VERSION 5.8 ;
BUSBITCHARS "[]" ;
DIVIDERCHAR "/" ;
UNITS
    DATABASE MICRONS 1000 ;
END UNITS

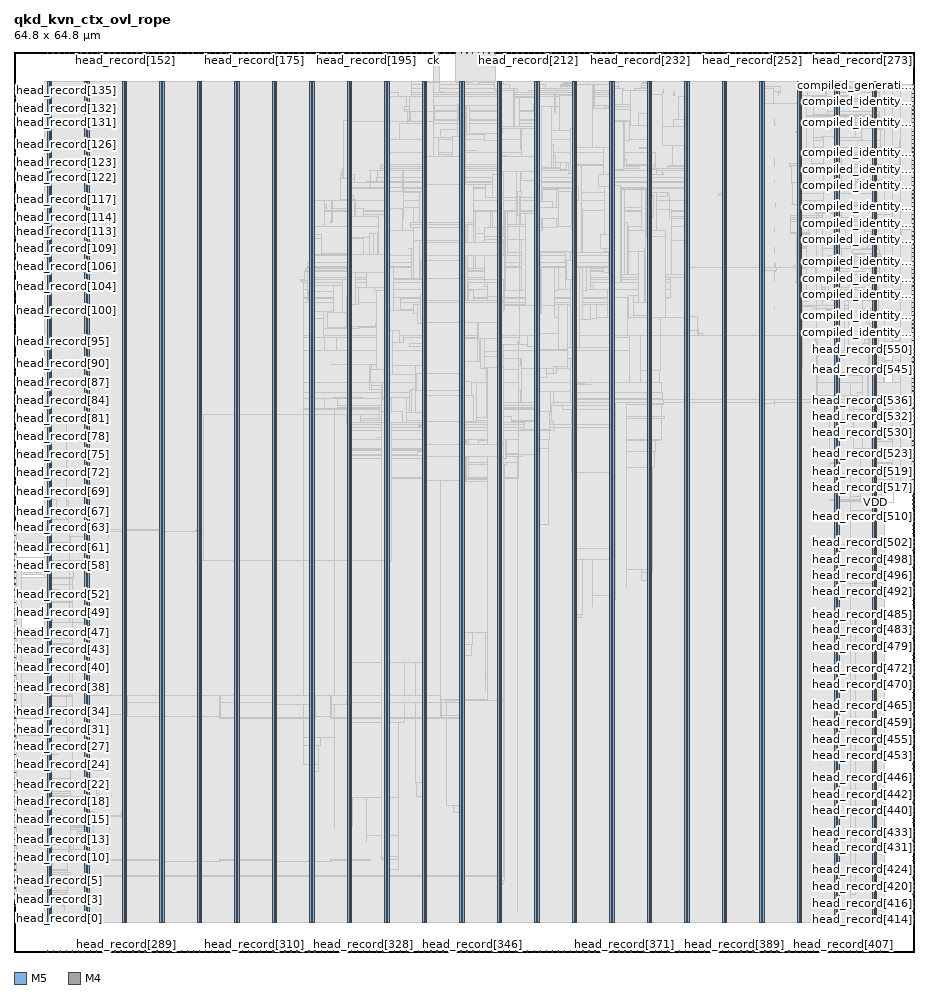
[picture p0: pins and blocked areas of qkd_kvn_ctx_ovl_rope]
MACRO qkd_kvn_ctx_ovl_rope
  FOREIGN qkd_kvn_ctx_ovl_rope 0 0 ;
  CLASS BLOCK ;
  SIZE 64.8 BY 64.8 ;
  PIN adm_done
    DIRECTION INPUT ;
    USE SIGNAL ;
    PORT
      LAYER M5 ;
        RECT  34.176 64.716 34.2 64.8 ;
    END
  END adm_done
  PIN calrx[0]
    DIRECTION INPUT ;
    USE SIGNAL ;
    PORT
      LAYER M5 ;
        RECT  32.592 64.716 32.616 64.8 ;
    END
  END calrx[0]
  PIN calrx[1]
    DIRECTION INPUT ;
    USE SIGNAL ;
    PORT
      LAYER M5 ;
        RECT  32.976 64.716 33 64.8 ;
    END
  END calrx[1]
  PIN calrx[2]
    DIRECTION INPUT ;
    USE SIGNAL ;
    PORT
      LAYER M5 ;
        RECT  33.408 64.716 33.432 64.8 ;
    END
  END calrx[2]
  PIN calrx[3]
    DIRECTION INPUT ;
    USE SIGNAL ;
    PORT
      LAYER M5 ;
        RECT  33.792 64.716 33.816 64.8 ;
    END
  END calrx[3]
  PIN ck
    DIRECTION INPUT ;
    USE SIGNAL ;
    PORT
      LAYER M5 ;
        RECT  30.192 64.716 30.216 64.8 ;
    END
  END ck
  PIN compiled_generation[0]
    DIRECTION OUTPUT ;
    USE SIGNAL ;
    PORT
      LAYER M4 ;
        RECT  64.716 61.824 64.8 61.848 ;
    END
  END compiled_generation[0]
  PIN compiled_generation[1]
    DIRECTION OUTPUT ;
    USE SIGNAL ;
    PORT
      LAYER M4 ;
        RECT  64.716 62.112 64.8 62.136 ;
    END
  END compiled_generation[1]
  PIN compiled_identity[0]
    DIRECTION OUTPUT ;
    USE SIGNAL ;
    PORT
      LAYER M4 ;
        RECT  64.716 44.016 64.8 44.04 ;
    END
  END compiled_identity[0]
  PIN compiled_identity[10]
    DIRECTION OUTPUT ;
    USE SIGNAL ;
    PORT
      LAYER M4 ;
        RECT  64.716 47.04 64.8 47.064 ;
    END
  END compiled_identity[10]
  PIN compiled_identity[11]
    DIRECTION OUTPUT ;
    USE SIGNAL ;
    PORT
      LAYER M4 ;
        RECT  64.716 47.328 64.8 47.352 ;
    END
  END compiled_identity[11]
  PIN compiled_identity[12]
    DIRECTION OUTPUT ;
    USE SIGNAL ;
    PORT
      LAYER M4 ;
        RECT  64.716 47.616 64.8 47.64 ;
    END
  END compiled_identity[12]
  PIN compiled_identity[13]
    DIRECTION OUTPUT ;
    USE SIGNAL ;
    PORT
      LAYER M4 ;
        RECT  64.716 47.952 64.8 47.976 ;
    END
  END compiled_identity[13]
  PIN compiled_identity[14]
    DIRECTION OUTPUT ;
    USE SIGNAL ;
    PORT
      LAYER M4 ;
        RECT  64.716 48.24 64.8 48.264 ;
    END
  END compiled_identity[14]
  PIN compiled_identity[15]
    DIRECTION OUTPUT ;
    USE SIGNAL ;
    PORT
      LAYER M4 ;
        RECT  64.716 48.528 64.8 48.552 ;
    END
  END compiled_identity[15]
  PIN compiled_identity[16]
    DIRECTION OUTPUT ;
    USE SIGNAL ;
    PORT
      LAYER M4 ;
        RECT  64.716 48.864 64.8 48.888 ;
    END
  END compiled_identity[16]
  PIN compiled_identity[17]
    DIRECTION OUTPUT ;
    USE SIGNAL ;
    PORT
      LAYER M4 ;
        RECT  64.716 49.152 64.8 49.176 ;
    END
  END compiled_identity[17]
  PIN compiled_identity[18]
    DIRECTION OUTPUT ;
    USE SIGNAL ;
    PORT
      LAYER M4 ;
        RECT  64.716 49.44 64.8 49.464 ;
    END
  END compiled_identity[18]
  PIN compiled_identity[19]
    DIRECTION OUTPUT ;
    USE SIGNAL ;
    PORT
      LAYER M4 ;
        RECT  64.716 49.728 64.8 49.752 ;
    END
  END compiled_identity[19]
  PIN compiled_identity[1]
    DIRECTION OUTPUT ;
    USE SIGNAL ;
    PORT
      LAYER M4 ;
        RECT  64.716 44.304 64.8 44.328 ;
    END
  END compiled_identity[1]
  PIN compiled_identity[20]
    DIRECTION OUTPUT ;
    USE SIGNAL ;
    PORT
      LAYER M4 ;
        RECT  64.716 50.064 64.8 50.088 ;
    END
  END compiled_identity[20]
  PIN compiled_identity[21]
    DIRECTION OUTPUT ;
    USE SIGNAL ;
    PORT
      LAYER M4 ;
        RECT  64.716 50.352 64.8 50.376 ;
    END
  END compiled_identity[21]
  PIN compiled_identity[22]
    DIRECTION OUTPUT ;
    USE SIGNAL ;
    PORT
      LAYER M4 ;
        RECT  64.716 50.64 64.8 50.664 ;
    END
  END compiled_identity[22]
  PIN compiled_identity[23]
    DIRECTION OUTPUT ;
    USE SIGNAL ;
    PORT
      LAYER M4 ;
        RECT  64.716 50.976 64.8 51 ;
    END
  END compiled_identity[23]
  PIN compiled_identity[24]
    DIRECTION OUTPUT ;
    USE SIGNAL ;
    PORT
      LAYER M4 ;
        RECT  64.716 51.264 64.8 51.288 ;
    END
  END compiled_identity[24]
  PIN compiled_identity[25]
    DIRECTION OUTPUT ;
    USE SIGNAL ;
    PORT
      LAYER M4 ;
        RECT  64.716 51.552 64.8 51.576 ;
    END
  END compiled_identity[25]
  PIN compiled_identity[26]
    DIRECTION OUTPUT ;
    USE SIGNAL ;
    PORT
      LAYER M4 ;
        RECT  64.716 51.84 64.8 51.864 ;
    END
  END compiled_identity[26]
  PIN compiled_identity[27]
    DIRECTION OUTPUT ;
    USE SIGNAL ;
    PORT
      LAYER M4 ;
        RECT  64.716 52.176 64.8 52.2 ;
    END
  END compiled_identity[27]
  PIN compiled_identity[28]
    DIRECTION OUTPUT ;
    USE SIGNAL ;
    PORT
      LAYER M4 ;
        RECT  64.716 52.464 64.8 52.488 ;
    END
  END compiled_identity[28]
  PIN compiled_identity[29]
    DIRECTION OUTPUT ;
    USE SIGNAL ;
    PORT
      LAYER M4 ;
        RECT  64.716 52.752 64.8 52.776 ;
    END
  END compiled_identity[29]
  PIN compiled_identity[2]
    DIRECTION OUTPUT ;
    USE SIGNAL ;
    PORT
      LAYER M4 ;
        RECT  64.716 44.592 64.8 44.616 ;
    END
  END compiled_identity[2]
  PIN compiled_identity[30]
    DIRECTION OUTPUT ;
    USE SIGNAL ;
    PORT
      LAYER M4 ;
        RECT  64.716 53.088 64.8 53.112 ;
    END
  END compiled_identity[30]
  PIN compiled_identity[31]
    DIRECTION OUTPUT ;
    USE SIGNAL ;
    PORT
      LAYER M4 ;
        RECT  64.716 53.376 64.8 53.4 ;
    END
  END compiled_identity[31]
  PIN compiled_identity[32]
    DIRECTION OUTPUT ;
    USE SIGNAL ;
    PORT
      LAYER M4 ;
        RECT  64.716 53.664 64.8 53.688 ;
    END
  END compiled_identity[32]
  PIN compiled_identity[33]
    DIRECTION OUTPUT ;
    USE SIGNAL ;
    PORT
      LAYER M4 ;
        RECT  64.716 53.952 64.8 53.976 ;
    END
  END compiled_identity[33]
  PIN compiled_identity[34]
    DIRECTION OUTPUT ;
    USE SIGNAL ;
    PORT
      LAYER M4 ;
        RECT  64.716 54.288 64.8 54.312 ;
    END
  END compiled_identity[34]
  PIN compiled_identity[35]
    DIRECTION OUTPUT ;
    USE SIGNAL ;
    PORT
      LAYER M4 ;
        RECT  64.716 54.576 64.8 54.6 ;
    END
  END compiled_identity[35]
  PIN compiled_identity[36]
    DIRECTION OUTPUT ;
    USE SIGNAL ;
    PORT
      LAYER M4 ;
        RECT  64.716 54.864 64.8 54.888 ;
    END
  END compiled_identity[36]
  PIN compiled_identity[37]
    DIRECTION OUTPUT ;
    USE SIGNAL ;
    PORT
      LAYER M4 ;
        RECT  64.716 55.2 64.8 55.224 ;
    END
  END compiled_identity[37]
  PIN compiled_identity[38]
    DIRECTION OUTPUT ;
    USE SIGNAL ;
    PORT
      LAYER M4 ;
        RECT  64.716 55.488 64.8 55.512 ;
    END
  END compiled_identity[38]
  PIN compiled_identity[39]
    DIRECTION OUTPUT ;
    USE SIGNAL ;
    PORT
      LAYER M4 ;
        RECT  64.716 55.776 64.8 55.8 ;
    END
  END compiled_identity[39]
  PIN compiled_identity[3]
    DIRECTION OUTPUT ;
    USE SIGNAL ;
    PORT
      LAYER M4 ;
        RECT  64.716 44.928 64.8 44.952 ;
    END
  END compiled_identity[3]
  PIN compiled_identity[40]
    DIRECTION OUTPUT ;
    USE SIGNAL ;
    PORT
      LAYER M4 ;
        RECT  64.716 56.112 64.8 56.136 ;
    END
  END compiled_identity[40]
  PIN compiled_identity[41]
    DIRECTION OUTPUT ;
    USE SIGNAL ;
    PORT
      LAYER M4 ;
        RECT  64.716 56.4 64.8 56.424 ;
    END
  END compiled_identity[41]
  PIN compiled_identity[42]
    DIRECTION OUTPUT ;
    USE SIGNAL ;
    PORT
      LAYER M4 ;
        RECT  64.716 56.688 64.8 56.712 ;
    END
  END compiled_identity[42]
  PIN compiled_identity[43]
    DIRECTION OUTPUT ;
    USE SIGNAL ;
    PORT
      LAYER M4 ;
        RECT  64.716 56.976 64.8 57 ;
    END
  END compiled_identity[43]
  PIN compiled_identity[44]
    DIRECTION OUTPUT ;
    USE SIGNAL ;
    PORT
      LAYER M4 ;
        RECT  64.716 57.312 64.8 57.336 ;
    END
  END compiled_identity[44]
  PIN compiled_identity[45]
    DIRECTION OUTPUT ;
    USE SIGNAL ;
    PORT
      LAYER M4 ;
        RECT  64.716 57.6 64.8 57.624 ;
    END
  END compiled_identity[45]
  PIN compiled_identity[46]
    DIRECTION OUTPUT ;
    USE SIGNAL ;
    PORT
      LAYER M4 ;
        RECT  64.716 57.888 64.8 57.912 ;
    END
  END compiled_identity[46]
  PIN compiled_identity[47]
    DIRECTION OUTPUT ;
    USE SIGNAL ;
    PORT
      LAYER M4 ;
        RECT  64.716 58.224 64.8 58.248 ;
    END
  END compiled_identity[47]
  PIN compiled_identity[48]
    DIRECTION OUTPUT ;
    USE SIGNAL ;
    PORT
      LAYER M4 ;
        RECT  64.716 58.512 64.8 58.536 ;
    END
  END compiled_identity[48]
  PIN compiled_identity[49]
    DIRECTION OUTPUT ;
    USE SIGNAL ;
    PORT
      LAYER M4 ;
        RECT  64.716 58.8 64.8 58.824 ;
    END
  END compiled_identity[49]
  PIN compiled_identity[4]
    DIRECTION OUTPUT ;
    USE SIGNAL ;
    PORT
      LAYER M4 ;
        RECT  64.716 45.216 64.8 45.24 ;
    END
  END compiled_identity[4]
  PIN compiled_identity[50]
    DIRECTION OUTPUT ;
    USE SIGNAL ;
    PORT
      LAYER M4 ;
        RECT  64.716 59.088 64.8 59.112 ;
    END
  END compiled_identity[50]
  PIN compiled_identity[51]
    DIRECTION OUTPUT ;
    USE SIGNAL ;
    PORT
      LAYER M4 ;
        RECT  64.716 59.424 64.8 59.448 ;
    END
  END compiled_identity[51]
  PIN compiled_identity[52]
    DIRECTION OUTPUT ;
    USE SIGNAL ;
    PORT
      LAYER M4 ;
        RECT  64.716 59.712 64.8 59.736 ;
    END
  END compiled_identity[52]
  PIN compiled_identity[53]
    DIRECTION OUTPUT ;
    USE SIGNAL ;
    PORT
      LAYER M4 ;
        RECT  64.716 60 64.8 60.024 ;
    END
  END compiled_identity[53]
  PIN compiled_identity[54]
    DIRECTION OUTPUT ;
    USE SIGNAL ;
    PORT
      LAYER M4 ;
        RECT  64.716 60.336 64.8 60.36 ;
    END
  END compiled_identity[54]
  PIN compiled_identity[55]
    DIRECTION OUTPUT ;
    USE SIGNAL ;
    PORT
      LAYER M4 ;
        RECT  64.716 60.624 64.8 60.648 ;
    END
  END compiled_identity[55]
  PIN compiled_identity[56]
    DIRECTION OUTPUT ;
    USE SIGNAL ;
    PORT
      LAYER M4 ;
        RECT  64.716 60.912 64.8 60.936 ;
    END
  END compiled_identity[56]
  PIN compiled_identity[57]
    DIRECTION OUTPUT ;
    USE SIGNAL ;
    PORT
      LAYER M4 ;
        RECT  64.716 61.2 64.8 61.224 ;
    END
  END compiled_identity[57]
  PIN compiled_identity[58]
    DIRECTION OUTPUT ;
    USE SIGNAL ;
    PORT
      LAYER M4 ;
        RECT  64.716 61.536 64.8 61.56 ;
    END
  END compiled_identity[58]
  PIN compiled_identity[5]
    DIRECTION OUTPUT ;
    USE SIGNAL ;
    PORT
      LAYER M4 ;
        RECT  64.716 45.504 64.8 45.528 ;
    END
  END compiled_identity[5]
  PIN compiled_identity[6]
    DIRECTION OUTPUT ;
    USE SIGNAL ;
    PORT
      LAYER M4 ;
        RECT  64.716 45.84 64.8 45.864 ;
    END
  END compiled_identity[6]
  PIN compiled_identity[7]
    DIRECTION OUTPUT ;
    USE SIGNAL ;
    PORT
      LAYER M4 ;
        RECT  64.716 46.128 64.8 46.152 ;
    END
  END compiled_identity[7]
  PIN compiled_identity[8]
    DIRECTION OUTPUT ;
    USE SIGNAL ;
    PORT
      LAYER M4 ;
        RECT  64.716 46.416 64.8 46.44 ;
    END
  END compiled_identity[8]
  PIN compiled_identity[9]
    DIRECTION OUTPUT ;
    USE SIGNAL ;
    PORT
      LAYER M4 ;
        RECT  64.716 46.752 64.8 46.776 ;
    END
  END compiled_identity[9]
  PIN fault
    DIRECTION OUTPUT ;
    USE SIGNAL ;
    PORT
      LAYER M4 ;
        RECT  64.716 62.448 64.8 62.472 ;
    END
  END fault
  PIN head_record[0]
    DIRECTION INPUT ;
    USE SIGNAL ;
    PORT
      LAYER M4 ;
        RECT  0 2.4 0.084 2.424 ;
    END
  END head_record[0]
  PIN head_record[100]
    DIRECTION INPUT ;
    USE SIGNAL ;
    PORT
      LAYER M4 ;
        RECT  0 46.176 0.084 46.2 ;
    END
  END head_record[100]
  PIN head_record[101]
    DIRECTION INPUT ;
    USE SIGNAL ;
    PORT
      LAYER M4 ;
        RECT  0 46.608 0.084 46.632 ;
    END
  END head_record[101]
  PIN head_record[102]
    DIRECTION INPUT ;
    USE SIGNAL ;
    PORT
      LAYER M4 ;
        RECT  0 47.04 0.084 47.064 ;
    END
  END head_record[102]
  PIN head_record[103]
    DIRECTION INPUT ;
    USE SIGNAL ;
    PORT
      LAYER M4 ;
        RECT  0 47.472 0.084 47.496 ;
    END
  END head_record[103]
  PIN head_record[104]
    DIRECTION INPUT ;
    USE SIGNAL ;
    PORT
      LAYER M4 ;
        RECT  0 47.904 0.084 47.928 ;
    END
  END head_record[104]
  PIN head_record[105]
    DIRECTION INPUT ;
    USE SIGNAL ;
    PORT
      LAYER M4 ;
        RECT  0 48.336 0.084 48.36 ;
    END
  END head_record[105]
  PIN head_record[106]
    DIRECTION INPUT ;
    USE SIGNAL ;
    PORT
      LAYER M4 ;
        RECT  0 48.816 0.084 48.84 ;
    END
  END head_record[106]
  PIN head_record[107]
    DIRECTION INPUT ;
    USE SIGNAL ;
    PORT
      LAYER M4 ;
        RECT  0 49.248 0.084 49.272 ;
    END
  END head_record[107]
  PIN head_record[108]
    DIRECTION INPUT ;
    USE SIGNAL ;
    PORT
      LAYER M4 ;
        RECT  0 49.68 0.084 49.704 ;
    END
  END head_record[108]
  PIN head_record[109]
    DIRECTION INPUT ;
    USE SIGNAL ;
    PORT
      LAYER M4 ;
        RECT  0 50.112 0.084 50.136 ;
    END
  END head_record[109]
  PIN head_record[10]
    DIRECTION INPUT ;
    USE SIGNAL ;
    PORT
      LAYER M4 ;
        RECT  0 6.768 0.084 6.792 ;
    END
  END head_record[10]
  PIN head_record[110]
    DIRECTION INPUT ;
    USE SIGNAL ;
    PORT
      LAYER M4 ;
        RECT  0 50.544 0.084 50.568 ;
    END
  END head_record[110]
  PIN head_record[111]
    DIRECTION INPUT ;
    USE SIGNAL ;
    PORT
      LAYER M4 ;
        RECT  0 50.976 0.084 51 ;
    END
  END head_record[111]
  PIN head_record[112]
    DIRECTION INPUT ;
    USE SIGNAL ;
    PORT
      LAYER M4 ;
        RECT  0 51.408 0.084 51.432 ;
    END
  END head_record[112]
  PIN head_record[113]
    DIRECTION INPUT ;
    USE SIGNAL ;
    PORT
      LAYER M4 ;
        RECT  0 51.84 0.084 51.864 ;
    END
  END head_record[113]
  PIN head_record[114]
    DIRECTION INPUT ;
    USE SIGNAL ;
    PORT
      LAYER M4 ;
        RECT  0 52.32 0.084 52.344 ;
    END
  END head_record[114]
  PIN head_record[115]
    DIRECTION INPUT ;
    USE SIGNAL ;
    PORT
      LAYER M4 ;
        RECT  0 52.752 0.084 52.776 ;
    END
  END head_record[115]
  PIN head_record[116]
    DIRECTION INPUT ;
    USE SIGNAL ;
    PORT
      LAYER M4 ;
        RECT  0 53.184 0.084 53.208 ;
    END
  END head_record[116]
  PIN head_record[117]
    DIRECTION INPUT ;
    USE SIGNAL ;
    PORT
      LAYER M4 ;
        RECT  0 53.616 0.084 53.64 ;
    END
  END head_record[117]
  PIN head_record[118]
    DIRECTION INPUT ;
    USE SIGNAL ;
    PORT
      LAYER M4 ;
        RECT  0 54.048 0.084 54.072 ;
    END
  END head_record[118]
  PIN head_record[119]
    DIRECTION INPUT ;
    USE SIGNAL ;
    PORT
      LAYER M4 ;
        RECT  0 54.48 0.084 54.504 ;
    END
  END head_record[119]
  PIN head_record[11]
    DIRECTION INPUT ;
    USE SIGNAL ;
    PORT
      LAYER M4 ;
        RECT  0 7.248 0.084 7.272 ;
    END
  END head_record[11]
  PIN head_record[120]
    DIRECTION INPUT ;
    USE SIGNAL ;
    PORT
      LAYER M4 ;
        RECT  0 54.912 0.084 54.936 ;
    END
  END head_record[120]
  PIN head_record[121]
    DIRECTION INPUT ;
    USE SIGNAL ;
    PORT
      LAYER M4 ;
        RECT  0 55.344 0.084 55.368 ;
    END
  END head_record[121]
  PIN head_record[122]
    DIRECTION INPUT ;
    USE SIGNAL ;
    PORT
      LAYER M4 ;
        RECT  0 55.776 0.084 55.8 ;
    END
  END head_record[122]
  PIN head_record[123]
    DIRECTION INPUT ;
    USE SIGNAL ;
    PORT
      LAYER M4 ;
        RECT  0 56.256 0.084 56.28 ;
    END
  END head_record[123]
  PIN head_record[124]
    DIRECTION INPUT ;
    USE SIGNAL ;
    PORT
      LAYER M4 ;
        RECT  0 56.688 0.084 56.712 ;
    END
  END head_record[124]
  PIN head_record[125]
    DIRECTION INPUT ;
    USE SIGNAL ;
    PORT
      LAYER M4 ;
        RECT  0 57.12 0.084 57.144 ;
    END
  END head_record[125]
  PIN head_record[126]
    DIRECTION INPUT ;
    USE SIGNAL ;
    PORT
      LAYER M4 ;
        RECT  0 57.552 0.084 57.576 ;
    END
  END head_record[126]
  PIN head_record[127]
    DIRECTION INPUT ;
    USE SIGNAL ;
    PORT
      LAYER M4 ;
        RECT  0 57.984 0.084 58.008 ;
    END
  END head_record[127]
  PIN head_record[128]
    DIRECTION INPUT ;
    USE SIGNAL ;
    PORT
      LAYER M4 ;
        RECT  0 58.416 0.084 58.44 ;
    END
  END head_record[128]
  PIN head_record[129]
    DIRECTION INPUT ;
    USE SIGNAL ;
    PORT
      LAYER M4 ;
        RECT  0 58.848 0.084 58.872 ;
    END
  END head_record[129]
  PIN head_record[12]
    DIRECTION INPUT ;
    USE SIGNAL ;
    PORT
      LAYER M4 ;
        RECT  0 7.68 0.084 7.704 ;
    END
  END head_record[12]
  PIN head_record[130]
    DIRECTION INPUT ;
    USE SIGNAL ;
    PORT
      LAYER M4 ;
        RECT  0 59.28 0.084 59.304 ;
    END
  END head_record[130]
  PIN head_record[131]
    DIRECTION INPUT ;
    USE SIGNAL ;
    PORT
      LAYER M4 ;
        RECT  0 59.712 0.084 59.736 ;
    END
  END head_record[131]
  PIN head_record[132]
    DIRECTION INPUT ;
    USE SIGNAL ;
    PORT
      LAYER M4 ;
        RECT  0 60.192 0.084 60.216 ;
    END
  END head_record[132]
  PIN head_record[133]
    DIRECTION INPUT ;
    USE SIGNAL ;
    PORT
      LAYER M4 ;
        RECT  0 60.624 0.084 60.648 ;
    END
  END head_record[133]
  PIN head_record[134]
    DIRECTION INPUT ;
    USE SIGNAL ;
    PORT
      LAYER M4 ;
        RECT  0 61.056 0.084 61.08 ;
    END
  END head_record[134]
  PIN head_record[135]
    DIRECTION INPUT ;
    USE SIGNAL ;
    PORT
      LAYER M4 ;
        RECT  0 61.488 0.084 61.512 ;
    END
  END head_record[135]
  PIN head_record[136]
    DIRECTION INPUT ;
    USE SIGNAL ;
    PORT
      LAYER M4 ;
        RECT  0 61.92 0.084 61.944 ;
    END
  END head_record[136]
  PIN head_record[137]
    DIRECTION INPUT ;
    USE SIGNAL ;
    PORT
      LAYER M4 ;
        RECT  0 62.352 0.084 62.376 ;
    END
  END head_record[137]
  PIN head_record[138]
    DIRECTION INPUT ;
    USE SIGNAL ;
    PORT
      LAYER M5 ;
        RECT  2.4 64.716 2.424 64.8 ;
    END
  END head_record[138]
  PIN head_record[139]
    DIRECTION INPUT ;
    USE SIGNAL ;
    PORT
      LAYER M5 ;
        RECT  2.784 64.716 2.808 64.8 ;
    END
  END head_record[139]
  PIN head_record[13]
    DIRECTION INPUT ;
    USE SIGNAL ;
    PORT
      LAYER M4 ;
        RECT  0 8.112 0.084 8.136 ;
    END
  END head_record[13]
  PIN head_record[140]
    DIRECTION INPUT ;
    USE SIGNAL ;
    PORT
      LAYER M5 ;
        RECT  3.216 64.716 3.24 64.8 ;
    END
  END head_record[140]
  PIN head_record[141]
    DIRECTION INPUT ;
    USE SIGNAL ;
    PORT
      LAYER M5 ;
        RECT  3.6 64.716 3.624 64.8 ;
    END
  END head_record[141]
  PIN head_record[142]
    DIRECTION INPUT ;
    USE SIGNAL ;
    PORT
      LAYER M5 ;
        RECT  3.984 64.716 4.008 64.8 ;
    END
  END head_record[142]
  PIN head_record[143]
    DIRECTION INPUT ;
    USE SIGNAL ;
    PORT
      LAYER M5 ;
        RECT  4.416 64.716 4.44 64.8 ;
    END
  END head_record[143]
  PIN head_record[144]
    DIRECTION INPUT ;
    USE SIGNAL ;
    PORT
      LAYER M5 ;
        RECT  4.8 64.716 4.824 64.8 ;
    END
  END head_record[144]
  PIN head_record[145]
    DIRECTION INPUT ;
    USE SIGNAL ;
    PORT
      LAYER M5 ;
        RECT  5.232 64.716 5.256 64.8 ;
    END
  END head_record[145]
  PIN head_record[146]
    DIRECTION INPUT ;
    USE SIGNAL ;
    PORT
      LAYER M5 ;
        RECT  5.616 64.716 5.64 64.8 ;
    END
  END head_record[146]
  PIN head_record[147]
    DIRECTION INPUT ;
    USE SIGNAL ;
    PORT
      LAYER M5 ;
        RECT  6 64.716 6.024 64.8 ;
    END
  END head_record[147]
  PIN head_record[148]
    DIRECTION INPUT ;
    USE SIGNAL ;
    PORT
      LAYER M5 ;
        RECT  6.432 64.716 6.456 64.8 ;
    END
  END head_record[148]
  PIN head_record[149]
    DIRECTION INPUT ;
    USE SIGNAL ;
    PORT
      LAYER M5 ;
        RECT  6.816 64.716 6.84 64.8 ;
    END
  END head_record[149]
  PIN head_record[14]
    DIRECTION INPUT ;
    USE SIGNAL ;
    PORT
      LAYER M4 ;
        RECT  0 8.544 0.084 8.568 ;
    END
  END head_record[14]
  PIN head_record[150]
    DIRECTION INPUT ;
    USE SIGNAL ;
    PORT
      LAYER M5 ;
        RECT  7.248 64.716 7.272 64.8 ;
    END
  END head_record[150]
  PIN head_record[151]
    DIRECTION INPUT ;
    USE SIGNAL ;
    PORT
      LAYER M5 ;
        RECT  7.632 64.716 7.656 64.8 ;
    END
  END head_record[151]
  PIN head_record[152]
    DIRECTION INPUT ;
    USE SIGNAL ;
    PORT
      LAYER M5 ;
        RECT  8.016 64.716 8.04 64.8 ;
    END
  END head_record[152]
  PIN head_record[153]
    DIRECTION INPUT ;
    USE SIGNAL ;
    PORT
      LAYER M5 ;
        RECT  8.448 64.716 8.472 64.8 ;
    END
  END head_record[153]
  PIN head_record[154]
    DIRECTION INPUT ;
    USE SIGNAL ;
    PORT
      LAYER M5 ;
        RECT  8.832 64.716 8.856 64.8 ;
    END
  END head_record[154]
  PIN head_record[155]
    DIRECTION INPUT ;
    USE SIGNAL ;
    PORT
      LAYER M5 ;
        RECT  9.264 64.716 9.288 64.8 ;
    END
  END head_record[155]
  PIN head_record[156]
    DIRECTION INPUT ;
    USE SIGNAL ;
    PORT
      LAYER M5 ;
        RECT  9.648 64.716 9.672 64.8 ;
    END
  END head_record[156]
  PIN head_record[157]
    DIRECTION INPUT ;
    USE SIGNAL ;
    PORT
      LAYER M5 ;
        RECT  10.032 64.716 10.056 64.8 ;
    END
  END head_record[157]
  PIN head_record[158]
    DIRECTION INPUT ;
    USE SIGNAL ;
    PORT
      LAYER M5 ;
        RECT  10.464 64.716 10.488 64.8 ;
    END
  END head_record[158]
  PIN head_record[159]
    DIRECTION INPUT ;
    USE SIGNAL ;
    PORT
      LAYER M5 ;
        RECT  10.848 64.716 10.872 64.8 ;
    END
  END head_record[159]
  PIN head_record[15]
    DIRECTION INPUT ;
    USE SIGNAL ;
    PORT
      LAYER M4 ;
        RECT  0 8.976 0.084 9 ;
    END
  END head_record[15]
  PIN head_record[160]
    DIRECTION INPUT ;
    USE SIGNAL ;
    PORT
      LAYER M5 ;
        RECT  11.232 64.716 11.256 64.8 ;
    END
  END head_record[160]
  PIN head_record[161]
    DIRECTION INPUT ;
    USE SIGNAL ;
    PORT
      LAYER M5 ;
        RECT  11.664 64.716 11.688 64.8 ;
    END
  END head_record[161]
  PIN head_record[162]
    DIRECTION INPUT ;
    USE SIGNAL ;
    PORT
      LAYER M5 ;
        RECT  12.048 64.716 12.072 64.8 ;
    END
  END head_record[162]
  PIN head_record[163]
    DIRECTION INPUT ;
    USE SIGNAL ;
    PORT
      LAYER M5 ;
        RECT  12.48 64.716 12.504 64.8 ;
    END
  END head_record[163]
  PIN head_record[164]
    DIRECTION INPUT ;
    USE SIGNAL ;
    PORT
      LAYER M5 ;
        RECT  12.864 64.716 12.888 64.8 ;
    END
  END head_record[164]
  PIN head_record[165]
    DIRECTION INPUT ;
    USE SIGNAL ;
    PORT
      LAYER M5 ;
        RECT  13.248 64.716 13.272 64.8 ;
    END
  END head_record[165]
  PIN head_record[166]
    DIRECTION INPUT ;
    USE SIGNAL ;
    PORT
      LAYER M5 ;
        RECT  13.68 64.716 13.704 64.8 ;
    END
  END head_record[166]
  PIN head_record[167]
    DIRECTION INPUT ;
    USE SIGNAL ;
    PORT
      LAYER M5 ;
        RECT  14.064 64.716 14.088 64.8 ;
    END
  END head_record[167]
  PIN head_record[168]
    DIRECTION INPUT ;
    USE SIGNAL ;
    PORT
      LAYER M5 ;
        RECT  14.496 64.716 14.52 64.8 ;
    END
  END head_record[168]
  PIN head_record[169]
    DIRECTION INPUT ;
    USE SIGNAL ;
    PORT
      LAYER M5 ;
        RECT  14.88 64.716 14.904 64.8 ;
    END
  END head_record[169]
  PIN head_record[16]
    DIRECTION INPUT ;
    USE SIGNAL ;
    PORT
      LAYER M4 ;
        RECT  0 9.408 0.084 9.432 ;
    END
  END head_record[16]
  PIN head_record[170]
    DIRECTION INPUT ;
    USE SIGNAL ;
    PORT
      LAYER M5 ;
        RECT  15.264 64.716 15.288 64.8 ;
    END
  END head_record[170]
  PIN head_record[171]
    DIRECTION INPUT ;
    USE SIGNAL ;
    PORT
      LAYER M5 ;
        RECT  15.696 64.716 15.72 64.8 ;
    END
  END head_record[171]
  PIN head_record[172]
    DIRECTION INPUT ;
    USE SIGNAL ;
    PORT
      LAYER M5 ;
        RECT  16.08 64.716 16.104 64.8 ;
    END
  END head_record[172]
  PIN head_record[173]
    DIRECTION INPUT ;
    USE SIGNAL ;
    PORT
      LAYER M5 ;
        RECT  16.464 64.716 16.488 64.8 ;
    END
  END head_record[173]
  PIN head_record[174]
    DIRECTION INPUT ;
    USE SIGNAL ;
    PORT
      LAYER M5 ;
        RECT  16.896 64.716 16.92 64.8 ;
    END
  END head_record[174]
  PIN head_record[175]
    DIRECTION INPUT ;
    USE SIGNAL ;
    PORT
      LAYER M5 ;
        RECT  17.28 64.716 17.304 64.8 ;
    END
  END head_record[175]
  PIN head_record[176]
    DIRECTION INPUT ;
    USE SIGNAL ;
    PORT
      LAYER M5 ;
        RECT  17.712 64.716 17.736 64.8 ;
    END
  END head_record[176]
  PIN head_record[177]
    DIRECTION INPUT ;
    USE SIGNAL ;
    PORT
      LAYER M5 ;
        RECT  18.096 64.716 18.12 64.8 ;
    END
  END head_record[177]
  PIN head_record[178]
    DIRECTION INPUT ;
    USE SIGNAL ;
    PORT
      LAYER M5 ;
        RECT  18.48 64.716 18.504 64.8 ;
    END
  END head_record[178]
  PIN head_record[179]
    DIRECTION INPUT ;
    USE SIGNAL ;
    PORT
      LAYER M5 ;
        RECT  18.912 64.716 18.936 64.8 ;
    END
  END head_record[179]
  PIN head_record[17]
    DIRECTION INPUT ;
    USE SIGNAL ;
    PORT
      LAYER M4 ;
        RECT  0 9.84 0.084 9.864 ;
    END
  END head_record[17]
  PIN head_record[180]
    DIRECTION INPUT ;
    USE SIGNAL ;
    PORT
      LAYER M5 ;
        RECT  19.296 64.716 19.32 64.8 ;
    END
  END head_record[180]
  PIN head_record[181]
    DIRECTION INPUT ;
    USE SIGNAL ;
    PORT
      LAYER M5 ;
        RECT  19.728 64.716 19.752 64.8 ;
    END
  END head_record[181]
  PIN head_record[182]
    DIRECTION INPUT ;
    USE SIGNAL ;
    PORT
      LAYER M5 ;
        RECT  20.112 64.716 20.136 64.8 ;
    END
  END head_record[182]
  PIN head_record[183]
    DIRECTION INPUT ;
    USE SIGNAL ;
    PORT
      LAYER M5 ;
        RECT  20.496 64.716 20.52 64.8 ;
    END
  END head_record[183]
  PIN head_record[184]
    DIRECTION INPUT ;
    USE SIGNAL ;
    PORT
      LAYER M5 ;
        RECT  20.928 64.716 20.952 64.8 ;
    END
  END head_record[184]
  PIN head_record[185]
    DIRECTION INPUT ;
    USE SIGNAL ;
    PORT
      LAYER M5 ;
        RECT  21.312 64.716 21.336 64.8 ;
    END
  END head_record[185]
  PIN head_record[186]
    DIRECTION INPUT ;
    USE SIGNAL ;
    PORT
      LAYER M5 ;
        RECT  21.744 64.716 21.768 64.8 ;
    END
  END head_record[186]
  PIN head_record[187]
    DIRECTION INPUT ;
    USE SIGNAL ;
    PORT
      LAYER M5 ;
        RECT  22.128 64.716 22.152 64.8 ;
    END
  END head_record[187]
  PIN head_record[188]
    DIRECTION INPUT ;
    USE SIGNAL ;
    PORT
      LAYER M5 ;
        RECT  22.512 64.716 22.536 64.8 ;
    END
  END head_record[188]
  PIN head_record[189]
    DIRECTION INPUT ;
    USE SIGNAL ;
    PORT
      LAYER M5 ;
        RECT  22.944 64.716 22.968 64.8 ;
    END
  END head_record[189]
  PIN head_record[18]
    DIRECTION INPUT ;
    USE SIGNAL ;
    PORT
      LAYER M4 ;
        RECT  0 10.272 0.084 10.296 ;
    END
  END head_record[18]
  PIN head_record[190]
    DIRECTION INPUT ;
    USE SIGNAL ;
    PORT
      LAYER M5 ;
        RECT  23.328 64.716 23.352 64.8 ;
    END
  END head_record[190]
  PIN head_record[191]
    DIRECTION INPUT ;
    USE SIGNAL ;
    PORT
      LAYER M5 ;
        RECT  23.712 64.716 23.736 64.8 ;
    END
  END head_record[191]
  PIN head_record[192]
    DIRECTION INPUT ;
    USE SIGNAL ;
    PORT
      LAYER M5 ;
        RECT  24.144 64.716 24.168 64.8 ;
    END
  END head_record[192]
  PIN head_record[193]
    DIRECTION INPUT ;
    USE SIGNAL ;
    PORT
      LAYER M5 ;
        RECT  24.528 64.716 24.552 64.8 ;
    END
  END head_record[193]
  PIN head_record[194]
    DIRECTION INPUT ;
    USE SIGNAL ;
    PORT
      LAYER M5 ;
        RECT  24.96 64.716 24.984 64.8 ;
    END
  END head_record[194]
  PIN head_record[195]
    DIRECTION INPUT ;
    USE SIGNAL ;
    PORT
      LAYER M5 ;
        RECT  25.344 64.716 25.368 64.8 ;
    END
  END head_record[195]
  PIN head_record[196]
    DIRECTION INPUT ;
    USE SIGNAL ;
    PORT
      LAYER M5 ;
        RECT  25.728 64.716 25.752 64.8 ;
    END
  END head_record[196]
  PIN head_record[197]
    DIRECTION INPUT ;
    USE SIGNAL ;
    PORT
      LAYER M5 ;
        RECT  26.16 64.716 26.184 64.8 ;
    END
  END head_record[197]
  PIN head_record[198]
    DIRECTION INPUT ;
    USE SIGNAL ;
    PORT
      LAYER M5 ;
        RECT  26.544 64.716 26.568 64.8 ;
    END
  END head_record[198]
  PIN head_record[199]
    DIRECTION INPUT ;
    USE SIGNAL ;
    PORT
      LAYER M5 ;
        RECT  26.976 64.716 27 64.8 ;
    END
  END head_record[199]
  PIN head_record[19]
    DIRECTION INPUT ;
    USE SIGNAL ;
    PORT
      LAYER M4 ;
        RECT  0 10.752 0.084 10.776 ;
    END
  END head_record[19]
  PIN head_record[1]
    DIRECTION INPUT ;
    USE SIGNAL ;
    PORT
      LAYER M4 ;
        RECT  0 2.832 0.084 2.856 ;
    END
  END head_record[1]
  PIN head_record[200]
    DIRECTION INPUT ;
    USE SIGNAL ;
    PORT
      LAYER M5 ;
        RECT  27.36 64.716 27.384 64.8 ;
    END
  END head_record[200]
  PIN head_record[201]
    DIRECTION INPUT ;
    USE SIGNAL ;
    PORT
      LAYER M5 ;
        RECT  27.744 64.716 27.768 64.8 ;
    END
  END head_record[201]
  PIN head_record[202]
    DIRECTION INPUT ;
    USE SIGNAL ;
    PORT
      LAYER M5 ;
        RECT  28.176 64.716 28.2 64.8 ;
    END
  END head_record[202]
  PIN head_record[203]
    DIRECTION INPUT ;
    USE SIGNAL ;
    PORT
      LAYER M5 ;
        RECT  28.56 64.716 28.584 64.8 ;
    END
  END head_record[203]
  PIN head_record[204]
    DIRECTION INPUT ;
    USE SIGNAL ;
    PORT
      LAYER M5 ;
        RECT  28.944 64.716 28.968 64.8 ;
    END
  END head_record[204]
  PIN head_record[205]
    DIRECTION INPUT ;
    USE SIGNAL ;
    PORT
      LAYER M5 ;
        RECT  29.376 64.716 29.4 64.8 ;
    END
  END head_record[205]
  PIN head_record[206]
    DIRECTION INPUT ;
    USE SIGNAL ;
    PORT
      LAYER M5 ;
        RECT  29.76 64.716 29.784 64.8 ;
    END
  END head_record[206]
  PIN head_record[207]
    DIRECTION INPUT ;
    USE SIGNAL ;
    PORT
      LAYER M5 ;
        RECT  34.992 64.716 35.016 64.8 ;
    END
  END head_record[207]
  PIN head_record[208]
    DIRECTION INPUT ;
    USE SIGNAL ;
    PORT
      LAYER M5 ;
        RECT  35.424 64.716 35.448 64.8 ;
    END
  END head_record[208]
  PIN head_record[209]
    DIRECTION INPUT ;
    USE SIGNAL ;
    PORT
      LAYER M5 ;
        RECT  35.808 64.716 35.832 64.8 ;
    END
  END head_record[209]
  PIN head_record[20]
    DIRECTION INPUT ;
    USE SIGNAL ;
    PORT
      LAYER M4 ;
        RECT  0 11.184 0.084 11.208 ;
    END
  END head_record[20]
  PIN head_record[210]
    DIRECTION INPUT ;
    USE SIGNAL ;
    PORT
      LAYER M5 ;
        RECT  36.192 64.716 36.216 64.8 ;
    END
  END head_record[210]
  PIN head_record[211]
    DIRECTION INPUT ;
    USE SIGNAL ;
    PORT
      LAYER M5 ;
        RECT  36.624 64.716 36.648 64.8 ;
    END
  END head_record[211]
  PIN head_record[212]
    DIRECTION INPUT ;
    USE SIGNAL ;
    PORT
      LAYER M5 ;
        RECT  37.008 64.716 37.032 64.8 ;
    END
  END head_record[212]
  PIN head_record[213]
    DIRECTION INPUT ;
    USE SIGNAL ;
    PORT
      LAYER M5 ;
        RECT  37.44 64.716 37.464 64.8 ;
    END
  END head_record[213]
  PIN head_record[214]
    DIRECTION INPUT ;
    USE SIGNAL ;
    PORT
      LAYER M5 ;
        RECT  37.824 64.716 37.848 64.8 ;
    END
  END head_record[214]
  PIN head_record[215]
    DIRECTION INPUT ;
    USE SIGNAL ;
    PORT
      LAYER M5 ;
        RECT  38.208 64.716 38.232 64.8 ;
    END
  END head_record[215]
  PIN head_record[216]
    DIRECTION INPUT ;
    USE SIGNAL ;
    PORT
      LAYER M5 ;
        RECT  38.64 64.716 38.664 64.8 ;
    END
  END head_record[216]
  PIN head_record[217]
    DIRECTION INPUT ;
    USE SIGNAL ;
    PORT
      LAYER M5 ;
        RECT  39.024 64.716 39.048 64.8 ;
    END
  END head_record[217]
  PIN head_record[218]
    DIRECTION INPUT ;
    USE SIGNAL ;
    PORT
      LAYER M5 ;
        RECT  39.456 64.716 39.48 64.8 ;
    END
  END head_record[218]
  PIN head_record[219]
    DIRECTION INPUT ;
    USE SIGNAL ;
    PORT
      LAYER M5 ;
        RECT  39.84 64.716 39.864 64.8 ;
    END
  END head_record[219]
  PIN head_record[21]
    DIRECTION INPUT ;
    USE SIGNAL ;
    PORT
      LAYER M4 ;
        RECT  0 11.616 0.084 11.64 ;
    END
  END head_record[21]
  PIN head_record[220]
    DIRECTION INPUT ;
    USE SIGNAL ;
    PORT
      LAYER M5 ;
        RECT  40.224 64.716 40.248 64.8 ;
    END
  END head_record[220]
  PIN head_record[221]
    DIRECTION INPUT ;
    USE SIGNAL ;
    PORT
      LAYER M5 ;
        RECT  40.656 64.716 40.68 64.8 ;
    END
  END head_record[221]
  PIN head_record[222]
    DIRECTION INPUT ;
    USE SIGNAL ;
    PORT
      LAYER M5 ;
        RECT  41.04 64.716 41.064 64.8 ;
    END
  END head_record[222]
  PIN head_record[223]
    DIRECTION INPUT ;
    USE SIGNAL ;
    PORT
      LAYER M5 ;
        RECT  41.424 64.716 41.448 64.8 ;
    END
  END head_record[223]
  PIN head_record[224]
    DIRECTION INPUT ;
    USE SIGNAL ;
    PORT
      LAYER M5 ;
        RECT  41.856 64.716 41.88 64.8 ;
    END
  END head_record[224]
  PIN head_record[225]
    DIRECTION INPUT ;
    USE SIGNAL ;
    PORT
      LAYER M5 ;
        RECT  42.24 64.716 42.264 64.8 ;
    END
  END head_record[225]
  PIN head_record[226]
    DIRECTION INPUT ;
    USE SIGNAL ;
    PORT
      LAYER M5 ;
        RECT  42.672 64.716 42.696 64.8 ;
    END
  END head_record[226]
  PIN head_record[227]
    DIRECTION INPUT ;
    USE SIGNAL ;
    PORT
      LAYER M5 ;
        RECT  43.056 64.716 43.08 64.8 ;
    END
  END head_record[227]
  PIN head_record[228]
    DIRECTION INPUT ;
    USE SIGNAL ;
    PORT
      LAYER M5 ;
        RECT  43.44 64.716 43.464 64.8 ;
    END
  END head_record[228]
  PIN head_record[229]
    DIRECTION INPUT ;
    USE SIGNAL ;
    PORT
      LAYER M5 ;
        RECT  43.872 64.716 43.896 64.8 ;
    END
  END head_record[229]
  PIN head_record[22]
    DIRECTION INPUT ;
    USE SIGNAL ;
    PORT
      LAYER M4 ;
        RECT  0 12.048 0.084 12.072 ;
    END
  END head_record[22]
  PIN head_record[230]
    DIRECTION INPUT ;
    USE SIGNAL ;
    PORT
      LAYER M5 ;
        RECT  44.256 64.716 44.28 64.8 ;
    END
  END head_record[230]
  PIN head_record[231]
    DIRECTION INPUT ;
    USE SIGNAL ;
    PORT
      LAYER M5 ;
        RECT  44.688 64.716 44.712 64.8 ;
    END
  END head_record[231]
  PIN head_record[232]
    DIRECTION INPUT ;
    USE SIGNAL ;
    PORT
      LAYER M5 ;
        RECT  45.072 64.716 45.096 64.8 ;
    END
  END head_record[232]
  PIN head_record[233]
    DIRECTION INPUT ;
    USE SIGNAL ;
    PORT
      LAYER M5 ;
        RECT  45.456 64.716 45.48 64.8 ;
    END
  END head_record[233]
  PIN head_record[234]
    DIRECTION INPUT ;
    USE SIGNAL ;
    PORT
      LAYER M5 ;
        RECT  45.888 64.716 45.912 64.8 ;
    END
  END head_record[234]
  PIN head_record[235]
    DIRECTION INPUT ;
    USE SIGNAL ;
    PORT
      LAYER M5 ;
        RECT  46.272 64.716 46.296 64.8 ;
    END
  END head_record[235]
  PIN head_record[236]
    DIRECTION INPUT ;
    USE SIGNAL ;
    PORT
      LAYER M5 ;
        RECT  46.656 64.716 46.68 64.8 ;
    END
  END head_record[236]
  PIN head_record[237]
    DIRECTION INPUT ;
    USE SIGNAL ;
    PORT
      LAYER M5 ;
        RECT  47.088 64.716 47.112 64.8 ;
    END
  END head_record[237]
  PIN head_record[238]
    DIRECTION INPUT ;
    USE SIGNAL ;
    PORT
      LAYER M5 ;
        RECT  47.472 64.716 47.496 64.8 ;
    END
  END head_record[238]
  PIN head_record[239]
    DIRECTION INPUT ;
    USE SIGNAL ;
    PORT
      LAYER M5 ;
        RECT  47.904 64.716 47.928 64.8 ;
    END
  END head_record[239]
  PIN head_record[23]
    DIRECTION INPUT ;
    USE SIGNAL ;
    PORT
      LAYER M4 ;
        RECT  0 12.48 0.084 12.504 ;
    END
  END head_record[23]
  PIN head_record[240]
    DIRECTION INPUT ;
    USE SIGNAL ;
    PORT
      LAYER M5 ;
        RECT  48.288 64.716 48.312 64.8 ;
    END
  END head_record[240]
  PIN head_record[241]
    DIRECTION INPUT ;
    USE SIGNAL ;
    PORT
      LAYER M5 ;
        RECT  48.672 64.716 48.696 64.8 ;
    END
  END head_record[241]
  PIN head_record[242]
    DIRECTION INPUT ;
    USE SIGNAL ;
    PORT
      LAYER M5 ;
        RECT  49.104 64.716 49.128 64.8 ;
    END
  END head_record[242]
  PIN head_record[243]
    DIRECTION INPUT ;
    USE SIGNAL ;
    PORT
      LAYER M5 ;
        RECT  49.488 64.716 49.512 64.8 ;
    END
  END head_record[243]
  PIN head_record[244]
    DIRECTION INPUT ;
    USE SIGNAL ;
    PORT
      LAYER M5 ;
        RECT  49.92 64.716 49.944 64.8 ;
    END
  END head_record[244]
  PIN head_record[245]
    DIRECTION INPUT ;
    USE SIGNAL ;
    PORT
      LAYER M5 ;
        RECT  50.304 64.716 50.328 64.8 ;
    END
  END head_record[245]
  PIN head_record[246]
    DIRECTION INPUT ;
    USE SIGNAL ;
    PORT
      LAYER M5 ;
        RECT  50.688 64.716 50.712 64.8 ;
    END
  END head_record[246]
  PIN head_record[247]
    DIRECTION INPUT ;
    USE SIGNAL ;
    PORT
      LAYER M5 ;
        RECT  51.12 64.716 51.144 64.8 ;
    END
  END head_record[247]
  PIN head_record[248]
    DIRECTION INPUT ;
    USE SIGNAL ;
    PORT
      LAYER M5 ;
        RECT  51.504 64.716 51.528 64.8 ;
    END
  END head_record[248]
  PIN head_record[249]
    DIRECTION INPUT ;
    USE SIGNAL ;
    PORT
      LAYER M5 ;
        RECT  51.936 64.716 51.96 64.8 ;
    END
  END head_record[249]
  PIN head_record[24]
    DIRECTION INPUT ;
    USE SIGNAL ;
    PORT
      LAYER M4 ;
        RECT  0 12.912 0.084 12.936 ;
    END
  END head_record[24]
  PIN head_record[250]
    DIRECTION INPUT ;
    USE SIGNAL ;
    PORT
      LAYER M5 ;
        RECT  52.32 64.716 52.344 64.8 ;
    END
  END head_record[250]
  PIN head_record[251]
    DIRECTION INPUT ;
    USE SIGNAL ;
    PORT
      LAYER M5 ;
        RECT  52.704 64.716 52.728 64.8 ;
    END
  END head_record[251]
  PIN head_record[252]
    DIRECTION INPUT ;
    USE SIGNAL ;
    PORT
      LAYER M5 ;
        RECT  53.136 64.716 53.16 64.8 ;
    END
  END head_record[252]
  PIN head_record[253]
    DIRECTION INPUT ;
    USE SIGNAL ;
    PORT
      LAYER M5 ;
        RECT  53.52 64.716 53.544 64.8 ;
    END
  END head_record[253]
  PIN head_record[254]
    DIRECTION INPUT ;
    USE SIGNAL ;
    PORT
      LAYER M5 ;
        RECT  53.904 64.716 53.928 64.8 ;
    END
  END head_record[254]
  PIN head_record[255]
    DIRECTION INPUT ;
    USE SIGNAL ;
    PORT
      LAYER M5 ;
        RECT  54.336 64.716 54.36 64.8 ;
    END
  END head_record[255]
  PIN head_record[256]
    DIRECTION INPUT ;
    USE SIGNAL ;
    PORT
      LAYER M5 ;
        RECT  54.72 64.716 54.744 64.8 ;
    END
  END head_record[256]
  PIN head_record[257]
    DIRECTION INPUT ;
    USE SIGNAL ;
    PORT
      LAYER M5 ;
        RECT  55.152 64.716 55.176 64.8 ;
    END
  END head_record[257]
  PIN head_record[258]
    DIRECTION INPUT ;
    USE SIGNAL ;
    PORT
      LAYER M5 ;
        RECT  55.536 64.716 55.56 64.8 ;
    END
  END head_record[258]
  PIN head_record[259]
    DIRECTION INPUT ;
    USE SIGNAL ;
    PORT
      LAYER M5 ;
        RECT  55.92 64.716 55.944 64.8 ;
    END
  END head_record[259]
  PIN head_record[25]
    DIRECTION INPUT ;
    USE SIGNAL ;
    PORT
      LAYER M4 ;
        RECT  0 13.344 0.084 13.368 ;
    END
  END head_record[25]
  PIN head_record[260]
    DIRECTION INPUT ;
    USE SIGNAL ;
    PORT
      LAYER M5 ;
        RECT  56.352 64.716 56.376 64.8 ;
    END
  END head_record[260]
  PIN head_record[261]
    DIRECTION INPUT ;
    USE SIGNAL ;
    PORT
      LAYER M5 ;
        RECT  56.736 64.716 56.76 64.8 ;
    END
  END head_record[261]
  PIN head_record[262]
    DIRECTION INPUT ;
    USE SIGNAL ;
    PORT
      LAYER M5 ;
        RECT  57.168 64.716 57.192 64.8 ;
    END
  END head_record[262]
  PIN head_record[263]
    DIRECTION INPUT ;
    USE SIGNAL ;
    PORT
      LAYER M5 ;
        RECT  57.552 64.716 57.576 64.8 ;
    END
  END head_record[263]
  PIN head_record[264]
    DIRECTION INPUT ;
    USE SIGNAL ;
    PORT
      LAYER M5 ;
        RECT  57.936 64.716 57.96 64.8 ;
    END
  END head_record[264]
  PIN head_record[265]
    DIRECTION INPUT ;
    USE SIGNAL ;
    PORT
      LAYER M5 ;
        RECT  58.368 64.716 58.392 64.8 ;
    END
  END head_record[265]
  PIN head_record[266]
    DIRECTION INPUT ;
    USE SIGNAL ;
    PORT
      LAYER M5 ;
        RECT  58.752 64.716 58.776 64.8 ;
    END
  END head_record[266]
  PIN head_record[267]
    DIRECTION INPUT ;
    USE SIGNAL ;
    PORT
      LAYER M5 ;
        RECT  59.136 64.716 59.16 64.8 ;
    END
  END head_record[267]
  PIN head_record[268]
    DIRECTION INPUT ;
    USE SIGNAL ;
    PORT
      LAYER M5 ;
        RECT  59.568 64.716 59.592 64.8 ;
    END
  END head_record[268]
  PIN head_record[269]
    DIRECTION INPUT ;
    USE SIGNAL ;
    PORT
      LAYER M5 ;
        RECT  59.952 64.716 59.976 64.8 ;
    END
  END head_record[269]
  PIN head_record[26]
    DIRECTION INPUT ;
    USE SIGNAL ;
    PORT
      LAYER M4 ;
        RECT  0 13.776 0.084 13.8 ;
    END
  END head_record[26]
  PIN head_record[270]
    DIRECTION INPUT ;
    USE SIGNAL ;
    PORT
      LAYER M5 ;
        RECT  60.384 64.716 60.408 64.8 ;
    END
  END head_record[270]
  PIN head_record[271]
    DIRECTION INPUT ;
    USE SIGNAL ;
    PORT
      LAYER M5 ;
        RECT  60.768 64.716 60.792 64.8 ;
    END
  END head_record[271]
  PIN head_record[272]
    DIRECTION INPUT ;
    USE SIGNAL ;
    PORT
      LAYER M5 ;
        RECT  61.152 64.716 61.176 64.8 ;
    END
  END head_record[272]
  PIN head_record[273]
    DIRECTION INPUT ;
    USE SIGNAL ;
    PORT
      LAYER M5 ;
        RECT  61.584 64.716 61.608 64.8 ;
    END
  END head_record[273]
  PIN head_record[274]
    DIRECTION INPUT ;
    USE SIGNAL ;
    PORT
      LAYER M5 ;
        RECT  61.968 64.716 61.992 64.8 ;
    END
  END head_record[274]
  PIN head_record[275]
    DIRECTION INPUT ;
    USE SIGNAL ;
    PORT
      LAYER M5 ;
        RECT  62.4 64.716 62.424 64.8 ;
    END
  END head_record[275]
  PIN head_record[276]
    DIRECTION INPUT ;
    USE SIGNAL ;
    PORT
      LAYER M5 ;
        RECT  2.4 0 2.424 0.084 ;
    END
  END head_record[276]
  PIN head_record[277]
    DIRECTION INPUT ;
    USE SIGNAL ;
    PORT
      LAYER M5 ;
        RECT  2.832 0 2.856 0.084 ;
    END
  END head_record[277]
  PIN head_record[278]
    DIRECTION INPUT ;
    USE SIGNAL ;
    PORT
      LAYER M5 ;
        RECT  3.312 0 3.336 0.084 ;
    END
  END head_record[278]
  PIN head_record[279]
    DIRECTION INPUT ;
    USE SIGNAL ;
    PORT
      LAYER M5 ;
        RECT  3.744 0 3.768 0.084 ;
    END
  END head_record[279]
  PIN head_record[27]
    DIRECTION INPUT ;
    USE SIGNAL ;
    PORT
      LAYER M4 ;
        RECT  0 14.208 0.084 14.232 ;
    END
  END head_record[27]
  PIN head_record[280]
    DIRECTION INPUT ;
    USE SIGNAL ;
    PORT
      LAYER M5 ;
        RECT  4.176 0 4.2 0.084 ;
    END
  END head_record[280]
  PIN head_record[281]
    DIRECTION INPUT ;
    USE SIGNAL ;
    PORT
      LAYER M5 ;
        RECT  4.608 0 4.632 0.084 ;
    END
  END head_record[281]
  PIN head_record[282]
    DIRECTION INPUT ;
    USE SIGNAL ;
    PORT
      LAYER M5 ;
        RECT  5.04 0 5.064 0.084 ;
    END
  END head_record[282]
  PIN head_record[283]
    DIRECTION INPUT ;
    USE SIGNAL ;
    PORT
      LAYER M5 ;
        RECT  5.472 0 5.496 0.084 ;
    END
  END head_record[283]
  PIN head_record[284]
    DIRECTION INPUT ;
    USE SIGNAL ;
    PORT
      LAYER M5 ;
        RECT  5.904 0 5.928 0.084 ;
    END
  END head_record[284]
  PIN head_record[285]
    DIRECTION INPUT ;
    USE SIGNAL ;
    PORT
      LAYER M5 ;
        RECT  6.336 0 6.36 0.084 ;
    END
  END head_record[285]
  PIN head_record[286]
    DIRECTION INPUT ;
    USE SIGNAL ;
    PORT
      LAYER M5 ;
        RECT  6.768 0 6.792 0.084 ;
    END
  END head_record[286]
  PIN head_record[287]
    DIRECTION INPUT ;
    USE SIGNAL ;
    PORT
      LAYER M5 ;
        RECT  7.248 0 7.272 0.084 ;
    END
  END head_record[287]
  PIN head_record[288]
    DIRECTION INPUT ;
    USE SIGNAL ;
    PORT
      LAYER M5 ;
        RECT  7.68 0 7.704 0.084 ;
    END
  END head_record[288]
  PIN head_record[289]
    DIRECTION INPUT ;
    USE SIGNAL ;
    PORT
      LAYER M5 ;
        RECT  8.112 0 8.136 0.084 ;
    END
  END head_record[289]
  PIN head_record[28]
    DIRECTION INPUT ;
    USE SIGNAL ;
    PORT
      LAYER M4 ;
        RECT  0 14.688 0.084 14.712 ;
    END
  END head_record[28]
  PIN head_record[290]
    DIRECTION INPUT ;
    USE SIGNAL ;
    PORT
      LAYER M5 ;
        RECT  8.544 0 8.568 0.084 ;
    END
  END head_record[290]
  PIN head_record[291]
    DIRECTION INPUT ;
    USE SIGNAL ;
    PORT
      LAYER M5 ;
        RECT  8.976 0 9 0.084 ;
    END
  END head_record[291]
  PIN head_record[292]
    DIRECTION INPUT ;
    USE SIGNAL ;
    PORT
      LAYER M5 ;
        RECT  9.408 0 9.432 0.084 ;
    END
  END head_record[292]
  PIN head_record[293]
    DIRECTION INPUT ;
    USE SIGNAL ;
    PORT
      LAYER M5 ;
        RECT  9.84 0 9.864 0.084 ;
    END
  END head_record[293]
  PIN head_record[294]
    DIRECTION INPUT ;
    USE SIGNAL ;
    PORT
      LAYER M5 ;
        RECT  10.272 0 10.296 0.084 ;
    END
  END head_record[294]
  PIN head_record[295]
    DIRECTION INPUT ;
    USE SIGNAL ;
    PORT
      LAYER M5 ;
        RECT  10.752 0 10.776 0.084 ;
    END
  END head_record[295]
  PIN head_record[296]
    DIRECTION INPUT ;
    USE SIGNAL ;
    PORT
      LAYER M5 ;
        RECT  11.184 0 11.208 0.084 ;
    END
  END head_record[296]
  PIN head_record[297]
    DIRECTION INPUT ;
    USE SIGNAL ;
    PORT
      LAYER M5 ;
        RECT  11.616 0 11.64 0.084 ;
    END
  END head_record[297]
  PIN head_record[298]
    DIRECTION INPUT ;
    USE SIGNAL ;
    PORT
      LAYER M5 ;
        RECT  12.048 0 12.072 0.084 ;
    END
  END head_record[298]
  PIN head_record[299]
    DIRECTION INPUT ;
    USE SIGNAL ;
    PORT
      LAYER M5 ;
        RECT  12.48 0 12.504 0.084 ;
    END
  END head_record[299]
  PIN head_record[29]
    DIRECTION INPUT ;
    USE SIGNAL ;
    PORT
      LAYER M4 ;
        RECT  0 15.12 0.084 15.144 ;
    END
  END head_record[29]
  PIN head_record[2]
    DIRECTION INPUT ;
    USE SIGNAL ;
    PORT
      LAYER M4 ;
        RECT  0 3.312 0.084 3.336 ;
    END
  END head_record[2]
  PIN head_record[300]
    DIRECTION INPUT ;
    USE SIGNAL ;
    PORT
      LAYER M5 ;
        RECT  12.912 0 12.936 0.084 ;
    END
  END head_record[300]
  PIN head_record[301]
    DIRECTION INPUT ;
    USE SIGNAL ;
    PORT
      LAYER M5 ;
        RECT  13.344 0 13.368 0.084 ;
    END
  END head_record[301]
  PIN head_record[302]
    DIRECTION INPUT ;
    USE SIGNAL ;
    PORT
      LAYER M5 ;
        RECT  13.776 0 13.8 0.084 ;
    END
  END head_record[302]
  PIN head_record[303]
    DIRECTION INPUT ;
    USE SIGNAL ;
    PORT
      LAYER M5 ;
        RECT  14.208 0 14.232 0.084 ;
    END
  END head_record[303]
  PIN head_record[304]
    DIRECTION INPUT ;
    USE SIGNAL ;
    PORT
      LAYER M5 ;
        RECT  14.688 0 14.712 0.084 ;
    END
  END head_record[304]
  PIN head_record[305]
    DIRECTION INPUT ;
    USE SIGNAL ;
    PORT
      LAYER M5 ;
        RECT  15.12 0 15.144 0.084 ;
    END
  END head_record[305]
  PIN head_record[306]
    DIRECTION INPUT ;
    USE SIGNAL ;
    PORT
      LAYER M5 ;
        RECT  15.552 0 15.576 0.084 ;
    END
  END head_record[306]
  PIN head_record[307]
    DIRECTION INPUT ;
    USE SIGNAL ;
    PORT
      LAYER M5 ;
        RECT  15.984 0 16.008 0.084 ;
    END
  END head_record[307]
  PIN head_record[308]
    DIRECTION INPUT ;
    USE SIGNAL ;
    PORT
      LAYER M5 ;
        RECT  16.416 0 16.44 0.084 ;
    END
  END head_record[308]
  PIN head_record[309]
    DIRECTION INPUT ;
    USE SIGNAL ;
    PORT
      LAYER M5 ;
        RECT  16.848 0 16.872 0.084 ;
    END
  END head_record[309]
  PIN head_record[30]
    DIRECTION INPUT ;
    USE SIGNAL ;
    PORT
      LAYER M4 ;
        RECT  0 15.552 0.084 15.576 ;
    END
  END head_record[30]
  PIN head_record[310]
    DIRECTION INPUT ;
    USE SIGNAL ;
    PORT
      LAYER M5 ;
        RECT  17.28 0 17.304 0.084 ;
    END
  END head_record[310]
  PIN head_record[311]
    DIRECTION INPUT ;
    USE SIGNAL ;
    PORT
      LAYER M5 ;
        RECT  17.712 0 17.736 0.084 ;
    END
  END head_record[311]
  PIN head_record[312]
    DIRECTION INPUT ;
    USE SIGNAL ;
    PORT
      LAYER M5 ;
        RECT  18.144 0 18.168 0.084 ;
    END
  END head_record[312]
  PIN head_record[313]
    DIRECTION INPUT ;
    USE SIGNAL ;
    PORT
      LAYER M5 ;
        RECT  18.624 0 18.648 0.084 ;
    END
  END head_record[313]
  PIN head_record[314]
    DIRECTION INPUT ;
    USE SIGNAL ;
    PORT
      LAYER M5 ;
        RECT  19.056 0 19.08 0.084 ;
    END
  END head_record[314]
  PIN head_record[315]
    DIRECTION INPUT ;
    USE SIGNAL ;
    PORT
      LAYER M5 ;
        RECT  19.488 0 19.512 0.084 ;
    END
  END head_record[315]
  PIN head_record[316]
    DIRECTION INPUT ;
    USE SIGNAL ;
    PORT
      LAYER M5 ;
        RECT  19.92 0 19.944 0.084 ;
    END
  END head_record[316]
  PIN head_record[317]
    DIRECTION INPUT ;
    USE SIGNAL ;
    PORT
      LAYER M5 ;
        RECT  20.352 0 20.376 0.084 ;
    END
  END head_record[317]
  PIN head_record[318]
    DIRECTION INPUT ;
    USE SIGNAL ;
    PORT
      LAYER M5 ;
        RECT  20.784 0 20.808 0.084 ;
    END
  END head_record[318]
  PIN head_record[319]
    DIRECTION INPUT ;
    USE SIGNAL ;
    PORT
      LAYER M5 ;
        RECT  21.216 0 21.24 0.084 ;
    END
  END head_record[319]
  PIN head_record[31]
    DIRECTION INPUT ;
    USE SIGNAL ;
    PORT
      LAYER M4 ;
        RECT  0 15.984 0.084 16.008 ;
    END
  END head_record[31]
  PIN head_record[320]
    DIRECTION INPUT ;
    USE SIGNAL ;
    PORT
      LAYER M5 ;
        RECT  21.648 0 21.672 0.084 ;
    END
  END head_record[320]
  PIN head_record[321]
    DIRECTION INPUT ;
    USE SIGNAL ;
    PORT
      LAYER M5 ;
        RECT  22.128 0 22.152 0.084 ;
    END
  END head_record[321]
  PIN head_record[322]
    DIRECTION INPUT ;
    USE SIGNAL ;
    PORT
      LAYER M5 ;
        RECT  22.56 0 22.584 0.084 ;
    END
  END head_record[322]
  PIN head_record[323]
    DIRECTION INPUT ;
    USE SIGNAL ;
    PORT
      LAYER M5 ;
        RECT  22.992 0 23.016 0.084 ;
    END
  END head_record[323]
  PIN head_record[324]
    DIRECTION INPUT ;
    USE SIGNAL ;
    PORT
      LAYER M5 ;
        RECT  23.424 0 23.448 0.084 ;
    END
  END head_record[324]
  PIN head_record[325]
    DIRECTION INPUT ;
    USE SIGNAL ;
    PORT
      LAYER M5 ;
        RECT  23.856 0 23.88 0.084 ;
    END
  END head_record[325]
  PIN head_record[326]
    DIRECTION INPUT ;
    USE SIGNAL ;
    PORT
      LAYER M5 ;
        RECT  24.288 0 24.312 0.084 ;
    END
  END head_record[326]
  PIN head_record[327]
    DIRECTION INPUT ;
    USE SIGNAL ;
    PORT
      LAYER M5 ;
        RECT  24.72 0 24.744 0.084 ;
    END
  END head_record[327]
  PIN head_record[328]
    DIRECTION INPUT ;
    USE SIGNAL ;
    PORT
      LAYER M5 ;
        RECT  25.152 0 25.176 0.084 ;
    END
  END head_record[328]
  PIN head_record[329]
    DIRECTION INPUT ;
    USE SIGNAL ;
    PORT
      LAYER M5 ;
        RECT  25.584 0 25.608 0.084 ;
    END
  END head_record[329]
  PIN head_record[32]
    DIRECTION INPUT ;
    USE SIGNAL ;
    PORT
      LAYER M4 ;
        RECT  0 16.416 0.084 16.44 ;
    END
  END head_record[32]
  PIN head_record[330]
    DIRECTION INPUT ;
    USE SIGNAL ;
    PORT
      LAYER M5 ;
        RECT  26.064 0 26.088 0.084 ;
    END
  END head_record[330]
  PIN head_record[331]
    DIRECTION INPUT ;
    USE SIGNAL ;
    PORT
      LAYER M5 ;
        RECT  26.496 0 26.52 0.084 ;
    END
  END head_record[331]
  PIN head_record[332]
    DIRECTION INPUT ;
    USE SIGNAL ;
    PORT
      LAYER M5 ;
        RECT  26.928 0 26.952 0.084 ;
    END
  END head_record[332]
  PIN head_record[333]
    DIRECTION INPUT ;
    USE SIGNAL ;
    PORT
      LAYER M5 ;
        RECT  27.36 0 27.384 0.084 ;
    END
  END head_record[333]
  PIN head_record[334]
    DIRECTION INPUT ;
    USE SIGNAL ;
    PORT
      LAYER M5 ;
        RECT  27.792 0 27.816 0.084 ;
    END
  END head_record[334]
  PIN head_record[335]
    DIRECTION INPUT ;
    USE SIGNAL ;
    PORT
      LAYER M5 ;
        RECT  28.224 0 28.248 0.084 ;
    END
  END head_record[335]
  PIN head_record[336]
    DIRECTION INPUT ;
    USE SIGNAL ;
    PORT
      LAYER M5 ;
        RECT  28.656 0 28.68 0.084 ;
    END
  END head_record[336]
  PIN head_record[337]
    DIRECTION INPUT ;
    USE SIGNAL ;
    PORT
      LAYER M5 ;
        RECT  29.088 0 29.112 0.084 ;
    END
  END head_record[337]
  PIN head_record[338]
    DIRECTION INPUT ;
    USE SIGNAL ;
    PORT
      LAYER M5 ;
        RECT  29.52 0 29.544 0.084 ;
    END
  END head_record[338]
  PIN head_record[339]
    DIRECTION INPUT ;
    USE SIGNAL ;
    PORT
      LAYER M5 ;
        RECT  30 0 30.024 0.084 ;
    END
  END head_record[339]
  PIN head_record[33]
    DIRECTION INPUT ;
    USE SIGNAL ;
    PORT
      LAYER M4 ;
        RECT  0 16.848 0.084 16.872 ;
    END
  END head_record[33]
  PIN head_record[340]
    DIRECTION INPUT ;
    USE SIGNAL ;
    PORT
      LAYER M5 ;
        RECT  30.432 0 30.456 0.084 ;
    END
  END head_record[340]
  PIN head_record[341]
    DIRECTION INPUT ;
    USE SIGNAL ;
    PORT
      LAYER M5 ;
        RECT  30.864 0 30.888 0.084 ;
    END
  END head_record[341]
  PIN head_record[342]
    DIRECTION INPUT ;
    USE SIGNAL ;
    PORT
      LAYER M5 ;
        RECT  31.296 0 31.32 0.084 ;
    END
  END head_record[342]
  PIN head_record[343]
    DIRECTION INPUT ;
    USE SIGNAL ;
    PORT
      LAYER M5 ;
        RECT  31.728 0 31.752 0.084 ;
    END
  END head_record[343]
  PIN head_record[344]
    DIRECTION INPUT ;
    USE SIGNAL ;
    PORT
      LAYER M5 ;
        RECT  32.16 0 32.184 0.084 ;
    END
  END head_record[344]
  PIN head_record[345]
    DIRECTION INPUT ;
    USE SIGNAL ;
    PORT
      LAYER M5 ;
        RECT  32.592 0 32.616 0.084 ;
    END
  END head_record[345]
  PIN head_record[346]
    DIRECTION INPUT ;
    USE SIGNAL ;
    PORT
      LAYER M5 ;
        RECT  33.024 0 33.048 0.084 ;
    END
  END head_record[346]
  PIN head_record[347]
    DIRECTION INPUT ;
    USE SIGNAL ;
    PORT
      LAYER M5 ;
        RECT  33.504 0 33.528 0.084 ;
    END
  END head_record[347]
  PIN head_record[348]
    DIRECTION INPUT ;
    USE SIGNAL ;
    PORT
      LAYER M5 ;
        RECT  33.936 0 33.96 0.084 ;
    END
  END head_record[348]
  PIN head_record[349]
    DIRECTION INPUT ;
    USE SIGNAL ;
    PORT
      LAYER M5 ;
        RECT  34.368 0 34.392 0.084 ;
    END
  END head_record[349]
  PIN head_record[34]
    DIRECTION INPUT ;
    USE SIGNAL ;
    PORT
      LAYER M4 ;
        RECT  0 17.28 0.084 17.304 ;
    END
  END head_record[34]
  PIN head_record[350]
    DIRECTION INPUT ;
    USE SIGNAL ;
    PORT
      LAYER M5 ;
        RECT  34.8 0 34.824 0.084 ;
    END
  END head_record[350]
  PIN head_record[351]
    DIRECTION INPUT ;
    USE SIGNAL ;
    PORT
      LAYER M5 ;
        RECT  35.232 0 35.256 0.084 ;
    END
  END head_record[351]
  PIN head_record[352]
    DIRECTION INPUT ;
    USE SIGNAL ;
    PORT
      LAYER M5 ;
        RECT  35.664 0 35.688 0.084 ;
    END
  END head_record[352]
  PIN head_record[353]
    DIRECTION INPUT ;
    USE SIGNAL ;
    PORT
      LAYER M5 ;
        RECT  36.096 0 36.12 0.084 ;
    END
  END head_record[353]
  PIN head_record[354]
    DIRECTION INPUT ;
    USE SIGNAL ;
    PORT
      LAYER M5 ;
        RECT  36.528 0 36.552 0.084 ;
    END
  END head_record[354]
  PIN head_record[355]
    DIRECTION INPUT ;
    USE SIGNAL ;
    PORT
      LAYER M5 ;
        RECT  36.96 0 36.984 0.084 ;
    END
  END head_record[355]
  PIN head_record[356]
    DIRECTION INPUT ;
    USE SIGNAL ;
    PORT
      LAYER M5 ;
        RECT  37.44 0 37.464 0.084 ;
    END
  END head_record[356]
  PIN head_record[357]
    DIRECTION INPUT ;
    USE SIGNAL ;
    PORT
      LAYER M5 ;
        RECT  37.872 0 37.896 0.084 ;
    END
  END head_record[357]
  PIN head_record[358]
    DIRECTION INPUT ;
    USE SIGNAL ;
    PORT
      LAYER M5 ;
        RECT  38.304 0 38.328 0.084 ;
    END
  END head_record[358]
  PIN head_record[359]
    DIRECTION INPUT ;
    USE SIGNAL ;
    PORT
      LAYER M5 ;
        RECT  38.736 0 38.76 0.084 ;
    END
  END head_record[359]
  PIN head_record[35]
    DIRECTION INPUT ;
    USE SIGNAL ;
    PORT
      LAYER M4 ;
        RECT  0 17.712 0.084 17.736 ;
    END
  END head_record[35]
  PIN head_record[360]
    DIRECTION INPUT ;
    USE SIGNAL ;
    PORT
      LAYER M5 ;
        RECT  39.168 0 39.192 0.084 ;
    END
  END head_record[360]
  PIN head_record[361]
    DIRECTION INPUT ;
    USE SIGNAL ;
    PORT
      LAYER M5 ;
        RECT  39.6 0 39.624 0.084 ;
    END
  END head_record[361]
  PIN head_record[362]
    DIRECTION INPUT ;
    USE SIGNAL ;
    PORT
      LAYER M5 ;
        RECT  40.032 0 40.056 0.084 ;
    END
  END head_record[362]
  PIN head_record[363]
    DIRECTION INPUT ;
    USE SIGNAL ;
    PORT
      LAYER M5 ;
        RECT  40.464 0 40.488 0.084 ;
    END
  END head_record[363]
  PIN head_record[364]
    DIRECTION INPUT ;
    USE SIGNAL ;
    PORT
      LAYER M5 ;
        RECT  40.944 0 40.968 0.084 ;
    END
  END head_record[364]
  PIN head_record[365]
    DIRECTION INPUT ;
    USE SIGNAL ;
    PORT
      LAYER M5 ;
        RECT  41.376 0 41.4 0.084 ;
    END
  END head_record[365]
  PIN head_record[366]
    DIRECTION INPUT ;
    USE SIGNAL ;
    PORT
      LAYER M5 ;
        RECT  41.808 0 41.832 0.084 ;
    END
  END head_record[366]
  PIN head_record[367]
    DIRECTION INPUT ;
    USE SIGNAL ;
    PORT
      LAYER M5 ;
        RECT  42.24 0 42.264 0.084 ;
    END
  END head_record[367]
  PIN head_record[368]
    DIRECTION INPUT ;
    USE SIGNAL ;
    PORT
      LAYER M5 ;
        RECT  42.672 0 42.696 0.084 ;
    END
  END head_record[368]
  PIN head_record[369]
    DIRECTION INPUT ;
    USE SIGNAL ;
    PORT
      LAYER M5 ;
        RECT  43.104 0 43.128 0.084 ;
    END
  END head_record[369]
  PIN head_record[36]
    DIRECTION INPUT ;
    USE SIGNAL ;
    PORT
      LAYER M4 ;
        RECT  0 18.144 0.084 18.168 ;
    END
  END head_record[36]
  PIN head_record[370]
    DIRECTION INPUT ;
    USE SIGNAL ;
    PORT
      LAYER M5 ;
        RECT  43.536 0 43.56 0.084 ;
    END
  END head_record[370]
  PIN head_record[371]
    DIRECTION INPUT ;
    USE SIGNAL ;
    PORT
      LAYER M5 ;
        RECT  43.968 0 43.992 0.084 ;
    END
  END head_record[371]
  PIN head_record[372]
    DIRECTION INPUT ;
    USE SIGNAL ;
    PORT
      LAYER M5 ;
        RECT  44.4 0 44.424 0.084 ;
    END
  END head_record[372]
  PIN head_record[373]
    DIRECTION INPUT ;
    USE SIGNAL ;
    PORT
      LAYER M5 ;
        RECT  44.88 0 44.904 0.084 ;
    END
  END head_record[373]
  PIN head_record[374]
    DIRECTION INPUT ;
    USE SIGNAL ;
    PORT
      LAYER M5 ;
        RECT  45.312 0 45.336 0.084 ;
    END
  END head_record[374]
  PIN head_record[375]
    DIRECTION INPUT ;
    USE SIGNAL ;
    PORT
      LAYER M5 ;
        RECT  45.744 0 45.768 0.084 ;
    END
  END head_record[375]
  PIN head_record[376]
    DIRECTION INPUT ;
    USE SIGNAL ;
    PORT
      LAYER M5 ;
        RECT  46.176 0 46.2 0.084 ;
    END
  END head_record[376]
  PIN head_record[377]
    DIRECTION INPUT ;
    USE SIGNAL ;
    PORT
      LAYER M5 ;
        RECT  46.608 0 46.632 0.084 ;
    END
  END head_record[377]
  PIN head_record[378]
    DIRECTION INPUT ;
    USE SIGNAL ;
    PORT
      LAYER M5 ;
        RECT  47.04 0 47.064 0.084 ;
    END
  END head_record[378]
  PIN head_record[379]
    DIRECTION INPUT ;
    USE SIGNAL ;
    PORT
      LAYER M5 ;
        RECT  47.472 0 47.496 0.084 ;
    END
  END head_record[379]
  PIN head_record[37]
    DIRECTION INPUT ;
    USE SIGNAL ;
    PORT
      LAYER M4 ;
        RECT  0 18.624 0.084 18.648 ;
    END
  END head_record[37]
  PIN head_record[380]
    DIRECTION INPUT ;
    USE SIGNAL ;
    PORT
      LAYER M5 ;
        RECT  47.904 0 47.928 0.084 ;
    END
  END head_record[380]
  PIN head_record[381]
    DIRECTION INPUT ;
    USE SIGNAL ;
    PORT
      LAYER M5 ;
        RECT  48.336 0 48.36 0.084 ;
    END
  END head_record[381]
  PIN head_record[382]
    DIRECTION INPUT ;
    USE SIGNAL ;
    PORT
      LAYER M5 ;
        RECT  48.816 0 48.84 0.084 ;
    END
  END head_record[382]
  PIN head_record[383]
    DIRECTION INPUT ;
    USE SIGNAL ;
    PORT
      LAYER M5 ;
        RECT  49.248 0 49.272 0.084 ;
    END
  END head_record[383]
  PIN head_record[384]
    DIRECTION INPUT ;
    USE SIGNAL ;
    PORT
      LAYER M5 ;
        RECT  49.68 0 49.704 0.084 ;
    END
  END head_record[384]
  PIN head_record[385]
    DIRECTION INPUT ;
    USE SIGNAL ;
    PORT
      LAYER M5 ;
        RECT  50.112 0 50.136 0.084 ;
    END
  END head_record[385]
  PIN head_record[386]
    DIRECTION INPUT ;
    USE SIGNAL ;
    PORT
      LAYER M5 ;
        RECT  50.544 0 50.568 0.084 ;
    END
  END head_record[386]
  PIN head_record[387]
    DIRECTION INPUT ;
    USE SIGNAL ;
    PORT
      LAYER M5 ;
        RECT  50.976 0 51 0.084 ;
    END
  END head_record[387]
  PIN head_record[388]
    DIRECTION INPUT ;
    USE SIGNAL ;
    PORT
      LAYER M5 ;
        RECT  51.408 0 51.432 0.084 ;
    END
  END head_record[388]
  PIN head_record[389]
    DIRECTION INPUT ;
    USE SIGNAL ;
    PORT
      LAYER M5 ;
        RECT  51.84 0 51.864 0.084 ;
    END
  END head_record[389]
  PIN head_record[38]
    DIRECTION INPUT ;
    USE SIGNAL ;
    PORT
      LAYER M4 ;
        RECT  0 19.056 0.084 19.08 ;
    END
  END head_record[38]
  PIN head_record[390]
    DIRECTION INPUT ;
    USE SIGNAL ;
    PORT
      LAYER M5 ;
        RECT  52.32 0 52.344 0.084 ;
    END
  END head_record[390]
  PIN head_record[391]
    DIRECTION INPUT ;
    USE SIGNAL ;
    PORT
      LAYER M5 ;
        RECT  52.752 0 52.776 0.084 ;
    END
  END head_record[391]
  PIN head_record[392]
    DIRECTION INPUT ;
    USE SIGNAL ;
    PORT
      LAYER M5 ;
        RECT  53.184 0 53.208 0.084 ;
    END
  END head_record[392]
  PIN head_record[393]
    DIRECTION INPUT ;
    USE SIGNAL ;
    PORT
      LAYER M5 ;
        RECT  53.616 0 53.64 0.084 ;
    END
  END head_record[393]
  PIN head_record[394]
    DIRECTION INPUT ;
    USE SIGNAL ;
    PORT
      LAYER M5 ;
        RECT  54.048 0 54.072 0.084 ;
    END
  END head_record[394]
  PIN head_record[395]
    DIRECTION INPUT ;
    USE SIGNAL ;
    PORT
      LAYER M5 ;
        RECT  54.48 0 54.504 0.084 ;
    END
  END head_record[395]
  PIN head_record[396]
    DIRECTION INPUT ;
    USE SIGNAL ;
    PORT
      LAYER M5 ;
        RECT  54.912 0 54.936 0.084 ;
    END
  END head_record[396]
  PIN head_record[397]
    DIRECTION INPUT ;
    USE SIGNAL ;
    PORT
      LAYER M5 ;
        RECT  55.344 0 55.368 0.084 ;
    END
  END head_record[397]
  PIN head_record[398]
    DIRECTION INPUT ;
    USE SIGNAL ;
    PORT
      LAYER M5 ;
        RECT  55.776 0 55.8 0.084 ;
    END
  END head_record[398]
  PIN head_record[399]
    DIRECTION INPUT ;
    USE SIGNAL ;
    PORT
      LAYER M5 ;
        RECT  56.256 0 56.28 0.084 ;
    END
  END head_record[399]
  PIN head_record[39]
    DIRECTION INPUT ;
    USE SIGNAL ;
    PORT
      LAYER M4 ;
        RECT  0 19.488 0.084 19.512 ;
    END
  END head_record[39]
  PIN head_record[3]
    DIRECTION INPUT ;
    USE SIGNAL ;
    PORT
      LAYER M4 ;
        RECT  0 3.744 0.084 3.768 ;
    END
  END head_record[3]
  PIN head_record[400]
    DIRECTION INPUT ;
    USE SIGNAL ;
    PORT
      LAYER M5 ;
        RECT  56.688 0 56.712 0.084 ;
    END
  END head_record[400]
  PIN head_record[401]
    DIRECTION INPUT ;
    USE SIGNAL ;
    PORT
      LAYER M5 ;
        RECT  57.12 0 57.144 0.084 ;
    END
  END head_record[401]
  PIN head_record[402]
    DIRECTION INPUT ;
    USE SIGNAL ;
    PORT
      LAYER M5 ;
        RECT  57.552 0 57.576 0.084 ;
    END
  END head_record[402]
  PIN head_record[403]
    DIRECTION INPUT ;
    USE SIGNAL ;
    PORT
      LAYER M5 ;
        RECT  57.984 0 58.008 0.084 ;
    END
  END head_record[403]
  PIN head_record[404]
    DIRECTION INPUT ;
    USE SIGNAL ;
    PORT
      LAYER M5 ;
        RECT  58.416 0 58.44 0.084 ;
    END
  END head_record[404]
  PIN head_record[405]
    DIRECTION INPUT ;
    USE SIGNAL ;
    PORT
      LAYER M5 ;
        RECT  58.848 0 58.872 0.084 ;
    END
  END head_record[405]
  PIN head_record[406]
    DIRECTION INPUT ;
    USE SIGNAL ;
    PORT
      LAYER M5 ;
        RECT  59.28 0 59.304 0.084 ;
    END
  END head_record[406]
  PIN head_record[407]
    DIRECTION INPUT ;
    USE SIGNAL ;
    PORT
      LAYER M5 ;
        RECT  59.712 0 59.736 0.084 ;
    END
  END head_record[407]
  PIN head_record[408]
    DIRECTION INPUT ;
    USE SIGNAL ;
    PORT
      LAYER M5 ;
        RECT  60.192 0 60.216 0.084 ;
    END
  END head_record[408]
  PIN head_record[409]
    DIRECTION INPUT ;
    USE SIGNAL ;
    PORT
      LAYER M5 ;
        RECT  60.624 0 60.648 0.084 ;
    END
  END head_record[409]
  PIN head_record[40]
    DIRECTION INPUT ;
    USE SIGNAL ;
    PORT
      LAYER M4 ;
        RECT  0 19.92 0.084 19.944 ;
    END
  END head_record[40]
  PIN head_record[410]
    DIRECTION INPUT ;
    USE SIGNAL ;
    PORT
      LAYER M5 ;
        RECT  61.056 0 61.08 0.084 ;
    END
  END head_record[410]
  PIN head_record[411]
    DIRECTION INPUT ;
    USE SIGNAL ;
    PORT
      LAYER M5 ;
        RECT  61.488 0 61.512 0.084 ;
    END
  END head_record[411]
  PIN head_record[412]
    DIRECTION INPUT ;
    USE SIGNAL ;
    PORT
      LAYER M5 ;
        RECT  61.92 0 61.944 0.084 ;
    END
  END head_record[412]
  PIN head_record[413]
    DIRECTION INPUT ;
    USE SIGNAL ;
    PORT
      LAYER M5 ;
        RECT  62.352 0 62.376 0.084 ;
    END
  END head_record[413]
  PIN head_record[414]
    DIRECTION INPUT ;
    USE SIGNAL ;
    PORT
      LAYER M4 ;
        RECT  64.716 2.352 64.8 2.376 ;
    END
  END head_record[414]
  PIN head_record[415]
    DIRECTION INPUT ;
    USE SIGNAL ;
    PORT
      LAYER M4 ;
        RECT  64.716 2.64 64.8 2.664 ;
    END
  END head_record[415]
  PIN head_record[416]
    DIRECTION INPUT ;
    USE SIGNAL ;
    PORT
      LAYER M4 ;
        RECT  64.716 2.928 64.8 2.952 ;
    END
  END head_record[416]
  PIN head_record[417]
    DIRECTION INPUT ;
    USE SIGNAL ;
    PORT
      LAYER M4 ;
        RECT  64.716 3.264 64.8 3.288 ;
    END
  END head_record[417]
  PIN head_record[418]
    DIRECTION INPUT ;
    USE SIGNAL ;
    PORT
      LAYER M4 ;
        RECT  64.716 3.552 64.8 3.576 ;
    END
  END head_record[418]
  PIN head_record[419]
    DIRECTION INPUT ;
    USE SIGNAL ;
    PORT
      LAYER M4 ;
        RECT  64.716 3.84 64.8 3.864 ;
    END
  END head_record[419]
  PIN head_record[41]
    DIRECTION INPUT ;
    USE SIGNAL ;
    PORT
      LAYER M4 ;
        RECT  0 20.352 0.084 20.376 ;
    END
  END head_record[41]
  PIN head_record[420]
    DIRECTION INPUT ;
    USE SIGNAL ;
    PORT
      LAYER M4 ;
        RECT  64.716 4.176 64.8 4.2 ;
    END
  END head_record[420]
  PIN head_record[421]
    DIRECTION INPUT ;
    USE SIGNAL ;
    PORT
      LAYER M4 ;
        RECT  64.716 4.464 64.8 4.488 ;
    END
  END head_record[421]
  PIN head_record[422]
    DIRECTION INPUT ;
    USE SIGNAL ;
    PORT
      LAYER M4 ;
        RECT  64.716 4.752 64.8 4.776 ;
    END
  END head_record[422]
  PIN head_record[423]
    DIRECTION INPUT ;
    USE SIGNAL ;
    PORT
      LAYER M4 ;
        RECT  64.716 5.088 64.8 5.112 ;
    END
  END head_record[423]
  PIN head_record[424]
    DIRECTION INPUT ;
    USE SIGNAL ;
    PORT
      LAYER M4 ;
        RECT  64.716 5.376 64.8 5.4 ;
    END
  END head_record[424]
  PIN head_record[425]
    DIRECTION INPUT ;
    USE SIGNAL ;
    PORT
      LAYER M4 ;
        RECT  64.716 5.664 64.8 5.688 ;
    END
  END head_record[425]
  PIN head_record[426]
    DIRECTION INPUT ;
    USE SIGNAL ;
    PORT
      LAYER M4 ;
        RECT  64.716 5.952 64.8 5.976 ;
    END
  END head_record[426]
  PIN head_record[427]
    DIRECTION INPUT ;
    USE SIGNAL ;
    PORT
      LAYER M4 ;
        RECT  64.716 6.288 64.8 6.312 ;
    END
  END head_record[427]
  PIN head_record[428]
    DIRECTION INPUT ;
    USE SIGNAL ;
    PORT
      LAYER M4 ;
        RECT  64.716 6.576 64.8 6.6 ;
    END
  END head_record[428]
  PIN head_record[429]
    DIRECTION INPUT ;
    USE SIGNAL ;
    PORT
      LAYER M4 ;
        RECT  64.716 6.864 64.8 6.888 ;
    END
  END head_record[429]
  PIN head_record[42]
    DIRECTION INPUT ;
    USE SIGNAL ;
    PORT
      LAYER M4 ;
        RECT  0 20.784 0.084 20.808 ;
    END
  END head_record[42]
  PIN head_record[430]
    DIRECTION INPUT ;
    USE SIGNAL ;
    PORT
      LAYER M4 ;
        RECT  64.716 7.2 64.8 7.224 ;
    END
  END head_record[430]
  PIN head_record[431]
    DIRECTION INPUT ;
    USE SIGNAL ;
    PORT
      LAYER M4 ;
        RECT  64.716 7.488 64.8 7.512 ;
    END
  END head_record[431]
  PIN head_record[432]
    DIRECTION INPUT ;
    USE SIGNAL ;
    PORT
      LAYER M4 ;
        RECT  64.716 7.776 64.8 7.8 ;
    END
  END head_record[432]
  PIN head_record[433]
    DIRECTION INPUT ;
    USE SIGNAL ;
    PORT
      LAYER M4 ;
        RECT  64.716 8.064 64.8 8.088 ;
    END
  END head_record[433]
  PIN head_record[434]
    DIRECTION INPUT ;
    USE SIGNAL ;
    PORT
      LAYER M4 ;
        RECT  64.716 8.4 64.8 8.424 ;
    END
  END head_record[434]
  PIN head_record[435]
    DIRECTION INPUT ;
    USE SIGNAL ;
    PORT
      LAYER M4 ;
        RECT  64.716 8.688 64.8 8.712 ;
    END
  END head_record[435]
  PIN head_record[436]
    DIRECTION INPUT ;
    USE SIGNAL ;
    PORT
      LAYER M4 ;
        RECT  64.716 8.976 64.8 9 ;
    END
  END head_record[436]
  PIN head_record[437]
    DIRECTION INPUT ;
    USE SIGNAL ;
    PORT
      LAYER M4 ;
        RECT  64.716 9.312 64.8 9.336 ;
    END
  END head_record[437]
  PIN head_record[438]
    DIRECTION INPUT ;
    USE SIGNAL ;
    PORT
      LAYER M4 ;
        RECT  64.716 9.6 64.8 9.624 ;
    END
  END head_record[438]
  PIN head_record[439]
    DIRECTION INPUT ;
    USE SIGNAL ;
    PORT
      LAYER M4 ;
        RECT  64.716 9.888 64.8 9.912 ;
    END
  END head_record[439]
  PIN head_record[43]
    DIRECTION INPUT ;
    USE SIGNAL ;
    PORT
      LAYER M4 ;
        RECT  0 21.216 0.084 21.24 ;
    END
  END head_record[43]
  PIN head_record[440]
    DIRECTION INPUT ;
    USE SIGNAL ;
    PORT
      LAYER M4 ;
        RECT  64.716 10.176 64.8 10.2 ;
    END
  END head_record[440]
  PIN head_record[441]
    DIRECTION INPUT ;
    USE SIGNAL ;
    PORT
      LAYER M4 ;
        RECT  64.716 10.512 64.8 10.536 ;
    END
  END head_record[441]
  PIN head_record[442]
    DIRECTION INPUT ;
    USE SIGNAL ;
    PORT
      LAYER M4 ;
        RECT  64.716 10.8 64.8 10.824 ;
    END
  END head_record[442]
  PIN head_record[443]
    DIRECTION INPUT ;
    USE SIGNAL ;
    PORT
      LAYER M4 ;
        RECT  64.716 11.088 64.8 11.112 ;
    END
  END head_record[443]
  PIN head_record[444]
    DIRECTION INPUT ;
    USE SIGNAL ;
    PORT
      LAYER M4 ;
        RECT  64.716 11.424 64.8 11.448 ;
    END
  END head_record[444]
  PIN head_record[445]
    DIRECTION INPUT ;
    USE SIGNAL ;
    PORT
      LAYER M4 ;
        RECT  64.716 11.712 64.8 11.736 ;
    END
  END head_record[445]
  PIN head_record[446]
    DIRECTION INPUT ;
    USE SIGNAL ;
    PORT
      LAYER M4 ;
        RECT  64.716 12 64.8 12.024 ;
    END
  END head_record[446]
  PIN head_record[447]
    DIRECTION INPUT ;
    USE SIGNAL ;
    PORT
      LAYER M4 ;
        RECT  64.716 12.288 64.8 12.312 ;
    END
  END head_record[447]
  PIN head_record[448]
    DIRECTION INPUT ;
    USE SIGNAL ;
    PORT
      LAYER M4 ;
        RECT  64.716 12.624 64.8 12.648 ;
    END
  END head_record[448]
  PIN head_record[449]
    DIRECTION INPUT ;
    USE SIGNAL ;
    PORT
      LAYER M4 ;
        RECT  64.716 12.912 64.8 12.936 ;
    END
  END head_record[449]
  PIN head_record[44]
    DIRECTION INPUT ;
    USE SIGNAL ;
    PORT
      LAYER M4 ;
        RECT  0 21.648 0.084 21.672 ;
    END
  END head_record[44]
  PIN head_record[450]
    DIRECTION INPUT ;
    USE SIGNAL ;
    PORT
      LAYER M4 ;
        RECT  64.716 13.2 64.8 13.224 ;
    END
  END head_record[450]
  PIN head_record[451]
    DIRECTION INPUT ;
    USE SIGNAL ;
    PORT
      LAYER M4 ;
        RECT  64.716 13.536 64.8 13.56 ;
    END
  END head_record[451]
  PIN head_record[452]
    DIRECTION INPUT ;
    USE SIGNAL ;
    PORT
      LAYER M4 ;
        RECT  64.716 13.824 64.8 13.848 ;
    END
  END head_record[452]
  PIN head_record[453]
    DIRECTION INPUT ;
    USE SIGNAL ;
    PORT
      LAYER M4 ;
        RECT  64.716 14.112 64.8 14.136 ;
    END
  END head_record[453]
  PIN head_record[454]
    DIRECTION INPUT ;
    USE SIGNAL ;
    PORT
      LAYER M4 ;
        RECT  64.716 14.4 64.8 14.424 ;
    END
  END head_record[454]
  PIN head_record[455]
    DIRECTION INPUT ;
    USE SIGNAL ;
    PORT
      LAYER M4 ;
        RECT  64.716 14.736 64.8 14.76 ;
    END
  END head_record[455]
  PIN head_record[456]
    DIRECTION INPUT ;
    USE SIGNAL ;
    PORT
      LAYER M4 ;
        RECT  64.716 15.024 64.8 15.048 ;
    END
  END head_record[456]
  PIN head_record[457]
    DIRECTION INPUT ;
    USE SIGNAL ;
    PORT
      LAYER M4 ;
        RECT  64.716 15.312 64.8 15.336 ;
    END
  END head_record[457]
  PIN head_record[458]
    DIRECTION INPUT ;
    USE SIGNAL ;
    PORT
      LAYER M4 ;
        RECT  64.716 15.648 64.8 15.672 ;
    END
  END head_record[458]
  PIN head_record[459]
    DIRECTION INPUT ;
    USE SIGNAL ;
    PORT
      LAYER M4 ;
        RECT  64.716 15.936 64.8 15.96 ;
    END
  END head_record[459]
  PIN head_record[45]
    DIRECTION INPUT ;
    USE SIGNAL ;
    PORT
      LAYER M4 ;
        RECT  0 22.128 0.084 22.152 ;
    END
  END head_record[45]
  PIN head_record[460]
    DIRECTION INPUT ;
    USE SIGNAL ;
    PORT
      LAYER M4 ;
        RECT  64.716 16.224 64.8 16.248 ;
    END
  END head_record[460]
  PIN head_record[461]
    DIRECTION INPUT ;
    USE SIGNAL ;
    PORT
      LAYER M4 ;
        RECT  64.716 16.56 64.8 16.584 ;
    END
  END head_record[461]
  PIN head_record[462]
    DIRECTION INPUT ;
    USE SIGNAL ;
    PORT
      LAYER M4 ;
        RECT  64.716 16.848 64.8 16.872 ;
    END
  END head_record[462]
  PIN head_record[463]
    DIRECTION INPUT ;
    USE SIGNAL ;
    PORT
      LAYER M4 ;
        RECT  64.716 17.136 64.8 17.16 ;
    END
  END head_record[463]
  PIN head_record[464]
    DIRECTION INPUT ;
    USE SIGNAL ;
    PORT
      LAYER M4 ;
        RECT  64.716 17.424 64.8 17.448 ;
    END
  END head_record[464]
  PIN head_record[465]
    DIRECTION INPUT ;
    USE SIGNAL ;
    PORT
      LAYER M4 ;
        RECT  64.716 17.76 64.8 17.784 ;
    END
  END head_record[465]
  PIN head_record[466]
    DIRECTION INPUT ;
    USE SIGNAL ;
    PORT
      LAYER M4 ;
        RECT  64.716 18.048 64.8 18.072 ;
    END
  END head_record[466]
  PIN head_record[467]
    DIRECTION INPUT ;
    USE SIGNAL ;
    PORT
      LAYER M4 ;
        RECT  64.716 18.336 64.8 18.36 ;
    END
  END head_record[467]
  PIN head_record[468]
    DIRECTION INPUT ;
    USE SIGNAL ;
    PORT
      LAYER M4 ;
        RECT  64.716 18.672 64.8 18.696 ;
    END
  END head_record[468]
  PIN head_record[469]
    DIRECTION INPUT ;
    USE SIGNAL ;
    PORT
      LAYER M4 ;
        RECT  64.716 18.96 64.8 18.984 ;
    END
  END head_record[469]
  PIN head_record[46]
    DIRECTION INPUT ;
    USE SIGNAL ;
    PORT
      LAYER M4 ;
        RECT  0 22.56 0.084 22.584 ;
    END
  END head_record[46]
  PIN head_record[470]
    DIRECTION INPUT ;
    USE SIGNAL ;
    PORT
      LAYER M4 ;
        RECT  64.716 19.248 64.8 19.272 ;
    END
  END head_record[470]
  PIN head_record[471]
    DIRECTION INPUT ;
    USE SIGNAL ;
    PORT
      LAYER M4 ;
        RECT  64.716 19.536 64.8 19.56 ;
    END
  END head_record[471]
  PIN head_record[472]
    DIRECTION INPUT ;
    USE SIGNAL ;
    PORT
      LAYER M4 ;
        RECT  64.716 19.872 64.8 19.896 ;
    END
  END head_record[472]
  PIN head_record[473]
    DIRECTION INPUT ;
    USE SIGNAL ;
    PORT
      LAYER M4 ;
        RECT  64.716 20.16 64.8 20.184 ;
    END
  END head_record[473]
  PIN head_record[474]
    DIRECTION INPUT ;
    USE SIGNAL ;
    PORT
      LAYER M4 ;
        RECT  64.716 20.448 64.8 20.472 ;
    END
  END head_record[474]
  PIN head_record[475]
    DIRECTION INPUT ;
    USE SIGNAL ;
    PORT
      LAYER M4 ;
        RECT  64.716 20.784 64.8 20.808 ;
    END
  END head_record[475]
  PIN head_record[476]
    DIRECTION INPUT ;
    USE SIGNAL ;
    PORT
      LAYER M4 ;
        RECT  64.716 21.072 64.8 21.096 ;
    END
  END head_record[476]
  PIN head_record[477]
    DIRECTION INPUT ;
    USE SIGNAL ;
    PORT
      LAYER M4 ;
        RECT  64.716 21.36 64.8 21.384 ;
    END
  END head_record[477]
  PIN head_record[478]
    DIRECTION INPUT ;
    USE SIGNAL ;
    PORT
      LAYER M4 ;
        RECT  64.716 21.648 64.8 21.672 ;
    END
  END head_record[478]
  PIN head_record[479]
    DIRECTION INPUT ;
    USE SIGNAL ;
    PORT
      LAYER M4 ;
        RECT  64.716 21.984 64.8 22.008 ;
    END
  END head_record[479]
  PIN head_record[47]
    DIRECTION INPUT ;
    USE SIGNAL ;
    PORT
      LAYER M4 ;
        RECT  0 22.992 0.084 23.016 ;
    END
  END head_record[47]
  PIN head_record[480]
    DIRECTION INPUT ;
    USE SIGNAL ;
    PORT
      LAYER M4 ;
        RECT  64.716 22.272 64.8 22.296 ;
    END
  END head_record[480]
  PIN head_record[481]
    DIRECTION INPUT ;
    USE SIGNAL ;
    PORT
      LAYER M4 ;
        RECT  64.716 22.56 64.8 22.584 ;
    END
  END head_record[481]
  PIN head_record[482]
    DIRECTION INPUT ;
    USE SIGNAL ;
    PORT
      LAYER M4 ;
        RECT  64.716 22.896 64.8 22.92 ;
    END
  END head_record[482]
  PIN head_record[483]
    DIRECTION INPUT ;
    USE SIGNAL ;
    PORT
      LAYER M4 ;
        RECT  64.716 23.184 64.8 23.208 ;
    END
  END head_record[483]
  PIN head_record[484]
    DIRECTION INPUT ;
    USE SIGNAL ;
    PORT
      LAYER M4 ;
        RECT  64.716 23.472 64.8 23.496 ;
    END
  END head_record[484]
  PIN head_record[485]
    DIRECTION INPUT ;
    USE SIGNAL ;
    PORT
      LAYER M4 ;
        RECT  64.716 23.76 64.8 23.784 ;
    END
  END head_record[485]
  PIN head_record[486]
    DIRECTION INPUT ;
    USE SIGNAL ;
    PORT
      LAYER M4 ;
        RECT  64.716 24.096 64.8 24.12 ;
    END
  END head_record[486]
  PIN head_record[487]
    DIRECTION INPUT ;
    USE SIGNAL ;
    PORT
      LAYER M4 ;
        RECT  64.716 24.384 64.8 24.408 ;
    END
  END head_record[487]
  PIN head_record[488]
    DIRECTION INPUT ;
    USE SIGNAL ;
    PORT
      LAYER M4 ;
        RECT  64.716 24.672 64.8 24.696 ;
    END
  END head_record[488]
  PIN head_record[489]
    DIRECTION INPUT ;
    USE SIGNAL ;
    PORT
      LAYER M4 ;
        RECT  64.716 25.008 64.8 25.032 ;
    END
  END head_record[489]
  PIN head_record[48]
    DIRECTION INPUT ;
    USE SIGNAL ;
    PORT
      LAYER M4 ;
        RECT  0 23.424 0.084 23.448 ;
    END
  END head_record[48]
  PIN head_record[490]
    DIRECTION INPUT ;
    USE SIGNAL ;
    PORT
      LAYER M4 ;
        RECT  64.716 25.296 64.8 25.32 ;
    END
  END head_record[490]
  PIN head_record[491]
    DIRECTION INPUT ;
    USE SIGNAL ;
    PORT
      LAYER M4 ;
        RECT  64.716 25.584 64.8 25.608 ;
    END
  END head_record[491]
  PIN head_record[492]
    DIRECTION INPUT ;
    USE SIGNAL ;
    PORT
      LAYER M4 ;
        RECT  64.716 25.92 64.8 25.944 ;
    END
  END head_record[492]
  PIN head_record[493]
    DIRECTION INPUT ;
    USE SIGNAL ;
    PORT
      LAYER M4 ;
        RECT  64.716 26.208 64.8 26.232 ;
    END
  END head_record[493]
  PIN head_record[494]
    DIRECTION INPUT ;
    USE SIGNAL ;
    PORT
      LAYER M4 ;
        RECT  64.716 26.496 64.8 26.52 ;
    END
  END head_record[494]
  PIN head_record[495]
    DIRECTION INPUT ;
    USE SIGNAL ;
    PORT
      LAYER M4 ;
        RECT  64.716 26.784 64.8 26.808 ;
    END
  END head_record[495]
  PIN head_record[496]
    DIRECTION INPUT ;
    USE SIGNAL ;
    PORT
      LAYER M4 ;
        RECT  64.716 27.12 64.8 27.144 ;
    END
  END head_record[496]
  PIN head_record[497]
    DIRECTION INPUT ;
    USE SIGNAL ;
    PORT
      LAYER M4 ;
        RECT  64.716 27.408 64.8 27.432 ;
    END
  END head_record[497]
  PIN head_record[498]
    DIRECTION INPUT ;
    USE SIGNAL ;
    PORT
      LAYER M4 ;
        RECT  64.716 27.696 64.8 27.72 ;
    END
  END head_record[498]
  PIN head_record[499]
    DIRECTION INPUT ;
    USE SIGNAL ;
    PORT
      LAYER M4 ;
        RECT  64.716 28.032 64.8 28.056 ;
    END
  END head_record[499]
  PIN head_record[49]
    DIRECTION INPUT ;
    USE SIGNAL ;
    PORT
      LAYER M4 ;
        RECT  0 23.856 0.084 23.88 ;
    END
  END head_record[49]
  PIN head_record[4]
    DIRECTION INPUT ;
    USE SIGNAL ;
    PORT
      LAYER M4 ;
        RECT  0 4.176 0.084 4.2 ;
    END
  END head_record[4]
  PIN head_record[500]
    DIRECTION INPUT ;
    USE SIGNAL ;
    PORT
      LAYER M4 ;
        RECT  64.716 28.32 64.8 28.344 ;
    END
  END head_record[500]
  PIN head_record[501]
    DIRECTION INPUT ;
    USE SIGNAL ;
    PORT
      LAYER M4 ;
        RECT  64.716 28.608 64.8 28.632 ;
    END
  END head_record[501]
  PIN head_record[502]
    DIRECTION INPUT ;
    USE SIGNAL ;
    PORT
      LAYER M4 ;
        RECT  64.716 28.896 64.8 28.92 ;
    END
  END head_record[502]
  PIN head_record[503]
    DIRECTION INPUT ;
    USE SIGNAL ;
    PORT
      LAYER M4 ;
        RECT  64.716 29.232 64.8 29.256 ;
    END
  END head_record[503]
  PIN head_record[504]
    DIRECTION INPUT ;
    USE SIGNAL ;
    PORT
      LAYER M4 ;
        RECT  64.716 29.52 64.8 29.544 ;
    END
  END head_record[504]
  PIN head_record[505]
    DIRECTION INPUT ;
    USE SIGNAL ;
    PORT
      LAYER M4 ;
        RECT  64.716 29.808 64.8 29.832 ;
    END
  END head_record[505]
  PIN head_record[506]
    DIRECTION INPUT ;
    USE SIGNAL ;
    PORT
      LAYER M4 ;
        RECT  64.716 30.144 64.8 30.168 ;
    END
  END head_record[506]
  PIN head_record[507]
    DIRECTION INPUT ;
    USE SIGNAL ;
    PORT
      LAYER M4 ;
        RECT  64.716 30.432 64.8 30.456 ;
    END
  END head_record[507]
  PIN head_record[508]
    DIRECTION INPUT ;
    USE SIGNAL ;
    PORT
      LAYER M4 ;
        RECT  64.716 30.72 64.8 30.744 ;
    END
  END head_record[508]
  PIN head_record[509]
    DIRECTION INPUT ;
    USE SIGNAL ;
    PORT
      LAYER M4 ;
        RECT  64.716 31.008 64.8 31.032 ;
    END
  END head_record[509]
  PIN head_record[50]
    DIRECTION INPUT ;
    USE SIGNAL ;
    PORT
      LAYER M4 ;
        RECT  0 24.288 0.084 24.312 ;
    END
  END head_record[50]
  PIN head_record[510]
    DIRECTION INPUT ;
    USE SIGNAL ;
    PORT
      LAYER M4 ;
        RECT  64.716 31.344 64.8 31.368 ;
    END
  END head_record[510]
  PIN head_record[511]
    DIRECTION INPUT ;
    USE SIGNAL ;
    PORT
      LAYER M4 ;
        RECT  64.716 31.632 64.8 31.656 ;
    END
  END head_record[511]
  PIN head_record[512]
    DIRECTION INPUT ;
    USE SIGNAL ;
    PORT
      LAYER M4 ;
        RECT  64.716 31.92 64.8 31.944 ;
    END
  END head_record[512]
  PIN head_record[513]
    DIRECTION INPUT ;
    USE SIGNAL ;
    PORT
      LAYER M4 ;
        RECT  64.716 32.256 64.8 32.28 ;
    END
  END head_record[513]
  PIN head_record[514]
    DIRECTION INPUT ;
    USE SIGNAL ;
    PORT
      LAYER M4 ;
        RECT  64.716 32.544 64.8 32.568 ;
    END
  END head_record[514]
  PIN head_record[515]
    DIRECTION INPUT ;
    USE SIGNAL ;
    PORT
      LAYER M4 ;
        RECT  64.716 32.832 64.8 32.856 ;
    END
  END head_record[515]
  PIN head_record[516]
    DIRECTION INPUT ;
    USE SIGNAL ;
    PORT
      LAYER M4 ;
        RECT  64.716 33.12 64.8 33.144 ;
    END
  END head_record[516]
  PIN head_record[517]
    DIRECTION INPUT ;
    USE SIGNAL ;
    PORT
      LAYER M4 ;
        RECT  64.716 33.456 64.8 33.48 ;
    END
  END head_record[517]
  PIN head_record[518]
    DIRECTION INPUT ;
    USE SIGNAL ;
    PORT
      LAYER M4 ;
        RECT  64.716 33.744 64.8 33.768 ;
    END
  END head_record[518]
  PIN head_record[519]
    DIRECTION INPUT ;
    USE SIGNAL ;
    PORT
      LAYER M4 ;
        RECT  64.716 34.032 64.8 34.056 ;
    END
  END head_record[519]
  PIN head_record[51]
    DIRECTION INPUT ;
    USE SIGNAL ;
    PORT
      LAYER M4 ;
        RECT  0 24.72 0.084 24.744 ;
    END
  END head_record[51]
  PIN head_record[520]
    DIRECTION INPUT ;
    USE SIGNAL ;
    PORT
      LAYER M4 ;
        RECT  64.716 34.368 64.8 34.392 ;
    END
  END head_record[520]
  PIN head_record[521]
    DIRECTION INPUT ;
    USE SIGNAL ;
    PORT
      LAYER M4 ;
        RECT  64.716 34.656 64.8 34.68 ;
    END
  END head_record[521]
  PIN head_record[522]
    DIRECTION INPUT ;
    USE SIGNAL ;
    PORT
      LAYER M4 ;
        RECT  64.716 34.944 64.8 34.968 ;
    END
  END head_record[522]
  PIN head_record[523]
    DIRECTION INPUT ;
    USE SIGNAL ;
    PORT
      LAYER M4 ;
        RECT  64.716 35.28 64.8 35.304 ;
    END
  END head_record[523]
  PIN head_record[524]
    DIRECTION INPUT ;
    USE SIGNAL ;
    PORT
      LAYER M4 ;
        RECT  64.716 35.568 64.8 35.592 ;
    END
  END head_record[524]
  PIN head_record[525]
    DIRECTION INPUT ;
    USE SIGNAL ;
    PORT
      LAYER M4 ;
        RECT  64.716 35.856 64.8 35.88 ;
    END
  END head_record[525]
  PIN head_record[526]
    DIRECTION INPUT ;
    USE SIGNAL ;
    PORT
      LAYER M4 ;
        RECT  64.716 36.144 64.8 36.168 ;
    END
  END head_record[526]
  PIN head_record[527]
    DIRECTION INPUT ;
    USE SIGNAL ;
    PORT
      LAYER M4 ;
        RECT  64.716 36.48 64.8 36.504 ;
    END
  END head_record[527]
  PIN head_record[528]
    DIRECTION INPUT ;
    USE SIGNAL ;
    PORT
      LAYER M4 ;
        RECT  64.716 36.768 64.8 36.792 ;
    END
  END head_record[528]
  PIN head_record[529]
    DIRECTION INPUT ;
    USE SIGNAL ;
    PORT
      LAYER M4 ;
        RECT  64.716 37.056 64.8 37.08 ;
    END
  END head_record[529]
  PIN head_record[52]
    DIRECTION INPUT ;
    USE SIGNAL ;
    PORT
      LAYER M4 ;
        RECT  0 25.152 0.084 25.176 ;
    END
  END head_record[52]
  PIN head_record[530]
    DIRECTION INPUT ;
    USE SIGNAL ;
    PORT
      LAYER M4 ;
        RECT  64.716 37.392 64.8 37.416 ;
    END
  END head_record[530]
  PIN head_record[531]
    DIRECTION INPUT ;
    USE SIGNAL ;
    PORT
      LAYER M4 ;
        RECT  64.716 37.68 64.8 37.704 ;
    END
  END head_record[531]
  PIN head_record[532]
    DIRECTION INPUT ;
    USE SIGNAL ;
    PORT
      LAYER M4 ;
        RECT  64.716 37.968 64.8 37.992 ;
    END
  END head_record[532]
  PIN head_record[533]
    DIRECTION INPUT ;
    USE SIGNAL ;
    PORT
      LAYER M4 ;
        RECT  64.716 38.256 64.8 38.28 ;
    END
  END head_record[533]
  PIN head_record[534]
    DIRECTION INPUT ;
    USE SIGNAL ;
    PORT
      LAYER M4 ;
        RECT  64.716 38.592 64.8 38.616 ;
    END
  END head_record[534]
  PIN head_record[535]
    DIRECTION INPUT ;
    USE SIGNAL ;
    PORT
      LAYER M4 ;
        RECT  64.716 38.88 64.8 38.904 ;
    END
  END head_record[535]
  PIN head_record[536]
    DIRECTION INPUT ;
    USE SIGNAL ;
    PORT
      LAYER M4 ;
        RECT  64.716 39.168 64.8 39.192 ;
    END
  END head_record[536]
  PIN head_record[537]
    DIRECTION INPUT ;
    USE SIGNAL ;
    PORT
      LAYER M4 ;
        RECT  64.716 39.504 64.8 39.528 ;
    END
  END head_record[537]
  PIN head_record[538]
    DIRECTION INPUT ;
    USE SIGNAL ;
    PORT
      LAYER M4 ;
        RECT  64.716 39.792 64.8 39.816 ;
    END
  END head_record[538]
  PIN head_record[539]
    DIRECTION INPUT ;
    USE SIGNAL ;
    PORT
      LAYER M4 ;
        RECT  64.716 40.08 64.8 40.104 ;
    END
  END head_record[539]
  PIN head_record[53]
    DIRECTION INPUT ;
    USE SIGNAL ;
    PORT
      LAYER M4 ;
        RECT  0 25.584 0.084 25.608 ;
    END
  END head_record[53]
  PIN head_record[540]
    DIRECTION INPUT ;
    USE SIGNAL ;
    PORT
      LAYER M4 ;
        RECT  64.716 40.368 64.8 40.392 ;
    END
  END head_record[540]
  PIN head_record[541]
    DIRECTION INPUT ;
    USE SIGNAL ;
    PORT
      LAYER M4 ;
        RECT  64.716 40.704 64.8 40.728 ;
    END
  END head_record[541]
  PIN head_record[542]
    DIRECTION INPUT ;
    USE SIGNAL ;
    PORT
      LAYER M4 ;
        RECT  64.716 40.992 64.8 41.016 ;
    END
  END head_record[542]
  PIN head_record[543]
    DIRECTION INPUT ;
    USE SIGNAL ;
    PORT
      LAYER M4 ;
        RECT  64.716 41.28 64.8 41.304 ;
    END
  END head_record[543]
  PIN head_record[544]
    DIRECTION INPUT ;
    USE SIGNAL ;
    PORT
      LAYER M4 ;
        RECT  64.716 41.616 64.8 41.64 ;
    END
  END head_record[544]
  PIN head_record[545]
    DIRECTION INPUT ;
    USE SIGNAL ;
    PORT
      LAYER M4 ;
        RECT  64.716 41.904 64.8 41.928 ;
    END
  END head_record[545]
  PIN head_record[546]
    DIRECTION INPUT ;
    USE SIGNAL ;
    PORT
      LAYER M4 ;
        RECT  64.716 42.192 64.8 42.216 ;
    END
  END head_record[546]
  PIN head_record[547]
    DIRECTION INPUT ;
    USE SIGNAL ;
    PORT
      LAYER M4 ;
        RECT  64.716 42.48 64.8 42.504 ;
    END
  END head_record[547]
  PIN head_record[548]
    DIRECTION INPUT ;
    USE SIGNAL ;
    PORT
      LAYER M4 ;
        RECT  64.716 42.816 64.8 42.84 ;
    END
  END head_record[548]
  PIN head_record[549]
    DIRECTION INPUT ;
    USE SIGNAL ;
    PORT
      LAYER M4 ;
        RECT  64.716 43.104 64.8 43.128 ;
    END
  END head_record[549]
  PIN head_record[54]
    DIRECTION INPUT ;
    USE SIGNAL ;
    PORT
      LAYER M4 ;
        RECT  0 26.064 0.084 26.088 ;
    END
  END head_record[54]
  PIN head_record[550]
    DIRECTION INPUT ;
    USE SIGNAL ;
    PORT
      LAYER M4 ;
        RECT  64.716 43.392 64.8 43.416 ;
    END
  END head_record[550]
  PIN head_record[551]
    DIRECTION INPUT ;
    USE SIGNAL ;
    PORT
      LAYER M4 ;
        RECT  64.716 43.728 64.8 43.752 ;
    END
  END head_record[551]
  PIN head_record[55]
    DIRECTION INPUT ;
    USE SIGNAL ;
    PORT
      LAYER M4 ;
        RECT  0 26.496 0.084 26.52 ;
    END
  END head_record[55]
  PIN head_record[56]
    DIRECTION INPUT ;
    USE SIGNAL ;
    PORT
      LAYER M4 ;
        RECT  0 26.928 0.084 26.952 ;
    END
  END head_record[56]
  PIN head_record[57]
    DIRECTION INPUT ;
    USE SIGNAL ;
    PORT
      LAYER M4 ;
        RECT  0 27.36 0.084 27.384 ;
    END
  END head_record[57]
  PIN head_record[58]
    DIRECTION INPUT ;
    USE SIGNAL ;
    PORT
      LAYER M4 ;
        RECT  0 27.792 0.084 27.816 ;
    END
  END head_record[58]
  PIN head_record[59]
    DIRECTION INPUT ;
    USE SIGNAL ;
    PORT
      LAYER M4 ;
        RECT  0 28.224 0.084 28.248 ;
    END
  END head_record[59]
  PIN head_record[5]
    DIRECTION INPUT ;
    USE SIGNAL ;
    PORT
      LAYER M4 ;
        RECT  0 4.608 0.084 4.632 ;
    END
  END head_record[5]
  PIN head_record[60]
    DIRECTION INPUT ;
    USE SIGNAL ;
    PORT
      LAYER M4 ;
        RECT  0 28.656 0.084 28.68 ;
    END
  END head_record[60]
  PIN head_record[61]
    DIRECTION INPUT ;
    USE SIGNAL ;
    PORT
      LAYER M4 ;
        RECT  0 29.088 0.084 29.112 ;
    END
  END head_record[61]
  PIN head_record[62]
    DIRECTION INPUT ;
    USE SIGNAL ;
    PORT
      LAYER M4 ;
        RECT  0 29.52 0.084 29.544 ;
    END
  END head_record[62]
  PIN head_record[63]
    DIRECTION INPUT ;
    USE SIGNAL ;
    PORT
      LAYER M4 ;
        RECT  0 30 0.084 30.024 ;
    END
  END head_record[63]
  PIN head_record[64]
    DIRECTION INPUT ;
    USE SIGNAL ;
    PORT
      LAYER M4 ;
        RECT  0 30.432 0.084 30.456 ;
    END
  END head_record[64]
  PIN head_record[65]
    DIRECTION INPUT ;
    USE SIGNAL ;
    PORT
      LAYER M4 ;
        RECT  0 30.864 0.084 30.888 ;
    END
  END head_record[65]
  PIN head_record[66]
    DIRECTION INPUT ;
    USE SIGNAL ;
    PORT
      LAYER M4 ;
        RECT  0 31.296 0.084 31.32 ;
    END
  END head_record[66]
  PIN head_record[67]
    DIRECTION INPUT ;
    USE SIGNAL ;
    PORT
      LAYER M4 ;
        RECT  0 31.728 0.084 31.752 ;
    END
  END head_record[67]
  PIN head_record[68]
    DIRECTION INPUT ;
    USE SIGNAL ;
    PORT
      LAYER M4 ;
        RECT  0 32.16 0.084 32.184 ;
    END
  END head_record[68]
  PIN head_record[69]
    DIRECTION INPUT ;
    USE SIGNAL ;
    PORT
      LAYER M4 ;
        RECT  0 32.592 0.084 32.616 ;
    END
  END head_record[69]
  PIN head_record[6]
    DIRECTION INPUT ;
    USE SIGNAL ;
    PORT
      LAYER M4 ;
        RECT  0 5.04 0.084 5.064 ;
    END
  END head_record[6]
  PIN head_record[70]
    DIRECTION INPUT ;
    USE SIGNAL ;
    PORT
      LAYER M4 ;
        RECT  0 33.024 0.084 33.048 ;
    END
  END head_record[70]
  PIN head_record[71]
    DIRECTION INPUT ;
    USE SIGNAL ;
    PORT
      LAYER M4 ;
        RECT  0 33.504 0.084 33.528 ;
    END
  END head_record[71]
  PIN head_record[72]
    DIRECTION INPUT ;
    USE SIGNAL ;
    PORT
      LAYER M4 ;
        RECT  0 33.936 0.084 33.96 ;
    END
  END head_record[72]
  PIN head_record[73]
    DIRECTION INPUT ;
    USE SIGNAL ;
    PORT
      LAYER M4 ;
        RECT  0 34.368 0.084 34.392 ;
    END
  END head_record[73]
  PIN head_record[74]
    DIRECTION INPUT ;
    USE SIGNAL ;
    PORT
      LAYER M4 ;
        RECT  0 34.8 0.084 34.824 ;
    END
  END head_record[74]
  PIN head_record[75]
    DIRECTION INPUT ;
    USE SIGNAL ;
    PORT
      LAYER M4 ;
        RECT  0 35.232 0.084 35.256 ;
    END
  END head_record[75]
  PIN head_record[76]
    DIRECTION INPUT ;
    USE SIGNAL ;
    PORT
      LAYER M4 ;
        RECT  0 35.664 0.084 35.688 ;
    END
  END head_record[76]
  PIN head_record[77]
    DIRECTION INPUT ;
    USE SIGNAL ;
    PORT
      LAYER M4 ;
        RECT  0 36.096 0.084 36.12 ;
    END
  END head_record[77]
  PIN head_record[78]
    DIRECTION INPUT ;
    USE SIGNAL ;
    PORT
      LAYER M4 ;
        RECT  0 36.528 0.084 36.552 ;
    END
  END head_record[78]
  PIN head_record[79]
    DIRECTION INPUT ;
    USE SIGNAL ;
    PORT
      LAYER M4 ;
        RECT  0 36.96 0.084 36.984 ;
    END
  END head_record[79]
  PIN head_record[7]
    DIRECTION INPUT ;
    USE SIGNAL ;
    PORT
      LAYER M4 ;
        RECT  0 5.472 0.084 5.496 ;
    END
  END head_record[7]
  PIN head_record[80]
    DIRECTION INPUT ;
    USE SIGNAL ;
    PORT
      LAYER M4 ;
        RECT  0 37.44 0.084 37.464 ;
    END
  END head_record[80]
  PIN head_record[81]
    DIRECTION INPUT ;
    USE SIGNAL ;
    PORT
      LAYER M4 ;
        RECT  0 37.872 0.084 37.896 ;
    END
  END head_record[81]
  PIN head_record[82]
    DIRECTION INPUT ;
    USE SIGNAL ;
    PORT
      LAYER M4 ;
        RECT  0 38.304 0.084 38.328 ;
    END
  END head_record[82]
  PIN head_record[83]
    DIRECTION INPUT ;
    USE SIGNAL ;
    PORT
      LAYER M4 ;
        RECT  0 38.736 0.084 38.76 ;
    END
  END head_record[83]
  PIN head_record[84]
    DIRECTION INPUT ;
    USE SIGNAL ;
    PORT
      LAYER M4 ;
        RECT  0 39.168 0.084 39.192 ;
    END
  END head_record[84]
  PIN head_record[85]
    DIRECTION INPUT ;
    USE SIGNAL ;
    PORT
      LAYER M4 ;
        RECT  0 39.6 0.084 39.624 ;
    END
  END head_record[85]
  PIN head_record[86]
    DIRECTION INPUT ;
    USE SIGNAL ;
    PORT
      LAYER M4 ;
        RECT  0 40.032 0.084 40.056 ;
    END
  END head_record[86]
  PIN head_record[87]
    DIRECTION INPUT ;
    USE SIGNAL ;
    PORT
      LAYER M4 ;
        RECT  0 40.464 0.084 40.488 ;
    END
  END head_record[87]
  PIN head_record[88]
    DIRECTION INPUT ;
    USE SIGNAL ;
    PORT
      LAYER M4 ;
        RECT  0 40.944 0.084 40.968 ;
    END
  END head_record[88]
  PIN head_record[89]
    DIRECTION INPUT ;
    USE SIGNAL ;
    PORT
      LAYER M4 ;
        RECT  0 41.376 0.084 41.4 ;
    END
  END head_record[89]
  PIN head_record[8]
    DIRECTION INPUT ;
    USE SIGNAL ;
    PORT
      LAYER M4 ;
        RECT  0 5.904 0.084 5.928 ;
    END
  END head_record[8]
  PIN head_record[90]
    DIRECTION INPUT ;
    USE SIGNAL ;
    PORT
      LAYER M4 ;
        RECT  0 41.808 0.084 41.832 ;
    END
  END head_record[90]
  PIN head_record[91]
    DIRECTION INPUT ;
    USE SIGNAL ;
    PORT
      LAYER M4 ;
        RECT  0 42.24 0.084 42.264 ;
    END
  END head_record[91]
  PIN head_record[92]
    DIRECTION INPUT ;
    USE SIGNAL ;
    PORT
      LAYER M4 ;
        RECT  0 42.672 0.084 42.696 ;
    END
  END head_record[92]
  PIN head_record[93]
    DIRECTION INPUT ;
    USE SIGNAL ;
    PORT
      LAYER M4 ;
        RECT  0 43.104 0.084 43.128 ;
    END
  END head_record[93]
  PIN head_record[94]
    DIRECTION INPUT ;
    USE SIGNAL ;
    PORT
      LAYER M4 ;
        RECT  0 43.536 0.084 43.56 ;
    END
  END head_record[94]
  PIN head_record[95]
    DIRECTION INPUT ;
    USE SIGNAL ;
    PORT
      LAYER M4 ;
        RECT  0 43.968 0.084 43.992 ;
    END
  END head_record[95]
  PIN head_record[96]
    DIRECTION INPUT ;
    USE SIGNAL ;
    PORT
      LAYER M4 ;
        RECT  0 44.4 0.084 44.424 ;
    END
  END head_record[96]
  PIN head_record[97]
    DIRECTION INPUT ;
    USE SIGNAL ;
    PORT
      LAYER M4 ;
        RECT  0 44.88 0.084 44.904 ;
    END
  END head_record[97]
  PIN head_record[98]
    DIRECTION INPUT ;
    USE SIGNAL ;
    PORT
      LAYER M4 ;
        RECT  0 45.312 0.084 45.336 ;
    END
  END head_record[98]
  PIN head_record[99]
    DIRECTION INPUT ;
    USE SIGNAL ;
    PORT
      LAYER M4 ;
        RECT  0 45.744 0.084 45.768 ;
    END
  END head_record[99]
  PIN head_record[9]
    DIRECTION INPUT ;
    USE SIGNAL ;
    PORT
      LAYER M4 ;
        RECT  0 6.336 0.084 6.36 ;
    END
  END head_record[9]
  PIN ovl_users[0]
    DIRECTION INPUT ;
    USE SIGNAL ;
    PORT
      LAYER M5 ;
        RECT  30.96 64.716 30.984 64.8 ;
    END
  END ovl_users[0]
  PIN ovl_users[1]
    DIRECTION INPUT ;
    USE SIGNAL ;
    PORT
      LAYER M5 ;
        RECT  31.392 64.716 31.416 64.8 ;
    END
  END ovl_users[1]
  PIN ovl_users[2]
    DIRECTION INPUT ;
    USE SIGNAL ;
    PORT
      LAYER M5 ;
        RECT  31.776 64.716 31.8 64.8 ;
    END
  END ovl_users[2]
  PIN ovl_users[3]
    DIRECTION INPUT ;
    USE SIGNAL ;
    PORT
      LAYER M5 ;
        RECT  32.208 64.716 32.232 64.8 ;
    END
  END ovl_users[3]
  PIN reseed
    DIRECTION INPUT ;
    USE SIGNAL ;
    PORT
      LAYER M5 ;
        RECT  34.608 64.716 34.632 64.8 ;
    END
  END reseed
  PIN rst_n
    DIRECTION INPUT ;
    USE SIGNAL ;
    PORT
      LAYER M5 ;
        RECT  30.576 64.716 30.6 64.8 ;
    END
  END rst_n
  PIN VDD
    DIRECTION INOUT ;
    USE POWER ;
    PORT
      LAYER M5 ;
        RECT  61.992 2.151 62.112 62.649 ;
        RECT  59.292 2.151 59.412 62.649 ;
        RECT  56.592 2.151 56.712 62.649 ;
        RECT  53.892 2.151 54.012 62.649 ;
        RECT  51.192 2.151 51.312 62.649 ;
        RECT  48.492 2.151 48.612 62.649 ;
        RECT  45.792 2.151 45.912 62.649 ;
        RECT  43.092 2.151 43.212 62.649 ;
        RECT  40.392 2.151 40.512 62.649 ;
        RECT  37.692 2.151 37.812 62.649 ;
        RECT  34.992 2.151 35.112 62.649 ;
        RECT  32.292 2.151 32.412 62.649 ;
        RECT  29.592 2.151 29.712 62.649 ;
        RECT  26.892 2.151 27.012 62.649 ;
        RECT  24.192 2.151 24.312 62.649 ;
        RECT  21.492 2.151 21.612 62.649 ;
        RECT  18.792 2.151 18.912 62.649 ;
        RECT  16.092 2.151 16.212 62.649 ;
        RECT  13.392 2.151 13.512 62.649 ;
        RECT  10.692 2.151 10.812 62.649 ;
        RECT  7.992 2.151 8.112 62.649 ;
        RECT  5.292 2.151 5.412 62.649 ;
        RECT  2.592 2.151 2.712 62.649 ;
    END
  END VDD
  PIN VSS
    DIRECTION INOUT ;
    USE GROUND ;
    PORT
      LAYER M5 ;
        RECT  61.8 2.137 61.92 62.663 ;
        RECT  59.1 2.137 59.22 62.663 ;
        RECT  56.4 2.137 56.52 62.663 ;
        RECT  53.7 2.137 53.82 62.663 ;
        RECT  51 2.137 51.12 62.663 ;
        RECT  48.3 2.137 48.42 62.663 ;
        RECT  45.6 2.137 45.72 62.663 ;
        RECT  42.9 2.137 43.02 62.663 ;
        RECT  40.2 2.137 40.32 62.663 ;
        RECT  37.5 2.137 37.62 62.663 ;
        RECT  34.8 2.137 34.92 62.663 ;
        RECT  32.1 2.137 32.22 62.663 ;
        RECT  29.4 2.137 29.52 62.663 ;
        RECT  26.7 2.137 26.82 62.663 ;
        RECT  24 2.137 24.12 62.663 ;
        RECT  21.3 2.137 21.42 62.663 ;
        RECT  18.6 2.137 18.72 62.663 ;
        RECT  15.9 2.137 16.02 62.663 ;
        RECT  13.2 2.137 13.32 62.663 ;
        RECT  10.5 2.137 10.62 62.663 ;
        RECT  7.8 2.137 7.92 62.663 ;
        RECT  5.1 2.137 5.22 62.663 ;
        RECT  2.4 2.137 2.52 62.663 ;
    END
  END VSS
  OBS
    LAYER RVTN ;
     RECT  2.16 2.16 62.64 2.295 ;
     RECT  2.16 2.565 62.64 2.835 ;
     RECT  2.16 3.105 62.64 3.375 ;
     RECT  2.16 3.645 62.64 3.915 ;
     RECT  2.16 4.185 62.64 4.455 ;
     RECT  2.16 4.725 62.64 4.995 ;
     RECT  2.16 5.265 62.64 5.535 ;
     RECT  2.16 5.805 62.64 6.075 ;
     RECT  2.16 6.345 62.64 6.615 ;
     RECT  2.16 6.885 62.64 7.155 ;
     RECT  2.16 7.425 62.64 7.695 ;
     RECT  2.16 7.965 62.64 8.235 ;
     RECT  2.16 8.505 62.64 8.775 ;
     RECT  2.16 9.045 62.64 9.315 ;
     RECT  2.16 9.585 62.64 9.855 ;
     RECT  2.16 10.125 62.64 10.395 ;
     RECT  2.16 10.665 62.64 10.935 ;
     RECT  2.16 11.205 62.64 11.475 ;
     RECT  2.16 11.745 62.64 12.015 ;
     RECT  2.16 12.285 62.64 12.555 ;
     RECT  2.16 12.825 62.64 13.095 ;
     RECT  2.16 13.365 62.64 13.635 ;
     RECT  2.16 13.905 62.64 14.175 ;
     RECT  2.16 14.445 62.64 14.715 ;
     RECT  2.16 14.985 62.64 15.255 ;
     RECT  2.16 15.525 62.64 15.795 ;
     RECT  2.16 16.065 62.64 16.335 ;
     RECT  2.16 16.605 62.64 16.875 ;
     RECT  2.16 17.145 62.64 17.415 ;
     RECT  2.16 17.685 62.64 17.955 ;
     RECT  2.16 18.225 62.64 18.495 ;
     RECT  2.16 18.765 62.64 19.035 ;
     RECT  2.16 19.305 62.64 19.575 ;
     RECT  2.16 19.845 62.64 20.115 ;
     RECT  2.16 20.385 62.64 20.655 ;
     RECT  2.16 20.925 62.64 21.195 ;
     RECT  2.16 21.465 62.64 21.735 ;
     RECT  2.16 22.005 62.64 22.275 ;
     RECT  2.16 22.545 62.64 22.815 ;
     RECT  2.16 23.085 62.64 23.355 ;
     RECT  2.16 23.625 62.64 23.895 ;
     RECT  2.16 24.165 62.64 24.435 ;
     RECT  2.16 24.705 62.64 24.975 ;
     RECT  2.16 25.245 62.64 25.515 ;
     RECT  2.16 25.785 62.64 26.055 ;
     RECT  2.16 26.325 62.64 26.595 ;
     RECT  2.16 26.865 62.64 27.135 ;
     RECT  2.16 27.405 62.64 27.675 ;
     RECT  2.16 27.945 62.64 28.215 ;
     RECT  2.16 28.485 62.64 28.755 ;
     RECT  2.16 29.025 62.64 29.295 ;
     RECT  2.16 29.565 62.64 29.835 ;
     RECT  2.16 30.105 62.64 30.375 ;
     RECT  2.16 30.645 62.64 30.915 ;
     RECT  2.16 31.185 62.64 31.455 ;
     RECT  2.16 31.725 62.64 31.995 ;
     RECT  2.16 32.265 62.64 32.535 ;
     RECT  2.16 32.805 62.64 33.075 ;
     RECT  2.16 33.345 62.64 33.615 ;
     RECT  2.16 33.885 62.64 34.155 ;
     RECT  2.16 34.425 62.64 34.695 ;
     RECT  2.16 34.965 62.64 35.235 ;
     RECT  2.16 35.505 62.64 35.775 ;
     RECT  2.16 36.045 62.64 36.315 ;
     RECT  2.16 36.585 62.64 36.855 ;
     RECT  2.16 37.125 62.64 37.395 ;
     RECT  2.16 37.665 62.64 37.935 ;
     RECT  2.16 38.205 62.64 38.475 ;
     RECT  2.16 38.745 62.64 39.015 ;
     RECT  2.16 39.285 62.64 39.555 ;
     RECT  2.16 39.825 62.64 40.095 ;
     RECT  2.16 40.365 62.64 40.635 ;
     RECT  2.16 40.905 62.64 41.175 ;
     RECT  2.16 41.445 62.64 41.715 ;
     RECT  2.16 41.985 62.64 42.255 ;
     RECT  2.16 42.525 62.64 42.795 ;
     RECT  2.16 43.065 62.64 43.335 ;
     RECT  2.16 43.605 62.64 43.875 ;
     RECT  2.16 44.145 62.64 44.415 ;
     RECT  2.16 44.685 62.64 44.955 ;
     RECT  2.16 45.225 62.64 45.495 ;
     RECT  2.16 45.765 62.64 46.035 ;
     RECT  2.16 46.305 62.64 46.575 ;
     RECT  2.16 46.845 62.64 47.115 ;
     RECT  2.16 47.385 62.64 47.655 ;
     RECT  2.16 47.925 62.64 48.195 ;
     RECT  2.16 48.465 62.64 48.735 ;
     RECT  2.16 49.005 62.64 49.275 ;
     RECT  2.16 49.545 62.64 49.815 ;
     RECT  2.16 50.085 62.64 50.355 ;
     RECT  2.16 50.625 62.64 50.895 ;
     RECT  2.16 51.165 62.64 51.435 ;
     RECT  2.16 51.705 62.64 51.975 ;
     RECT  2.16 52.245 62.64 52.515 ;
     RECT  2.16 52.785 62.64 53.055 ;
     RECT  2.16 53.325 62.64 53.595 ;
     RECT  2.16 53.865 62.64 54.135 ;
     RECT  2.16 54.405 62.64 54.675 ;
     RECT  2.16 54.945 62.64 55.215 ;
     RECT  2.16 55.485 62.64 55.755 ;
     RECT  2.16 56.025 62.64 56.295 ;
     RECT  2.16 56.565 62.64 56.835 ;
     RECT  2.16 57.105 62.64 57.375 ;
     RECT  2.16 57.645 62.64 57.915 ;
     RECT  2.16 58.185 62.64 58.455 ;
     RECT  2.16 58.725 62.64 58.995 ;
     RECT  2.16 59.265 62.64 59.535 ;
     RECT  2.16 59.805 62.64 60.075 ;
     RECT  2.16 60.345 62.64 60.615 ;
     RECT  2.16 60.885 62.64 61.155 ;
     RECT  2.16 61.425 62.64 61.695 ;
     RECT  2.16 61.965 62.64 62.235 ;
     RECT  2.16 62.505 62.64 62.64 ;
    LAYER RVTP ;
     RECT  2.16 2.295 62.64 2.565 ;
     RECT  2.16 2.835 62.64 3.105 ;
     RECT  2.16 3.375 62.64 3.645 ;
     RECT  2.16 3.915 62.64 4.185 ;
     RECT  2.16 4.455 62.64 4.725 ;
     RECT  2.16 4.995 62.64 5.265 ;
     RECT  2.16 5.535 62.64 5.805 ;
     RECT  2.16 6.075 62.64 6.345 ;
     RECT  2.16 6.615 62.64 6.885 ;
     RECT  2.16 7.155 62.64 7.425 ;
     RECT  2.16 7.695 62.64 7.965 ;
     RECT  2.16 8.235 62.64 8.505 ;
     RECT  2.16 8.775 62.64 9.045 ;
     RECT  2.16 9.315 62.64 9.585 ;
     RECT  2.16 9.855 62.64 10.125 ;
     RECT  2.16 10.395 62.64 10.665 ;
     RECT  2.16 10.935 62.64 11.205 ;
     RECT  2.16 11.475 62.64 11.745 ;
     RECT  2.16 12.015 62.64 12.285 ;
     RECT  2.16 12.555 62.64 12.825 ;
     RECT  2.16 13.095 62.64 13.365 ;
     RECT  2.16 13.635 62.64 13.905 ;
     RECT  2.16 14.175 62.64 14.445 ;
     RECT  2.16 14.715 62.64 14.985 ;
     RECT  2.16 15.255 62.64 15.525 ;
     RECT  2.16 15.795 62.64 16.065 ;
     RECT  2.16 16.335 62.64 16.605 ;
     RECT  2.16 16.875 62.64 17.145 ;
     RECT  2.16 17.415 62.64 17.685 ;
     RECT  2.16 17.955 62.64 18.225 ;
     RECT  2.16 18.495 62.64 18.765 ;
     RECT  2.16 19.035 62.64 19.305 ;
     RECT  2.16 19.575 62.64 19.845 ;
     RECT  2.16 20.115 62.64 20.385 ;
     RECT  2.16 20.655 62.64 20.925 ;
     RECT  2.16 21.195 62.64 21.465 ;
     RECT  2.16 21.735 62.64 22.005 ;
     RECT  2.16 22.275 62.64 22.545 ;
     RECT  2.16 22.815 62.64 23.085 ;
     RECT  2.16 23.355 62.64 23.625 ;
     RECT  2.16 23.895 62.64 24.165 ;
     RECT  2.16 24.435 62.64 24.705 ;
     RECT  2.16 24.975 62.64 25.245 ;
     RECT  2.16 25.515 62.64 25.785 ;
     RECT  2.16 26.055 62.64 26.325 ;
     RECT  2.16 26.595 62.64 26.865 ;
     RECT  2.16 27.135 62.64 27.405 ;
     RECT  2.16 27.675 62.64 27.945 ;
     RECT  2.16 28.215 62.64 28.485 ;
     RECT  2.16 28.755 62.64 29.025 ;
     RECT  2.16 29.295 62.64 29.565 ;
     RECT  2.16 29.835 62.64 30.105 ;
     RECT  2.16 30.375 62.64 30.645 ;
     RECT  2.16 30.915 62.64 31.185 ;
     RECT  2.16 31.455 62.64 31.725 ;
     RECT  2.16 31.995 62.64 32.265 ;
     RECT  2.16 32.535 62.64 32.805 ;
     RECT  2.16 33.075 62.64 33.345 ;
     RECT  2.16 33.615 62.64 33.885 ;
     RECT  2.16 34.155 62.64 34.425 ;
     RECT  2.16 34.695 62.64 34.965 ;
     RECT  2.16 35.235 62.64 35.505 ;
     RECT  2.16 35.775 62.64 36.045 ;
     RECT  2.16 36.315 62.64 36.585 ;
     RECT  2.16 36.855 62.64 37.125 ;
     RECT  2.16 37.395 62.64 37.665 ;
     RECT  2.16 37.935 62.64 38.205 ;
     RECT  2.16 38.475 62.64 38.745 ;
     RECT  2.16 39.015 62.64 39.285 ;
     RECT  2.16 39.555 62.64 39.825 ;
     RECT  2.16 40.095 62.64 40.365 ;
     RECT  2.16 40.635 62.64 40.905 ;
     RECT  2.16 41.175 62.64 41.445 ;
     RECT  2.16 41.715 62.64 41.985 ;
     RECT  2.16 42.255 62.64 42.525 ;
     RECT  2.16 42.795 62.64 43.065 ;
     RECT  2.16 43.335 62.64 43.605 ;
     RECT  2.16 43.875 62.64 44.145 ;
     RECT  2.16 44.415 62.64 44.685 ;
     RECT  2.16 44.955 62.64 45.225 ;
     RECT  2.16 45.495 62.64 45.765 ;
     RECT  2.16 46.035 62.64 46.305 ;
     RECT  2.16 46.575 62.64 46.845 ;
     RECT  2.16 47.115 62.64 47.385 ;
     RECT  2.16 47.655 62.64 47.925 ;
     RECT  2.16 48.195 62.64 48.465 ;
     RECT  2.16 48.735 62.64 49.005 ;
     RECT  2.16 49.275 62.64 49.545 ;
     RECT  2.16 49.815 62.64 50.085 ;
     RECT  2.16 50.355 62.64 50.625 ;
     RECT  2.16 50.895 62.64 51.165 ;
     RECT  2.16 51.435 62.64 51.705 ;
     RECT  2.16 51.975 62.64 52.245 ;
     RECT  2.16 52.515 62.64 52.785 ;
     RECT  2.16 53.055 62.64 53.325 ;
     RECT  2.16 53.595 62.64 53.865 ;
     RECT  2.16 54.135 62.64 54.405 ;
     RECT  2.16 54.675 62.64 54.945 ;
     RECT  2.16 55.215 62.64 55.485 ;
     RECT  2.16 55.755 62.64 56.025 ;
     RECT  2.16 56.295 62.64 56.565 ;
     RECT  2.16 56.835 62.64 57.105 ;
     RECT  2.16 57.375 62.64 57.645 ;
     RECT  2.16 57.915 62.64 58.185 ;
     RECT  2.16 58.455 62.64 58.725 ;
     RECT  2.16 58.995 62.64 59.265 ;
     RECT  2.16 59.535 62.64 59.805 ;
     RECT  2.16 60.075 62.64 60.345 ;
     RECT  2.16 60.615 62.64 60.885 ;
     RECT  2.16 61.155 62.64 61.425 ;
     RECT  2.16 61.695 62.64 61.965 ;
     RECT  2.16 62.235 62.64 62.505 ;
    LAYER M1 ;
     RECT  2.16 2.151 62.64 62.649 ;
    LAYER M2 ;
     RECT  0.103 15.84 0.139 15.858 ;
     RECT  0.103 27.342 0.139 27.36 ;
     RECT  0.103 22.716 0.535 23.148 ;
     RECT  0.139 27.306 0.535 27.36 ;
     RECT  0.103 3.726 2.16 3.744 ;
     RECT  0.139 15.498 2.16 15.858 ;
     RECT  0.103 17.082 2.16 17.1 ;
     RECT  0.535 19.62 2.16 19.638 ;
     RECT  0.535 22.716 2.16 23.31 ;
     RECT  0.535 27.216 2.16 27.36 ;
     RECT  0.103 28.422 2.16 28.44 ;
     RECT  2.16 2.151 62.64 62.649 ;
     RECT  62.64 41.76 62.699 43.092 ;
     RECT  62.64 43.956 62.699 62.334 ;
     RECT  62.64 34.74 63.203 40.392 ;
     RECT  63.203 34.74 63.275 34.992 ;
     RECT  63.203 35.784 63.275 40.392 ;
     RECT  62.699 47.7 63.275 62.334 ;
     RECT  62.64 32.346 63.311 32.364 ;
     RECT  62.64 33.318 63.311 33.408 ;
     RECT  63.275 34.74 63.311 34.758 ;
     RECT  63.275 37.602 63.311 40.392 ;
     RECT  63.275 60.696 63.311 62.334 ;
     RECT  63.311 33.318 63.347 33.336 ;
     RECT  62.699 41.76 63.815 42.624 ;
     RECT  63.311 40.14 63.851 40.392 ;
     RECT  63.815 41.76 63.851 42.588 ;
     RECT  62.699 43.956 63.851 46.674 ;
     RECT  63.275 47.7 63.851 49.464 ;
     RECT  63.275 50.256 63.851 59.904 ;
     RECT  63.311 61.866 63.851 62.334 ;
     RECT  63.275 35.784 63.887 35.802 ;
     RECT  63.275 36.792 63.887 36.81 ;
     RECT  63.311 38.718 63.887 38.736 ;
     RECT  63.851 45.306 63.887 45.954 ;
     RECT  63.851 47.7 63.887 48.222 ;
     RECT  63.851 50.364 63.887 54.504 ;
     RECT  63.851 55.764 63.887 55.782 ;
     RECT  63.851 56.574 63.887 57.744 ;
     RECT  63.851 59.004 63.887 59.904 ;
     RECT  63.311 60.696 63.887 60.714 ;
     RECT  63.851 61.938 63.887 62.334 ;
     RECT  63.887 45.396 63.923 45.954 ;
     RECT  63.887 50.364 64.679 52.038 ;
     RECT  63.851 42.57 64.715 42.588 ;
     RECT  63.851 43.956 64.715 43.974 ;
     RECT  63.887 48.204 64.715 48.222 ;
     RECT  64.679 50.364 64.715 51.804 ;
     RECT  63.887 53.874 64.715 53.892 ;
     RECT  63.887 56.574 64.715 57.204 ;
     RECT  63.887 59.886 64.715 59.904 ;
     RECT  63.887 61.938 64.715 61.956 ;
    LAYER M3 ;
     RECT  2.415 2.143 2.505 2.413 ;
     RECT  5.115 2.143 5.205 2.413 ;
     RECT  7.815 2.143 7.905 2.413 ;
     RECT  10.515 2.143 10.605 2.413 ;
     RECT  13.215 2.143 13.305 2.413 ;
     RECT  15.915 2.143 16.005 2.413 ;
     RECT  18.615 2.143 18.705 2.413 ;
     RECT  21.315 2.143 21.405 2.413 ;
     RECT  24.015 2.143 24.105 2.413 ;
     RECT  26.715 2.143 26.805 2.413 ;
     RECT  29.415 2.143 29.505 2.413 ;
     RECT  32.115 2.143 32.205 2.413 ;
     RECT  34.815 2.143 34.905 2.413 ;
     RECT  37.515 2.143 37.605 2.413 ;
     RECT  40.215 2.143 40.305 2.413 ;
     RECT  42.915 2.143 43.005 2.413 ;
     RECT  45.615 2.143 45.705 2.413 ;
     RECT  48.315 2.143 48.405 2.413 ;
     RECT  51.015 2.143 51.105 2.413 ;
     RECT  53.715 2.143 53.805 2.413 ;
     RECT  56.415 2.143 56.505 2.413 ;
     RECT  59.115 2.143 59.205 2.413 ;
     RECT  61.815 2.143 61.905 2.413 ;
     RECT  3.6 3.001 3.618 3.181 ;
     RECT  3.6 3.181 3.654 3.307 ;
     RECT  3.564 3.307 3.654 3.379 ;
     RECT  3.492 3.379 3.654 3.721 ;
     RECT  2.415 2.413 2.697 3.739 ;
     RECT  2.304 3.739 2.697 3.811 ;
     RECT  3.456 3.721 3.654 3.811 ;
     RECT  2.304 3.811 3.654 3.991 ;
     RECT  2.304 3.991 3.762 4.153 ;
     RECT  60.228 3.811 60.246 4.153 ;
     RECT  2.304 4.153 3.798 4.261 ;
     RECT  2.304 4.261 3.87 4.415 ;
     RECT  0.108 3.721 0.126 4.637 ;
     RECT  34.815 2.413 35.097 4.891 ;
     RECT  34.815 4.891 35.226 5.161 ;
     RECT  5.115 2.413 5.397 5.467 ;
     RECT  4.824 5.467 5.397 5.504 ;
     RECT  2.415 4.415 3.87 5.611 ;
     RECT  2.415 5.611 4.05 5.729 ;
     RECT  2.415 5.729 3.87 5.845 ;
     RECT  2.304 5.845 3.87 5.933 ;
     RECT  26.715 2.413 26.997 5.971 ;
     RECT  13.215 2.413 13.497 6.511 ;
     RECT  21.315 2.413 21.597 6.511 ;
     RECT  13.104 6.511 13.497 6.557 ;
     RECT  21.204 6.511 21.597 6.557 ;
     RECT  2.415 5.933 3.87 6.583 ;
     RECT  2.415 6.583 3.978 6.619 ;
     RECT  5.115 5.504 5.397 6.619 ;
     RECT  14.832 6.523 14.85 6.653 ;
     RECT  22.824 6.523 22.842 6.653 ;
     RECT  25.668 6.619 25.686 6.656 ;
     RECT  26.715 5.971 27.702 6.691 ;
     RECT  2.415 6.619 5.397 6.763 ;
     RECT  2.304 6.763 5.397 6.845 ;
     RECT  26.424 6.691 27.702 6.845 ;
     RECT  2.34 6.845 5.397 7.349 ;
     RECT  2.34 7.349 4.302 7.385 ;
     RECT  29.415 2.413 29.697 7.591 ;
     RECT  2.415 7.385 4.302 7.925 ;
     RECT  2.415 7.925 3.798 8.107 ;
     RECT  2.304 8.107 3.798 8.195 ;
     RECT  25.344 7.861 25.362 8.401 ;
     RECT  26.715 6.845 27.702 8.401 ;
     RECT  5.115 7.349 5.397 8.437 ;
     RECT  5.115 8.437 5.778 8.477 ;
     RECT  5.115 8.477 5.706 8.509 ;
     RECT  4.536 8.509 5.706 8.699 ;
     RECT  2.415 8.195 3.798 8.851 ;
     RECT  4.536 8.699 5.397 8.851 ;
     RECT  2.415 8.851 5.397 8.968 ;
     RECT  2.412 8.968 5.397 9.005 ;
     RECT  24.015 2.413 24.297 9.049 ;
     RECT  6.84 8.851 6.858 9.077 ;
     RECT  32.115 2.413 32.397 9.481 ;
     RECT  2.415 9.005 5.397 9.779 ;
     RECT  7.815 2.413 8.097 9.787 ;
     RECT  2.415 9.779 4.374 9.815 ;
     RECT  5.115 9.779 5.397 9.931 ;
     RECT  32.115 9.481 32.454 10.021 ;
     RECT  5.115 9.931 5.778 10.085 ;
     RECT  7.74 9.787 8.097 10.085 ;
     RECT  2.415 9.815 3.798 10.267 ;
     RECT  31.644 10.021 32.454 10.561 ;
     RECT  5.115 10.085 5.397 11.128 ;
     RECT  2.304 10.267 3.798 11.131 ;
     RECT  5.115 11.128 6.03 11.131 ;
     RECT  24.015 9.049 24.354 11.137 ;
     RECT  25.344 8.401 27.702 11.137 ;
     RECT  29.376 7.591 29.697 11.209 ;
     RECT  2.304 11.131 6.03 11.245 ;
     RECT  7.02 11.209 7.038 11.309 ;
     RECT  2.304 11.245 6.174 11.399 ;
     RECT  2.304 11.399 4.338 11.543 ;
     RECT  5.115 11.399 5.922 11.975 ;
     RECT  28.98 11.209 29.697 12.181 ;
     RECT  5.115 11.975 5.706 12.479 ;
     RECT  2.304 11.543 4.266 12.515 ;
     RECT  21.315 6.557 21.597 12.991 ;
     RECT  5.115 12.479 5.49 13.289 ;
     RECT  21.315 12.991 21.942 13.531 ;
     RECT  2.304 12.515 4.23 13.595 ;
     RECT  6.732 13.051 6.75 13.595 ;
     RECT  2.415 13.595 4.23 13.771 ;
     RECT  5.115 13.289 5.397 13.771 ;
     RECT  2.415 13.771 5.397 14.647 ;
     RECT  2.304 14.647 5.397 14.819 ;
     RECT  20.808 13.531 21.942 14.881 ;
     RECT  2.304 14.819 4.194 14.909 ;
     RECT  2.304 14.909 3.978 14.945 ;
     RECT  6.264 14.791 6.282 15.025 ;
     RECT  6.264 15.025 6.606 15.053 ;
     RECT  6.588 15.053 6.606 15.061 ;
     RECT  6.588 15.061 6.786 15.179 ;
     RECT  20.808 14.881 22.05 15.421 ;
     RECT  23.076 8.977 23.094 15.421 ;
     RECT  6.588 15.179 6.606 15.449 ;
     RECT  2.304 14.945 3.87 15.593 ;
     RECT  2.376 15.593 3.87 15.719 ;
     RECT  0.144 15.493 0.162 15.835 ;
     RECT  0.108 15.835 0.162 16.013 ;
     RECT  2.415 15.719 3.87 16.259 ;
     RECT  0.144 16.013 0.162 16.445 ;
     RECT  24.015 11.137 27.702 16.501 ;
     RECT  31.104 10.561 32.454 16.843 ;
     RECT  30.528 16.843 32.454 16.88 ;
     RECT  7.815 10.085 8.097 16.939 ;
     RECT  14.832 16.843 14.85 16.973 ;
     RECT  30.744 16.88 32.454 17.021 ;
     RECT  5.115 14.819 5.397 17.077 ;
     RECT  4.536 17.077 5.397 17.117 ;
     RECT  7.815 16.939 8.19 17.117 ;
     RECT  0.108 17.077 0.126 17.309 ;
     RECT  2.415 16.259 3.798 17.455 ;
     RECT  2.412 17.455 3.798 17.707 ;
     RECT  13.215 6.557 13.497 17.851 ;
     RECT  13.104 17.851 13.497 17.888 ;
     RECT  31.104 17.021 32.454 17.947 ;
     RECT  6.84 17.851 6.858 17.981 ;
     RECT  14.832 17.851 14.85 17.981 ;
     RECT  34.815 5.161 35.334 18.121 ;
     RECT  5.115 17.117 5.397 18.139 ;
     RECT  34.2 18.121 35.334 18.139 ;
     RECT  31.068 17.947 32.454 18.149 ;
     RECT  33.624 18.139 35.334 18.173 ;
     RECT  33.624 18.173 33.642 18.185 ;
     RECT  2.304 17.707 3.798 18.427 ;
     RECT  4.536 18.139 5.397 18.427 ;
     RECT  2.304 18.427 5.397 18.464 ;
     RECT  33.948 18.931 33.966 20.011 ;
     RECT  34.815 18.173 35.334 20.011 ;
     RECT  0.54 19.615 0.558 20.381 ;
     RECT  2.304 18.464 4.014 20.615 ;
     RECT  2.34 20.615 4.014 20.695 ;
     RECT  5.115 18.464 5.397 20.731 ;
     RECT  24.015 16.501 28.098 20.821 ;
     RECT  28.908 12.181 29.697 20.821 ;
     RECT  5.076 20.731 5.397 21.119 ;
     RECT  31.104 18.149 32.454 21.361 ;
     RECT  2.34 20.695 4.194 21.643 ;
     RECT  2.304 21.643 4.194 22.081 ;
     RECT  2.268 22.081 4.194 22.157 ;
     RECT  31.104 21.361 32.922 22.171 ;
     RECT  2.304 22.157 4.194 22.235 ;
     RECT  2.34 22.235 4.194 22.589 ;
     RECT  31.104 22.171 33.03 22.981 ;
     RECT  33.948 20.011 35.334 22.981 ;
     RECT  0.108 22.711 0.126 23.287 ;
     RECT  0.108 23.287 0.558 23.453 ;
     RECT  0.108 23.453 0.126 23.885 ;
     RECT  40.215 2.413 40.497 24.061 ;
     RECT  2.415 22.589 4.194 24.205 ;
     RECT  60.228 4.153 60.606 24.205 ;
     RECT  61.815 2.413 62.097 24.205 ;
     RECT  2.304 24.205 4.194 24.317 ;
     RECT  40.215 24.061 40.878 24.331 ;
     RECT  2.415 24.317 4.194 25.147 ;
     RECT  2.304 25.147 4.194 25.205 ;
     RECT  42.915 2.413 43.197 25.411 ;
     RECT  41.652 24.871 41.67 25.681 ;
     RECT  42.915 25.411 43.29 25.681 ;
     RECT  2.415 25.205 4.194 26.491 ;
     RECT  59.115 2.413 59.397 26.527 ;
     RECT  60.228 24.205 62.097 26.527 ;
     RECT  45.615 2.413 45.897 26.761 ;
     RECT  2.304 26.491 4.194 26.905 ;
     RECT  2.304 26.905 4.266 26.957 ;
     RECT  0.54 27.211 0.558 27.301 ;
     RECT  45.18 26.761 45.897 27.301 ;
     RECT  0.144 27.301 0.558 27.337 ;
     RECT  0.108 27.337 0.558 27.389 ;
     RECT  44.1 26.221 44.118 27.571 ;
     RECT  45.18 27.301 45.99 27.571 ;
     RECT  0.144 27.389 0.558 27.821 ;
     RECT  2.412 26.957 4.266 27.913 ;
     RECT  2.34 27.913 4.266 28.021 ;
     RECT  2.34 28.021 4.338 28.171 ;
     RECT  5.115 21.119 5.397 28.171 ;
     RECT  13.215 17.888 13.497 28.171 ;
     RECT  13.14 28.171 13.497 28.211 ;
     RECT  0.144 27.821 0.162 28.253 ;
     RECT  40.215 24.331 40.914 28.255 ;
     RECT  41.652 25.681 43.29 28.255 ;
     RECT  0.108 28.417 0.126 28.685 ;
     RECT  6.912 28.651 6.93 28.823 ;
     RECT  2.34 28.171 5.397 28.949 ;
     RECT  40.215 28.255 43.29 29.029 ;
     RECT  2.34 28.949 4.374 29.057 ;
     RECT  2.34 29.057 4.266 29.083 ;
     RECT  59.115 26.527 62.097 29.101 ;
     RECT  2.304 29.083 4.266 29.129 ;
     RECT  58.788 29.101 62.097 29.363 ;
     RECT  60.12 29.363 62.097 29.399 ;
     RECT  2.304 29.129 4.05 29.497 ;
     RECT  58.788 29.363 59.397 29.533 ;
     RECT  2.268 29.497 4.05 29.549 ;
     RECT  58.716 29.533 59.397 29.633 ;
     RECT  2.304 29.549 4.05 29.911 ;
     RECT  5.115 28.949 5.397 29.911 ;
     RECT  6.768 29.803 6.786 30.283 ;
     RECT  6.732 30.283 6.858 30.413 ;
     RECT  2.304 29.911 5.397 30.605 ;
     RECT  2.415 30.605 5.397 30.713 ;
     RECT  37.515 2.413 37.797 30.811 ;
     RECT  2.415 30.713 3.942 31.145 ;
     RECT  60.228 29.399 62.097 31.801 ;
     RECT  59.115 29.633 59.397 32.467 ;
     RECT  60.228 31.801 62.442 32.467 ;
     RECT  3.78 31.145 3.942 32.495 ;
     RECT  59.115 32.467 62.442 32.503 ;
     RECT  2.415 31.145 3.042 32.603 ;
     RECT  58.716 32.503 62.442 32.603 ;
     RECT  60.228 32.603 62.442 32.809 ;
     RECT  63.288 32.341 63.306 33.313 ;
     RECT  63.288 33.313 63.342 33.485 ;
     RECT  60.228 32.809 62.478 33.511 ;
     RECT  63.324 33.485 63.342 33.773 ;
     RECT  31.104 22.981 35.334 33.883 ;
     RECT  30.78 33.883 35.334 34.013 ;
     RECT  59.115 32.603 59.397 34.231 ;
     RECT  64.692 34.219 64.71 34.397 ;
     RECT  60.228 33.511 62.586 34.442 ;
     RECT  40.176 29.029 43.29 34.501 ;
     RECT  60.192 34.442 62.586 34.651 ;
     RECT  60.192 34.651 63.198 34.735 ;
     RECT  58.716 34.231 59.397 34.771 ;
     RECT  60.192 34.735 63.306 34.771 ;
     RECT  44.1 27.571 45.99 34.861 ;
     RECT  31.104 34.013 35.334 35.131 ;
     RECT  58.716 34.771 63.306 35.159 ;
     RECT  58.824 35.159 63.306 35.231 ;
     RECT  31.104 35.131 35.478 35.275 ;
     RECT  36.216 3.001 36.234 35.275 ;
     RECT  24.015 20.821 29.697 35.545 ;
     RECT  59.115 35.231 63.306 35.609 ;
     RECT  31.104 35.275 36.234 35.671 ;
     RECT  24.015 35.545 29.826 35.779 ;
     RECT  60.156 35.609 63.306 35.779 ;
     RECT  24.015 35.779 30.006 35.845 ;
     RECT  31.104 35.671 36.63 35.851 ;
     RECT  60.156 35.779 63.882 35.885 ;
     RECT  44.1 34.861 46.134 36.049 ;
     RECT  59.115 35.609 59.397 36.049 ;
     RECT  24.015 35.845 30.366 36.085 ;
     RECT  31.104 35.851 36.666 36.085 ;
     RECT  58.788 36.049 59.397 36.085 ;
     RECT  60.156 35.885 63.27 36.113 ;
     RECT  24.015 36.085 36.666 36.211 ;
     RECT  24.015 36.211 36.774 36.283 ;
     RECT  37.515 30.811 38.502 36.283 ;
     RECT  60.192 36.113 63.27 36.787 ;
     RECT  44.1 36.049 46.17 36.823 ;
     RECT  24.015 36.283 38.502 36.931 ;
     RECT  44.1 36.823 46.494 36.931 ;
     RECT  60.192 36.787 63.882 36.931 ;
     RECT  58.716 36.085 59.397 37.003 ;
     RECT  60.156 36.931 63.882 37.003 ;
     RECT  58.716 37.003 63.882 37.085 ;
     RECT  24.015 36.931 38.574 37.561 ;
     RECT  24.015 37.561 38.898 37.741 ;
     RECT  40.14 34.501 43.29 37.741 ;
     RECT  24.015 37.741 43.29 38.003 ;
     RECT  24.015 38.003 38.862 38.155 ;
     RECT  23.976 38.155 38.862 38.237 ;
     RECT  23.976 38.237 38.754 38.273 ;
     RECT  58.716 37.085 63.306 38.285 ;
     RECT  58.716 38.285 62.73 38.309 ;
     RECT  44.1 36.931 46.602 38.443 ;
     RECT  44.1 38.443 46.818 38.543 ;
     RECT  3.78 32.495 3.798 38.579 ;
     RECT  58.716 38.309 59.397 38.741 ;
     RECT  63.864 38.713 63.882 38.909 ;
     RECT  60.156 38.309 62.73 39.055 ;
     RECT  20.808 15.421 23.094 39.091 ;
     RECT  23.976 38.273 38.682 39.091 ;
     RECT  40.14 38.003 43.29 39.091 ;
     RECT  20.808 39.091 38.682 39.119 ;
     RECT  23.256 39.119 38.682 39.181 ;
     RECT  23.256 39.181 38.718 39.361 ;
     RECT  39.456 39.091 43.29 39.361 ;
     RECT  44.1 38.543 46.602 39.451 ;
     RECT  44.1 39.451 46.782 39.581 ;
     RECT  54.72 39.451 54.738 39.581 ;
     RECT  59.115 38.741 59.397 39.631 ;
     RECT  60.156 39.055 63.306 39.631 ;
     RECT  57.744 39.547 57.762 39.787 ;
     RECT  58.572 39.631 63.306 39.787 ;
     RECT  23.256 39.361 43.29 39.865 ;
     RECT  44.1 39.581 46.71 39.865 ;
     RECT  20.808 39.119 22.374 39.883 ;
     RECT  23.256 39.865 46.71 39.883 ;
     RECT  57.744 39.787 63.306 40.055 ;
     RECT  60.228 40.055 63.306 40.075 ;
     RECT  20.808 39.883 46.71 40.289 ;
     RECT  20.808 40.289 46.638 40.973 ;
     RECT  57.744 40.055 59.397 40.981 ;
     RECT  60.228 40.075 63.846 40.981 ;
     RECT  45.108 40.973 46.638 41.009 ;
     RECT  57.744 40.981 63.846 41.021 ;
     RECT  57.744 41.021 62.586 41.711 ;
     RECT  45.108 41.009 46.494 41.881 ;
     RECT  56.415 2.413 56.697 42.025 ;
     RECT  63.828 41.021 63.846 42.187 ;
     RECT  63.252 42.187 63.846 42.521 ;
     RECT  63.252 42.521 63.81 42.557 ;
     RECT  64.692 41.275 64.71 42.593 ;
     RECT  63.792 42.557 63.81 42.845 ;
     RECT  57.744 41.711 62.514 43.069 ;
     RECT  57.744 43.069 62.694 43.133 ;
     RECT  20.808 40.973 44.334 43.295 ;
     RECT  57.744 43.133 62.442 43.331 ;
     RECT  57.744 43.331 62.37 43.601 ;
     RECT  61.056 43.601 62.37 43.799 ;
     RECT  61.2 43.799 62.262 43.835 ;
     RECT  64.692 43.723 64.71 43.979 ;
     RECT  63.252 43.387 63.27 44.011 ;
     RECT  61.2 43.835 62.226 44.105 ;
     RECT  63.252 44.011 63.846 44.177 ;
     RECT  20.808 43.295 22.374 44.221 ;
     RECT  23.184 43.295 44.334 44.221 ;
     RECT  61.38 44.105 62.226 44.339 ;
     RECT  61.38 44.339 62.19 44.375 ;
     RECT  48.315 2.413 48.597 44.383 ;
     RECT  48.315 44.383 49.23 44.395 ;
     RECT  20.808 44.221 44.334 44.419 ;
     RECT  45.108 41.881 46.53 44.419 ;
     RECT  48.315 44.395 49.554 44.519 ;
     RECT  61.56 44.375 62.19 44.609 ;
     RECT  48.315 44.519 49.23 44.813 ;
     RECT  61.56 44.609 62.154 45.023 ;
     RECT  61.56 45.023 62.097 45.265 ;
     RECT  63.828 44.177 63.846 45.301 ;
     RECT  63.828 45.301 63.882 45.391 ;
     RECT  61.38 45.265 62.097 45.571 ;
     RECT  61.02 45.571 62.097 45.689 ;
     RECT  63.828 45.391 63.918 45.725 ;
     RECT  61.092 45.689 62.097 45.805 ;
     RECT  61.092 45.805 62.154 45.841 ;
     RECT  61.092 45.841 62.19 46.201 ;
     RECT  61.092 46.201 62.298 46.301 ;
     RECT  57.744 43.601 60.102 46.345 ;
     RECT  54.72 46.273 54.738 46.373 ;
     RECT  63.864 45.725 63.918 46.445 ;
     RECT  57.6 46.345 60.102 46.541 ;
     RECT  63.864 46.445 63.882 46.651 ;
     RECT  20.808 44.419 46.53 46.741 ;
     RECT  63.828 46.651 63.882 46.781 ;
     RECT  56.415 42.025 56.754 46.849 ;
     RECT  58.212 46.541 60.102 46.921 ;
     RECT  61.092 46.301 62.097 46.921 ;
     RECT  58.212 46.921 62.097 47.035 ;
     RECT  20.808 46.741 46.782 47.047 ;
     RECT  20.808 47.047 47.034 47.131 ;
     RECT  58.212 47.035 62.694 47.147 ;
     RECT  63.864 46.781 63.882 47.611 ;
     RECT  20.808 47.131 47.25 47.731 ;
     RECT  58.212 47.147 62.262 47.731 ;
     RECT  58.104 47.731 62.262 47.849 ;
     RECT  64.692 47.947 64.71 48.227 ;
     RECT  20.808 47.731 47.286 48.235 ;
     RECT  56.415 46.849 57.078 48.235 ;
     RECT  58.104 47.849 59.397 48.235 ;
     RECT  20.664 48.235 47.286 48.413 ;
     RECT  20.952 48.413 47.286 48.541 ;
     RECT  48.315 44.813 48.597 48.541 ;
     RECT  63.828 47.611 63.882 48.557 ;
     RECT  56.415 48.235 59.397 48.659 ;
     RECT  60.156 47.849 62.097 48.775 ;
     RECT  56.415 48.659 57.078 48.811 ;
     RECT  20.952 48.541 48.597 48.965 ;
     RECT  57.888 48.659 59.397 49.003 ;
     RECT  60.156 48.775 62.298 49.003 ;
     RECT  54.72 48.271 54.738 49.009 ;
     RECT  20.952 48.965 47.574 49.037 ;
     RECT  54.72 49.009 54.81 49.051 ;
     RECT  54.72 49.051 54.882 49.109 ;
     RECT  56.304 48.811 57.078 49.207 ;
     RECT  20.988 49.037 47.574 49.235 ;
     RECT  57.888 49.003 62.298 49.235 ;
     RECT  21.096 49.235 47.574 49.307 ;
     RECT  56.232 49.207 57.078 49.351 ;
     RECT  21.132 49.307 47.574 49.379 ;
     RECT  56.16 49.351 57.078 49.421 ;
     RECT  63.828 48.557 63.846 49.435 ;
     RECT  56.415 49.421 57.078 49.477 ;
     RECT  57.888 49.235 59.598 49.477 ;
     RECT  56.415 49.477 59.598 49.517 ;
     RECT  63.252 49.435 63.846 49.541 ;
     RECT  57.924 49.517 59.598 49.565 ;
     RECT  54.72 49.109 54.81 49.577 ;
     RECT  21.132 49.379 47.502 49.649 ;
     RECT  60.516 49.235 62.298 49.819 ;
     RECT  58.14 49.565 59.598 49.883 ;
     RECT  60.516 49.819 62.694 50.093 ;
     RECT  21.315 49.649 47.502 50.161 ;
     RECT  48.315 48.965 48.597 50.161 ;
     RECT  60.516 50.093 62.37 50.251 ;
     RECT  60.372 50.251 62.37 50.279 ;
     RECT  63.828 49.541 63.846 50.279 ;
     RECT  60.372 50.279 62.298 50.549 ;
     RECT  60.984 50.549 62.226 50.621 ;
     RECT  56.415 49.517 57.078 50.665 ;
     RECT  58.212 49.883 59.598 50.665 ;
     RECT  54.72 50.359 54.738 50.693 ;
     RECT  56.304 50.665 57.078 50.717 ;
     RECT  56.415 50.717 57.078 50.791 ;
     RECT  63.288 50.593 63.306 51.005 ;
     RECT  61.452 50.621 62.226 51.089 ;
     RECT  61.452 51.089 62.19 51.161 ;
     RECT  56.415 50.791 57.15 51.205 ;
     RECT  58.212 50.665 60.246 51.359 ;
     RECT  56.415 51.205 57.222 51.637 ;
     RECT  61.452 51.161 62.097 51.673 ;
     RECT  56.415 51.637 57.294 51.739 ;
     RECT  61.38 51.673 62.097 51.745 ;
     RECT  55.908 51.739 57.294 51.773 ;
     RECT  64.692 50.347 64.71 51.809 ;
     RECT  61.2 51.745 62.097 51.907 ;
     RECT  64.656 51.835 64.674 52.043 ;
     RECT  54.72 51.871 54.738 52.079 ;
     RECT  21.315 50.161 48.597 52.205 ;
     RECT  63.828 52.171 63.846 52.249 ;
     RECT  58.212 51.359 59.886 52.321 ;
     RECT  61.2 51.907 62.262 52.321 ;
     RECT  63.288 52.249 63.846 52.493 ;
     RECT  55.908 51.773 57.222 52.591 ;
     RECT  58.212 52.321 62.262 52.591 ;
     RECT  63.828 52.493 63.846 52.591 ;
     RECT  55.908 52.591 62.262 52.709 ;
     RECT  55.908 52.709 62.154 52.889 ;
     RECT  63.828 52.591 63.882 52.979 ;
     RECT  55.908 52.889 59.598 53.015 ;
     RECT  22.356 52.205 48.597 53.293 ;
     RECT  22.32 53.293 48.597 53.357 ;
     RECT  22.32 53.357 22.518 53.591 ;
     RECT  60.444 52.889 62.154 53.671 ;
     RECT  63.864 52.979 63.882 53.693 ;
     RECT  56.415 53.015 59.598 53.761 ;
     RECT  60.444 53.671 62.334 53.761 ;
     RECT  22.356 53.591 22.518 53.789 ;
     RECT  56.415 53.761 62.334 53.833 ;
     RECT  54.792 53.671 54.81 53.897 ;
     RECT  64.692 53.371 64.71 53.897 ;
     RECT  56.415 53.833 62.73 53.981 ;
     RECT  22.356 53.789 22.374 54.125 ;
     RECT  23.364 53.357 48.597 54.131 ;
     RECT  51.015 2.413 51.297 54.481 ;
     RECT  63.828 54.283 63.846 54.481 ;
     RECT  50.688 54.481 51.297 54.599 ;
     RECT  56.415 53.981 62.154 54.599 ;
     RECT  63.828 54.481 63.882 54.605 ;
     RECT  56.415 54.599 62.097 54.635 ;
     RECT  56.415 54.635 59.814 54.869 ;
     RECT  23.796 54.131 48.597 54.949 ;
     RECT  23.724 54.949 48.597 55.021 ;
     RECT  63.828 54.605 63.846 55.247 ;
     RECT  56.415 54.869 59.598 55.339 ;
     RECT  60.552 54.635 62.097 55.381 ;
     RECT  23.616 55.021 48.597 55.409 ;
     RECT  55.98 55.339 59.598 55.469 ;
     RECT  25.344 55.409 48.597 55.481 ;
     RECT  60.552 55.381 62.154 55.483 ;
     RECT  25.344 55.481 25.362 55.517 ;
     RECT  54.72 55.381 54.738 55.553 ;
     RECT  60.552 55.483 62.694 55.589 ;
     RECT  23.616 55.409 24.498 55.675 ;
     RECT  26.1 55.481 48.597 55.787 ;
     RECT  63.864 55.759 63.882 55.805 ;
     RECT  23.508 55.675 24.498 55.949 ;
     RECT  23.508 55.949 24.297 56.093 ;
     RECT  56.415 55.469 59.598 56.101 ;
     RECT  60.552 55.589 62.097 56.101 ;
     RECT  63.828 56.107 63.846 56.219 ;
     RECT  26.136 55.787 48.597 56.285 ;
     RECT  26.388 56.285 48.597 56.399 ;
     RECT  23.688 56.093 24.297 56.429 ;
     RECT  56.415 56.101 62.097 56.489 ;
     RECT  47.052 56.399 48.597 56.525 ;
     RECT  26.388 56.399 46.206 56.561 ;
     RECT  56.415 56.489 59.598 56.587 ;
     RECT  47.124 56.525 48.597 56.633 ;
     RECT  26.388 56.561 46.17 56.669 ;
     RECT  60.444 56.489 62.097 56.669 ;
     RECT  61.776 56.669 62.097 56.683 ;
     RECT  55.836 56.587 59.598 56.759 ;
     RECT  54.72 56.533 54.738 57.209 ;
     RECT  64.692 56.395 64.71 57.209 ;
     RECT  60.444 56.669 60.894 57.271 ;
     RECT  61.776 56.683 62.154 57.271 ;
     RECT  61.776 57.271 62.73 57.341 ;
     RECT  56.415 56.759 59.598 57.379 ;
     RECT  60.372 57.271 60.894 57.379 ;
     RECT  56.415 57.379 60.894 57.451 ;
     RECT  61.776 57.341 62.694 57.451 ;
     RECT  26.715 56.669 46.17 57.569 ;
     RECT  56.415 57.451 62.694 57.569 ;
     RECT  57.528 57.569 62.694 57.947 ;
     RECT  47.412 56.633 48.597 58.081 ;
     RECT  63.864 57.379 63.882 58.219 ;
     RECT  57.528 57.947 62.37 58.451 ;
     RECT  26.715 57.569 45.897 58.487 ;
     RECT  63.828 58.219 63.882 58.507 ;
     RECT  57.528 58.451 61.002 58.649 ;
     RECT  63.792 58.507 63.882 58.649 ;
     RECT  56.415 57.569 56.754 59.029 ;
     RECT  56.304 59.029 56.754 59.069 ;
     RECT  61.815 58.451 62.37 59.233 ;
     RECT  60.552 58.649 61.002 59.305 ;
     RECT  61.815 59.233 62.514 59.305 ;
     RECT  63.864 58.649 63.882 59.419 ;
     RECT  46.692 58.081 48.597 59.459 ;
     RECT  63.828 59.419 63.882 59.459 ;
     RECT  57.528 58.649 59.397 59.467 ;
     RECT  60.552 59.305 62.514 59.503 ;
     RECT  54.792 59.503 54.81 59.603 ;
     RECT  27.756 58.487 45.897 59.639 ;
     RECT  60.552 59.503 62.694 59.729 ;
     RECT  28.332 59.639 45.897 59.837 ;
     RECT  56.415 59.069 56.754 59.845 ;
     RECT  57.528 59.467 59.778 59.845 ;
     RECT  46.692 59.459 46.71 59.881 ;
     RECT  28.332 59.837 42.066 59.909 ;
     RECT  47.448 59.459 48.597 59.909 ;
     RECT  64.692 59.707 64.71 59.909 ;
     RECT  46.656 59.881 46.71 59.999 ;
     RECT  54.72 59.611 54.738 59.999 ;
     RECT  60.552 59.729 62.514 60.029 ;
     RECT  56.415 59.845 59.778 60.151 ;
     RECT  60.552 60.029 62.334 60.151 ;
     RECT  56.415 60.151 62.334 60.221 ;
     RECT  57.528 60.221 62.334 60.269 ;
     RECT  63.864 59.459 63.882 60.331 ;
     RECT  63.252 60.331 63.882 60.413 ;
     RECT  28.332 59.909 41.958 60.511 ;
     RECT  58.572 60.269 62.334 60.539 ;
     RECT  28.116 60.511 41.958 60.691 ;
     RECT  42.804 59.837 45.897 60.691 ;
     RECT  28.116 60.691 45.897 60.845 ;
     RECT  63.864 60.413 63.882 60.941 ;
     RECT  57.528 60.269 57.546 61.079 ;
     RECT  56.415 60.221 56.754 61.087 ;
     RECT  56.304 61.087 57.402 61.133 ;
     RECT  63.288 61.189 63.306 61.229 ;
     RECT  58.572 60.539 62.097 61.231 ;
     RECT  58.32 61.231 62.097 61.349 ;
     RECT  56.415 61.133 57.258 61.421 ;
     RECT  58.68 61.349 62.097 61.465 ;
     RECT  26.715 58.487 26.997 61.579 ;
     RECT  26.715 61.579 27.45 61.591 ;
     RECT  28.26 60.845 45.897 61.591 ;
     RECT  26.715 61.591 45.897 61.619 ;
     RECT  47.808 59.909 48.597 61.619 ;
     RECT  28.62 61.619 45.897 61.723 ;
     RECT  46.692 59.999 46.71 61.723 ;
     RECT  28.62 61.723 46.71 61.763 ;
     RECT  26.715 61.619 27.702 61.889 ;
     RECT  28.62 61.763 45.897 61.889 ;
     RECT  47.484 61.699 47.574 61.889 ;
     RECT  58.68 61.465 62.334 61.889 ;
     RECT  46.692 61.763 46.71 61.897 ;
     RECT  55.008 61.699 55.026 61.897 ;
     RECT  47.556 61.889 47.574 61.925 ;
     RECT  53.715 2.413 53.997 61.933 ;
     RECT  55.008 61.897 55.206 61.933 ;
     RECT  46.692 61.897 46.746 61.961 ;
     RECT  64.692 61.531 64.71 61.961 ;
     RECT  63.828 61.819 63.846 61.969 ;
     RECT  37.008 61.889 45.897 61.997 ;
     RECT  61.236 61.889 62.334 61.997 ;
     RECT  37.116 61.997 45.897 62.033 ;
     RECT  46.728 61.961 46.746 62.069 ;
     RECT  63.288 61.969 63.846 62.141 ;
     RECT  58.68 61.889 60.354 62.155 ;
     RECT  28.62 61.889 36.234 62.159 ;
     RECT  37.515 62.033 43.902 62.159 ;
     RECT  61.416 61.997 62.334 62.159 ;
     RECT  39.348 62.159 43.758 62.189 ;
     RECT  28.62 62.159 36.054 62.195 ;
     RECT  44.676 62.033 45.897 62.195 ;
     RECT  58.5 62.155 60.354 62.195 ;
     RECT  45.072 62.195 45.897 62.231 ;
     RECT  58.716 62.195 60.354 62.231 ;
     RECT  61.416 62.159 62.154 62.231 ;
     RECT  53.715 61.933 55.206 62.303 ;
     RECT  58.716 62.231 60.246 62.303 ;
     RECT  56.415 61.421 57.15 62.311 ;
     RECT  39.348 62.189 43.542 62.339 ;
     RECT  2.415 32.603 2.697 62.387 ;
     RECT  5.115 30.713 5.397 62.387 ;
     RECT  7.815 17.117 8.097 62.387 ;
     RECT  10.515 2.413 10.797 62.387 ;
     RECT  13.215 28.211 13.497 62.387 ;
     RECT  15.915 2.413 16.197 62.387 ;
     RECT  18.615 2.413 18.897 62.387 ;
     RECT  21.315 52.205 21.597 62.387 ;
     RECT  24.015 56.429 24.297 62.387 ;
     RECT  26.715 61.889 26.997 62.387 ;
     RECT  39.348 62.339 42.174 62.387 ;
     RECT  45.144 62.231 45.897 62.387 ;
     RECT  48.315 61.619 48.597 62.387 ;
     RECT  51.015 54.599 51.297 62.387 ;
     RECT  53.715 62.303 53.997 62.387 ;
     RECT  56.415 62.311 57.366 62.387 ;
     RECT  28.62 62.195 35.658 62.429 ;
     RECT  37.515 62.159 38.25 62.429 ;
     RECT  39.348 62.387 40.374 62.429 ;
     RECT  41.148 62.387 42.174 62.429 ;
     RECT  57.348 62.387 57.366 62.429 ;
     RECT  58.716 62.303 59.706 62.429 ;
     RECT  61.815 62.231 62.154 62.429 ;
     RECT  37.515 62.429 38.106 62.465 ;
     RECT  39.492 62.429 40.374 62.477 ;
     RECT  41.328 62.429 42.03 62.477 ;
     RECT  63.864 62.311 63.882 62.477 ;
     RECT  41.328 62.477 41.346 62.501 ;
     RECT  45.144 62.387 45.705 62.501 ;
     RECT  58.716 62.429 59.634 62.501 ;
     RECT  39.492 62.477 40.305 62.537 ;
     RECT  28.62 62.429 28.638 62.573 ;
     RECT  33.444 62.429 35.262 62.573 ;
     RECT  39.564 62.537 40.305 62.573 ;
     RECT  42.915 62.339 43.542 62.573 ;
     RECT  45.252 62.501 45.705 62.573 ;
     RECT  33.444 62.573 34.905 62.609 ;
     RECT  45.504 62.573 45.705 62.609 ;
     RECT  59.115 62.501 59.634 62.609 ;
     RECT  30.42 62.429 30.438 62.621 ;
     RECT  31.824 62.429 32.706 62.621 ;
     RECT  2.415 62.387 2.505 62.657 ;
     RECT  5.115 62.387 5.205 62.657 ;
     RECT  7.815 62.387 7.905 62.657 ;
     RECT  10.515 62.387 10.605 62.657 ;
     RECT  13.215 62.387 13.305 62.657 ;
     RECT  15.915 62.387 16.005 62.657 ;
     RECT  18.615 62.387 18.705 62.657 ;
     RECT  21.315 62.387 21.405 62.657 ;
     RECT  24.015 62.387 24.105 62.657 ;
     RECT  26.715 62.387 26.805 62.657 ;
     RECT  29.415 62.429 29.505 62.657 ;
     RECT  34.815 62.609 34.905 62.657 ;
     RECT  37.515 62.465 37.605 62.657 ;
     RECT  40.215 62.573 40.305 62.657 ;
     RECT  42.915 62.573 43.005 62.657 ;
     RECT  45.615 62.609 45.705 62.657 ;
     RECT  48.315 62.387 48.405 62.657 ;
     RECT  51.015 62.387 51.105 62.657 ;
     RECT  53.715 62.387 53.805 62.657 ;
     RECT  56.415 62.387 56.505 62.657 ;
     RECT  59.115 62.609 59.205 62.657 ;
     RECT  61.815 62.429 61.905 62.657 ;
     RECT  31.824 62.621 32.418 62.717 ;
     RECT  33.444 62.609 33.966 62.717 ;
     RECT  31.968 62.717 32.418 62.813 ;
     RECT  32.4 62.813 32.418 64.397 ;
    LAYER M4 ;
     RECT  0.06 3.744 0.173 30.456 ;
     RECT  0.173 16.848 0.569 27.816 ;
     RECT  0.173 3.744 2.408 15.576 ;
     RECT  0.569 16.848 2.408 22.584 ;
     RECT  0.569 24.288 2.408 26.952 ;
     RECT  0.173 29.088 2.408 30.456 ;
     RECT  2.408 2.148 2.512 62.652 ;
     RECT  2.512 2.418 2.704 62.382 ;
     RECT  2.704 5.04 2.765 5.064 ;
     RECT  2.704 23.712 2.765 24.744 ;
     RECT  2.704 6.336 2.801 6.36 ;
     RECT  2.704 7.776 2.801 12.072 ;
     RECT  2.801 9.072 2.837 11.16 ;
     RECT  2.704 14.208 3.197 14.232 ;
     RECT  2.704 26.064 3.305 26.088 ;
     RECT  2.704 29.52 3.491 30.792 ;
     RECT  3.491 29.52 3.521 30.552 ;
     RECT  2.837 10.752 3.593 11.16 ;
     RECT  2.801 7.776 3.949 7.8 ;
     RECT  3.697 15.696 3.973 15.72 ;
     RECT  3.949 6.816 3.989 7.8 ;
     RECT  2.765 23.712 3.989 24.216 ;
     RECT  3.973 14.784 4.019 15.72 ;
     RECT  3.521 30.384 4.019 30.552 ;
     RECT  4.019 14.784 4.061 14.808 ;
     RECT  3.989 6.816 4.105 7.416 ;
     RECT  4.021 13.68 4.213 13.704 ;
     RECT  4.105 6.816 4.525 6.84 ;
     RECT  4.381 18.432 4.525 18.456 ;
     RECT  2.837 9.072 4.949 9.096 ;
     RECT  4.949 9.072 4.981 9.672 ;
     RECT  3.593 11.136 4.981 11.16 ;
     RECT  4.021 12.528 4.981 12.552 ;
     RECT  4.813 5.472 5.108 5.496 ;
     RECT  4.525 6.624 5.108 6.84 ;
     RECT  4.981 9.072 5.108 9.816 ;
     RECT  4.981 11.136 5.108 12.552 ;
     RECT  4.213 13.68 5.108 14.136 ;
     RECT  4.525 17.088 5.108 17.112 ;
     RECT  4.525 18.144 5.108 18.456 ;
     RECT  3.989 23.712 5.108 23.736 ;
     RECT  3.877 28.176 5.108 28.2 ;
     RECT  4.019 30.384 5.108 30.456 ;
     RECT  5.108 2.148 5.212 62.652 ;
     RECT  5.212 2.418 5.404 62.382 ;
     RECT  5.404 8.448 5.789 8.472 ;
     RECT  5.404 11.136 5.933 11.784 ;
     RECT  5.933 11.136 6.041 11.16 ;
     RECT  5.404 30.384 6.721 30.408 ;
     RECT  5.404 13.056 6.761 13.08 ;
     RECT  5.404 5.472 7.808 5.496 ;
     RECT  5.404 6.624 7.808 6.648 ;
     RECT  5.404 9.792 7.808 9.816 ;
     RECT  5.404 17.088 7.808 18.456 ;
     RECT  6.721 30.288 7.808 30.408 ;
     RECT  7.808 2.148 7.912 62.652 ;
     RECT  7.912 2.418 8.104 62.382 ;
     RECT  8.104 16.944 8.201 18.456 ;
     RECT  8.104 5.472 10.508 5.496 ;
     RECT  8.104 6.624 10.508 6.648 ;
     RECT  8.201 16.944 10.508 16.968 ;
     RECT  8.201 17.952 10.508 18.456 ;
     RECT  8.104 30.384 10.508 30.408 ;
     RECT  10.508 2.148 10.612 62.652 ;
     RECT  10.612 2.418 10.804 62.382 ;
     RECT  10.804 30.288 13.093 30.312 ;
     RECT  10.804 5.472 13.208 5.496 ;
     RECT  10.804 6.528 13.208 6.552 ;
     RECT  10.804 16.944 13.208 18.456 ;
     RECT  13.129 28.176 13.208 28.2 ;
     RECT  13.093 30.288 13.208 30.408 ;
     RECT  13.208 2.148 13.312 62.652 ;
     RECT  13.312 2.418 13.504 62.382 ;
     RECT  13.504 28.176 13.619 28.296 ;
     RECT  13.504 30.384 13.619 30.408 ;
     RECT  13.504 6.528 14.821 6.552 ;
     RECT  13.504 16.944 14.821 18.456 ;
     RECT  14.821 6.528 14.861 6.648 ;
     RECT  14.821 16.848 14.861 18.456 ;
     RECT  13.504 5.472 15.908 5.496 ;
     RECT  14.861 6.624 15.908 6.648 ;
     RECT  14.861 16.848 15.908 16.872 ;
     RECT  14.861 17.952 15.908 18.456 ;
     RECT  13.619 28.176 15.908 28.2 ;
     RECT  13.504 38.688 15.908 38.712 ;
     RECT  15.908 2.148 16.012 62.652 ;
     RECT  16.012 2.418 16.204 62.382 ;
     RECT  16.204 5.472 18.608 5.496 ;
     RECT  16.204 6.624 18.608 6.648 ;
     RECT  16.204 16.848 18.608 16.872 ;
     RECT  16.204 17.952 18.608 18.456 ;
     RECT  16.204 28.176 18.608 28.2 ;
     RECT  16.204 38.688 18.608 38.712 ;
     RECT  18.608 2.148 18.712 62.652 ;
     RECT  18.712 2.418 18.904 62.382 ;
     RECT  20.653 48.384 20.941 48.408 ;
     RECT  21.116 46.944 21.157 46.968 ;
     RECT  20.941 48.384 21.157 49.032 ;
     RECT  18.904 5.472 21.308 5.496 ;
     RECT  18.904 6.528 21.308 6.552 ;
     RECT  18.904 16.848 21.308 16.872 ;
     RECT  18.904 17.856 21.308 18.456 ;
     RECT  18.904 28.176 21.308 28.2 ;
     RECT  18.904 38.688 21.308 38.712 ;
     RECT  21.301 45.696 21.308 45.72 ;
     RECT  21.157 46.944 21.308 49.032 ;
     RECT  21.308 2.148 21.412 62.652 ;
     RECT  21.412 2.418 21.604 62.382 ;
     RECT  21.604 47.568 21.665 49.032 ;
     RECT  21.604 16.848 21.701 18.456 ;
     RECT  21.604 50.256 22.115 51.672 ;
     RECT  22.115 51.312 22.141 51.672 ;
     RECT  22.141 51.648 22.169 51.672 ;
     RECT  21.604 44.256 22.3 46.104 ;
     RECT  22.3 44.928 22.601 46.104 ;
     RECT  21.604 6.528 22.813 6.552 ;
     RECT  21.701 16.944 22.813 18.456 ;
     RECT  22.813 52.56 22.837 52.584 ;
     RECT  21.604 54.096 22.837 54.12 ;
     RECT  22.601 46.08 22.849 46.104 ;
     RECT  22.813 6.528 22.853 6.648 ;
     RECT  22.813 16.848 22.853 18.456 ;
     RECT  22.837 52.56 22.897 54.12 ;
     RECT  22.849 46.08 23.029 46.2 ;
     RECT  21.665 47.568 23.029 47.976 ;
     RECT  23.029 46.08 23.641 47.976 ;
     RECT  23.461 55.68 23.677 55.704 ;
     RECT  22.601 44.928 23.893 44.952 ;
     RECT  21.604 38.688 23.965 38.712 ;
     RECT  21.604 5.472 24.008 5.496 ;
     RECT  22.853 6.624 24.008 6.648 ;
     RECT  22.853 16.848 24.008 16.872 ;
     RECT  22.853 17.856 24.008 18.456 ;
     RECT  21.604 28.176 24.008 28.2 ;
     RECT  23.965 38.16 24.008 38.712 ;
     RECT  22.993 39.888 24.008 39.912 ;
     RECT  22.885 42.288 24.008 42.312 ;
     RECT  23.893 44.928 24.008 45 ;
     RECT  23.641 46.08 24.008 48.408 ;
     RECT  22.115 50.256 24.008 50.28 ;
     RECT  22.897 53.52 24.008 54.12 ;
     RECT  23.677 55.68 24.008 56.424 ;
     RECT  23.701 59.808 24.008 59.832 ;
     RECT  24.008 2.148 24.112 62.652 ;
     RECT  24.112 2.418 24.304 62.382 ;
     RECT  24.304 52.944 24.437 54.456 ;
     RECT  24.437 52.944 24.553 54.168 ;
     RECT  24.304 46.608 24.581 48.984 ;
     RECT  24.304 44.928 24.797 45.048 ;
     RECT  24.581 46.608 24.797 47.88 ;
     RECT  24.304 38.16 24.941 38.712 ;
     RECT  24.304 39.888 25.121 39.912 ;
     RECT  24.553 52.944 25.193 53.544 ;
     RECT  25.585 40.512 25.621 40.824 ;
     RECT  24.304 42.288 25.621 42.312 ;
     RECT  24.304 50.208 25.621 51.432 ;
     RECT  25.58 55.008 25.667 55.032 ;
     RECT  24.304 6.624 25.697 6.648 ;
     RECT  25.621 40.512 25.705 42.312 ;
     RECT  25.621 50.208 25.909 51.768 ;
     RECT  24.797 44.976 26.06 45.048 ;
     RECT  26.06 44.976 26.089 45.288 ;
     RECT  24.797 46.8 26.089 47.88 ;
     RECT  24.581 48.96 26.089 48.984 ;
     RECT  25.705 41.904 26.101 42.312 ;
     RECT  25.945 43.296 26.101 43.32 ;
     RECT  26.101 41.904 26.125 43.32 ;
     RECT  26.089 44.688 26.125 45.288 ;
     RECT  26.089 46.8 26.161 48.984 ;
     RECT  25.909 50.16 26.161 51.768 ;
     RECT  26.125 41.904 26.233 45.288 ;
     RECT  26.161 46.8 26.233 51.768 ;
     RECT  25.193 52.944 26.233 53.112 ;
     RECT  24.941 38.4 26.341 38.712 ;
     RECT  26.341 38.4 26.437 39.336 ;
     RECT  25.705 40.512 26.437 40.824 ;
     RECT  24.304 5.472 26.708 5.496 ;
     RECT  26.413 6.816 26.708 6.84 ;
     RECT  24.304 16.848 26.708 16.872 ;
     RECT  24.304 17.952 26.708 18.456 ;
     RECT  24.304 28.176 26.708 28.2 ;
     RECT  26.581 35.712 26.708 35.736 ;
     RECT  26.125 37.056 26.708 37.08 ;
     RECT  26.437 38.4 26.708 40.824 ;
     RECT  26.233 41.904 26.708 53.112 ;
     RECT  25.621 56.256 26.708 56.28 ;
     RECT  24.304 59.808 26.708 59.832 ;
     RECT  26.708 2.148 26.812 62.652 ;
     RECT  26.812 2.418 27.004 62.382 ;
     RECT  27.004 28.176 27.203 28.2 ;
     RECT  27.004 41.616 27.281 44.712 ;
     RECT  27.004 46.224 27.317 49.32 ;
     RECT  27.281 43.92 27.749 44.712 ;
     RECT  27.317 46.224 27.821 47.16 ;
     RECT  27.004 51.936 27.971 55.08 ;
     RECT  27.971 54.72 28.019 55.08 ;
     RECT  27.749 43.92 28.073 44.424 ;
     RECT  27.004 38.16 28.253 39.96 ;
     RECT  27.004 59.808 28.46 59.832 ;
     RECT  28.253 38.88 28.465 39.96 ;
     RECT  28.46 59.808 28.465 60.504 ;
     RECT  27.004 61.584 28.465 61.608 ;
     RECT  28.465 38.88 28.609 40.44 ;
     RECT  27.317 48.48 28.609 49.32 ;
     RECT  28.393 50.64 28.609 50.664 ;
     RECT  28.609 48.48 28.741 50.664 ;
     RECT  27.971 51.936 28.741 53.592 ;
     RECT  27.821 46.224 28.753 46.248 ;
     RECT  28.753 45.984 28.789 46.248 ;
     RECT  28.609 38.88 28.933 40.488 ;
     RECT  27.281 41.616 28.933 42.216 ;
     RECT  27.004 35.712 29.077 35.736 ;
     RECT  28.789 45.984 29.077 46.632 ;
     RECT  28.741 48.48 29.221 53.592 ;
     RECT  28.019 54.72 29.221 54.744 ;
     RECT  29.077 45.264 29.293 46.632 ;
     RECT  27.004 5.472 29.408 5.496 ;
     RECT  27.004 16.848 29.408 16.872 ;
     RECT  27.004 17.952 29.408 18.456 ;
     RECT  27.004 34.128 29.408 34.152 ;
     RECT  29.077 35.712 29.408 36.024 ;
     RECT  29.149 37.872 29.408 37.896 ;
     RECT  28.933 38.88 29.408 42.216 ;
     RECT  28.465 43.632 29.408 43.848 ;
     RECT  29.293 45.264 29.408 47.352 ;
     RECT  29.221 48.48 29.408 54.744 ;
     RECT  27.004 56.256 29.408 56.28 ;
     RECT  28.465 59.808 29.408 61.608 ;
     RECT  29.408 2.148 29.512 62.652 ;
     RECT  29.512 2.418 29.704 62.616 ;
     RECT  29.704 39.552 29.765 50.136 ;
     RECT  29.704 51.216 29.801 55.512 ;
     RECT  29.801 51.216 30.125 53.352 ;
     RECT  29.765 39.552 30.131 44.76 ;
     RECT  29.704 35.856 30.197 38.232 ;
     RECT  29.704 60 30.305 60.936 ;
     RECT  29.765 45.984 30.341 50.136 ;
     RECT  30.341 46.848 30.485 50.136 ;
     RECT  29.801 54.576 30.515 55.512 ;
     RECT  30.197 38.208 30.521 38.232 ;
     RECT  29.704 16.848 30.557 16.872 ;
     RECT  29.704 57.168 30.557 58.68 ;
     RECT  29.704 61.92 30.611 62.616 ;
     RECT  29.704 17.952 30.689 18.456 ;
     RECT  30.557 58.656 30.697 58.68 ;
     RECT  30.131 39.552 30.733 42.072 ;
     RECT  29.704 33.984 30.755 34.824 ;
     RECT  30.755 33.984 30.769 34.152 ;
     RECT  30.689 16.992 30.773 18.456 ;
     RECT  30.131 43.296 30.809 43.656 ;
     RECT  30.485 47.28 30.809 50.136 ;
     RECT  30.611 61.92 30.845 61.944 ;
     RECT  30.733 39.264 30.913 42.072 ;
     RECT  30.773 17.952 31.097 18.456 ;
     RECT  30.913 39.168 31.141 42.072 ;
     RECT  30.809 43.296 31.141 43.32 ;
     RECT  30.131 44.736 31.237 44.76 ;
     RECT  30.557 57.168 31.237 57.432 ;
     RECT  30.125 51.36 31.285 53.352 ;
     RECT  31.237 57.024 31.345 57.432 ;
     RECT  30.515 55.488 31.525 55.512 ;
     RECT  31.237 44.736 31.597 45.528 ;
     RECT  31.285 51.168 31.633 53.352 ;
     RECT  30.197 35.856 31.669 37.032 ;
     RECT  31.597 44.736 31.705 46.104 ;
     RECT  31.705 44.736 31.777 46.296 ;
     RECT  31.141 39.168 31.849 43.32 ;
     RECT  31.849 39.168 31.861 43.608 ;
     RECT  31.777 44.736 31.861 46.44 ;
     RECT  30.769 33.888 31.909 34.152 ;
     RECT  31.669 35.712 31.909 37.032 ;
     RECT  30.697 58.656 31.909 59.256 ;
     RECT  30.305 60.624 31.909 60.936 ;
     RECT  31.909 58.656 31.949 60.936 ;
     RECT  31.765 62.688 31.957 62.712 ;
     RECT  30.809 47.856 31.993 50.136 ;
     RECT  31.633 51.168 31.993 53.784 ;
     RECT  31.861 39.168 32.029 46.44 ;
     RECT  31.525 55.488 32.101 55.848 ;
     RECT  29.704 5.472 32.108 5.496 ;
     RECT  31.097 18.144 32.108 18.456 ;
     RECT  31.909 33.888 32.108 37.032 ;
     RECT  32.029 38.208 32.108 46.44 ;
     RECT  31.993 47.856 32.108 53.88 ;
     RECT  32.101 55.248 32.108 55.848 ;
     RECT  31.345 56.976 32.108 57.432 ;
     RECT  31.949 58.656 32.108 61.032 ;
     RECT  31.957 62.688 32.108 62.808 ;
     RECT  32.108 2.148 32.212 62.808 ;
     RECT  32.212 2.418 32.243 62.808 ;
     RECT  32.243 2.418 32.404 62.616 ;
     RECT  32.404 45.312 32.465 55.272 ;
     RECT  32.404 33.888 32.501 36.936 ;
     RECT  32.404 57.696 32.531 60.984 ;
     RECT  32.501 33.888 32.573 36.888 ;
     RECT  32.531 58.752 32.573 60.984 ;
     RECT  32.389 64.368 32.627 64.392 ;
     RECT  32.465 45.312 32.645 53.448 ;
     RECT  32.573 34.128 32.753 36.888 ;
     RECT  32.645 45.312 32.753 48.168 ;
     RECT  32.573 58.896 32.789 60.984 ;
     RECT  32.404 38.208 32.933 41.064 ;
     RECT  32.404 62.592 33.011 62.616 ;
     RECT  32.645 49.248 33.107 53.448 ;
     RECT  32.753 45.312 33.113 47.64 ;
     RECT  33.107 49.248 33.203 53.352 ;
     RECT  32.933 38.208 33.329 40.968 ;
     RECT  32.531 57.696 33.329 57.72 ;
     RECT  32.404 42.528 33.397 44.184 ;
     RECT  33.113 45.312 33.397 46.872 ;
     RECT  32.753 35.712 33.436 36.888 ;
     RECT  33.397 42.528 33.481 46.872 ;
     RECT  33.481 42.528 33.577 44.184 ;
     RECT  32.789 58.896 33.901 58.92 ;
     RECT  32.465 55.248 33.937 55.272 ;
     RECT  33.329 38.496 34.009 40.968 ;
     RECT  33.577 42 34.009 44.184 ;
     RECT  33.877 47.904 34.114 48.216 ;
     RECT  33.481 45.456 34.153 46.872 ;
     RECT  33.389 62.688 34.211 62.712 ;
     RECT  34.114 47.904 34.225 48.264 ;
     RECT  33.203 49.248 34.225 50.664 ;
     RECT  34.225 47.904 34.333 50.664 ;
     RECT  33.203 51.744 34.333 53.352 ;
     RECT  34.153 45.456 34.441 46.92 ;
     RECT  34.333 47.904 34.441 53.352 ;
     RECT  33.937 54.336 34.477 55.272 ;
     RECT  33.901 58.416 34.801 58.92 ;
     RECT  32.404 5.472 34.808 5.496 ;
     RECT  32.404 18.144 34.808 18.168 ;
     RECT  32.753 34.128 34.808 34.152 ;
     RECT  33.436 35.712 34.808 35.736 ;
     RECT  33.436 36.864 34.808 36.888 ;
     RECT  34.009 38.496 34.808 44.184 ;
     RECT  34.441 45.456 34.808 53.352 ;
     RECT  34.477 54.336 34.808 55.992 ;
     RECT  34.801 58.416 34.808 58.968 ;
     RECT  32.789 60.624 34.808 60.984 ;
     RECT  34.597 62.016 34.808 62.652 ;
     RECT  34.808 2.148 34.912 62.652 ;
     RECT  34.912 2.418 35.104 62.382 ;
     RECT  35.104 58.944 35.165 62.184 ;
     RECT  35.104 46.224 35.219 57.336 ;
     RECT  35.219 46.224 35.237 53.352 ;
     RECT  35.219 54.336 35.245 57.336 ;
     RECT  35.104 5.472 35.267 5.496 ;
     RECT  35.104 41.952 35.267 43.752 ;
     RECT  35.237 46.272 35.309 53.352 ;
     RECT  35.309 46.56 35.345 53.352 ;
     RECT  35.345 47.664 35.363 53.352 ;
     RECT  35.104 35.568 35.381 36.936 ;
     RECT  35.245 57.216 35.417 57.336 ;
     RECT  35.417 57.264 35.453 57.336 ;
     RECT  35.381 35.568 35.489 36.888 ;
     RECT  35.345 46.56 35.489 46.632 ;
     RECT  35.363 50.4 35.561 53.352 ;
     RECT  35.104 38.16 35.813 38.52 ;
     RECT  35.453 57.264 35.939 57.288 ;
     RECT  35.165 59.328 36.065 62.184 ;
     RECT  35.561 52.368 36.197 53.352 ;
     RECT  35.245 54.336 36.197 56.232 ;
     RECT  35.267 43.728 36.277 43.752 ;
     RECT  35.104 34.128 36.323 34.152 ;
     RECT  36.277 43.728 36.373 43.944 ;
     RECT  36.065 59.328 36.425 61.512 ;
     RECT  36.197 52.368 36.433 56.232 ;
     RECT  35.104 39.552 36.469 40.968 ;
     RECT  35.267 41.952 36.469 42.744 ;
     RECT  36.425 59.328 36.485 59.448 ;
     RECT  35.363 47.664 36.529 49.32 ;
     RECT  35.561 50.4 36.529 51.336 ;
     RECT  36.469 39.552 36.533 42.744 ;
     RECT  35.489 35.856 36.745 36.888 ;
     RECT  35.813 38.16 36.745 38.184 ;
     RECT  35.489 46.56 36.817 46.584 ;
     RECT  36.529 47.664 36.817 51.336 ;
     RECT  36.433 52.368 36.817 53.16 ;
     RECT  36.373 43.728 36.997 44.424 ;
     RECT  36.485 57.792 37.141 59.448 ;
     RECT  36.817 46.56 37.465 53.16 ;
     RECT  36.745 35.856 37.508 38.184 ;
     RECT  36.533 39.552 37.508 42.024 ;
     RECT  36.997 43.584 37.508 44.424 ;
     RECT  37.465 45.984 37.508 53.16 ;
     RECT  36.433 54.336 37.508 56.232 ;
     RECT  37.141 57.36 37.508 59.448 ;
     RECT  36.425 60.624 37.508 61.512 ;
     RECT  37.508 2.148 37.612 62.652 ;
     RECT  37.612 2.418 37.804 62.382 ;
     RECT  37.804 45.984 37.901 50.424 ;
     RECT  37.901 45.984 37.973 49.32 ;
     RECT  37.804 51.936 38.003 60.84 ;
     RECT  38.003 51.936 38.045 54.888 ;
     RECT  37.804 41.376 38.333 42.024 ;
     RECT  37.804 37.584 38.62 37.608 ;
     RECT  37.804 38.88 38.62 40.344 ;
     RECT  38.003 56.496 38.729 60.84 ;
     RECT  38.62 39.504 38.837 40.344 ;
     RECT  38.729 56.496 38.837 58.152 ;
     RECT  38.333 41.664 38.869 42.024 ;
     RECT  37.973 46.56 38.941 49.32 ;
     RECT  38.941 45.696 38.945 49.32 ;
     RECT  38.876 61.872 38.963 61.896 ;
     RECT  38.837 56.496 38.981 57.384 ;
     RECT  38.869 41.664 39.053 42.168 ;
     RECT  38.045 52.176 39.089 54.888 ;
     RECT  39.053 41.904 39.125 42.168 ;
     RECT  38.945 47.664 39.197 49.32 ;
     RECT  39.089 52.272 39.197 54.888 ;
     RECT  37.804 43.392 39.229 44.52 ;
     RECT  38.945 45.696 39.229 46.584 ;
     RECT  38.729 59.184 39.301 60.84 ;
     RECT  38.981 56.496 39.337 56.856 ;
     RECT  39.197 47.712 39.74 49.32 ;
     RECT  37.901 50.4 39.74 50.424 ;
     RECT  39.337 56.352 39.769 56.856 ;
     RECT  39.125 42 39.829 42.168 ;
     RECT  39.229 43.392 39.829 46.584 ;
     RECT  39.769 56.304 39.949 56.856 ;
     RECT  39.197 52.272 40.165 54.744 ;
     RECT  38.837 39.552 40.208 40.344 ;
     RECT  39.829 42 40.208 46.584 ;
     RECT  39.74 47.712 40.208 50.424 ;
     RECT  40.165 52.032 40.208 54.744 ;
     RECT  39.949 56.064 40.208 56.856 ;
     RECT  40.069 57.936 40.208 57.96 ;
     RECT  39.301 59.184 40.208 61.656 ;
     RECT  40.208 2.148 40.312 62.652 ;
     RECT  40.312 2.418 40.504 62.472 ;
     RECT  40.504 43.536 40.709 49.32 ;
     RECT  40.504 50.4 40.853 56.616 ;
     RECT  40.709 45.552 40.925 49.32 ;
     RECT  40.853 50.4 40.961 53.544 ;
     RECT  40.504 40.848 41.069 40.92 ;
     RECT  40.925 47.664 41.249 49.32 ;
     RECT  40.925 45.552 41.501 46.584 ;
     RECT  41.249 47.712 41.501 49.32 ;
     RECT  41.069 40.848 41.609 40.872 ;
     RECT  41.501 47.712 41.717 47.976 ;
     RECT  40.504 57.936 41.825 62.472 ;
     RECT  41.501 45.6 41.933 46.584 ;
     RECT  41.501 49.248 42.469 49.32 ;
     RECT  41.825 57.936 42.505 60.936 ;
     RECT  40.853 54.72 42.541 56.616 ;
     RECT  42.505 57.6 42.541 60.936 ;
     RECT  40.961 50.4 42.668 53.4 ;
     RECT  42.541 54.72 42.668 60.936 ;
     RECT  41.933 45.696 42.757 46.584 ;
     RECT  41.717 47.712 42.757 47.736 ;
     RECT  42.469 48.96 42.793 49.32 ;
     RECT  42.793 48.768 42.829 49.32 ;
     RECT  42.668 50.4 42.829 60.936 ;
     RECT  40.504 39.552 42.908 39.816 ;
     RECT  40.709 43.536 42.908 44.424 ;
     RECT  42.757 45.696 42.908 47.736 ;
     RECT  42.829 48.768 42.908 60.936 ;
     RECT  41.825 62.016 42.908 62.472 ;
     RECT  42.908 2.148 43.012 62.652 ;
     RECT  43.012 2.418 43.204 62.382 ;
     RECT  43.204 48.192 43.697 55.176 ;
     RECT  43.697 48.192 43.733 54.888 ;
     RECT  43.204 61.056 43.811 62.184 ;
     RECT  43.204 56.352 43.877 59.784 ;
     RECT  43.733 48.768 43.949 54.888 ;
     RECT  43.877 56.592 43.985 59.784 ;
     RECT  43.985 56.592 44.129 57.048 ;
     RECT  43.949 48.768 44.165 52.536 ;
     RECT  43.204 44.4 44.201 47.16 ;
     RECT  44.201 45.696 44.269 47.16 ;
     RECT  44.165 48.768 44.273 52.248 ;
     RECT  43.985 58.416 44.345 59.784 ;
     RECT  44.345 59.52 44.413 59.784 ;
     RECT  43.811 61.056 44.413 62.04 ;
     RECT  44.269 45.696 44.633 47.304 ;
     RECT  44.633 46.8 44.953 47.304 ;
     RECT  44.273 48.768 44.953 50.424 ;
     RECT  44.129 56.592 44.989 56.616 ;
     RECT  44.273 51.936 45.205 52.248 ;
     RECT  43.949 53.616 45.205 54.888 ;
     RECT  44.953 46.8 45.385 50.424 ;
     RECT  45.385 46.8 45.452 50.664 ;
     RECT  45.205 51.936 45.452 54.888 ;
     RECT  43.204 39.552 45.608 39.816 ;
     RECT  44.201 44.4 45.608 44.424 ;
     RECT  44.633 45.696 45.608 45.816 ;
     RECT  45.452 46.8 45.608 54.888 ;
     RECT  44.989 56.256 45.608 56.616 ;
     RECT  45.025 57.888 45.608 57.912 ;
     RECT  44.413 59.52 45.608 62.04 ;
     RECT  45.608 2.148 45.712 62.652 ;
     RECT  45.712 2.418 45.904 62.382 ;
     RECT  45.904 45.696 46.145 45.816 ;
     RECT  45.904 46.8 46.253 47.16 ;
     RECT  45.904 48.768 46.289 54.648 ;
     RECT  45.904 56.016 46.289 56.376 ;
     RECT  45.904 61.728 46.541 61.752 ;
     RECT  46.289 56.016 46.721 56.28 ;
     RECT  45.904 39.456 46.793 39.816 ;
     RECT  46.721 56.016 46.793 56.04 ;
     RECT  46.289 54.432 47.045 54.648 ;
     RECT  47.045 54.528 47.117 54.648 ;
     RECT  47.117 54.528 47.219 54.552 ;
     RECT  46.253 47.136 47.261 47.16 ;
     RECT  46.289 48.768 47.333 53.448 ;
     RECT  46.793 39.552 48.308 39.816 ;
     RECT  45.904 44.4 48.308 44.424 ;
     RECT  46.145 45.696 48.308 45.72 ;
     RECT  47.333 48.768 48.308 51.24 ;
     RECT  47.333 52.8 48.308 52.968 ;
     RECT  48.308 2.148 48.412 62.652 ;
     RECT  48.412 2.418 48.604 62.382 ;
     RECT  48.604 44.4 49.235 45.72 ;
     RECT  49.235 44.4 49.276 44.808 ;
     RECT  48.604 39.552 51.008 39.816 ;
     RECT  49.276 44.4 51.008 44.424 ;
     RECT  48.604 49.296 51.008 49.32 ;
     RECT  51.008 2.148 51.112 62.652 ;
     RECT  51.112 2.418 51.304 62.382 ;
     RECT  51.304 39.552 53.708 39.816 ;
     RECT  51.304 44.4 53.708 44.424 ;
     RECT  51.304 49.296 53.708 49.32 ;
     RECT  53.708 2.148 53.812 62.652 ;
     RECT  53.812 2.418 54.004 62.382 ;
     RECT  54.004 62.16 54.707 62.184 ;
     RECT  54.004 39.456 54.749 39.816 ;
     RECT  54.004 49.056 54.893 49.32 ;
     RECT  55.957 55.44 55.969 55.464 ;
     RECT  54.893 49.296 56.149 49.32 ;
     RECT  54.749 39.552 56.408 39.816 ;
     RECT  54.004 44.4 56.408 44.424 ;
     RECT  56.293 48.24 56.408 48.264 ;
     RECT  56.149 49.296 56.408 49.416 ;
     RECT  56.252 50.688 56.408 50.712 ;
     RECT  55.897 51.744 56.408 51.768 ;
     RECT  56.005 53.808 56.408 53.832 ;
     RECT  55.969 55.344 56.408 55.464 ;
     RECT  55.825 56.592 56.408 56.616 ;
     RECT  56.293 59.04 56.408 59.064 ;
     RECT  54.004 61.104 56.408 61.128 ;
     RECT  56.408 2.148 56.512 62.652 ;
     RECT  56.512 2.418 56.704 62.382 ;
     RECT  56.704 59.04 57.059 59.064 ;
     RECT  56.704 60.192 57.059 61.656 ;
     RECT  56.704 51.744 57.305 51.768 ;
     RECT  56.704 56.592 57.413 57.528 ;
     RECT  57.059 61.104 57.413 61.656 ;
     RECT  56.704 46.512 57.629 46.536 ;
     RECT  56.704 48.24 57.692 48.264 ;
     RECT  56.704 49.296 57.692 49.32 ;
     RECT  56.704 44.4 57.733 44.424 ;
     RECT  56.704 53.808 57.733 54.12 ;
     RECT  57.692 48.24 57.769 49.32 ;
     RECT  56.704 39.552 57.773 39.816 ;
     RECT  57.733 43.92 57.779 44.424 ;
     RECT  57.779 43.92 57.875 43.944 ;
     RECT  57.769 48.24 57.913 49.512 ;
     RECT  57.413 57.504 58.097 57.528 ;
     RECT  57.733 53.184 58.237 54.12 ;
     RECT  57.913 48.24 58.417 49.56 ;
     RECT  58.129 58.704 58.417 58.728 ;
     RECT  57.413 61.632 58.46 61.656 ;
     RECT  58.417 47.616 58.669 49.56 ;
     RECT  58.669 47.616 58.981 50.136 ;
     RECT  57.773 39.744 59.108 39.816 ;
     RECT  58.489 46.224 59.108 46.248 ;
     RECT  58.981 47.616 59.108 51 ;
     RECT  58.237 52.56 59.108 54.12 ;
     RECT  58.417 58.128 59.108 58.728 ;
     RECT  58.46 61.632 59.108 62.184 ;
     RECT  59.108 2.148 59.212 62.652 ;
     RECT  59.212 2.418 59.404 62.382 ;
     RECT  59.404 58.128 59.465 58.152 ;
     RECT  59.404 47.28 59.501 47.64 ;
     RECT  59.404 52.56 59.681 52.584 ;
     RECT  59.404 45.696 59.795 46.248 ;
     RECT  59.404 49.008 59.825 49.032 ;
     RECT  59.501 47.28 59.933 47.304 ;
     RECT  59.404 61.632 60.437 61.656 ;
     RECT  59.404 43.296 60.473 43.32 ;
     RECT  59.404 39.6 60.757 39.768 ;
     RECT  59.404 41.52 60.757 41.544 ;
     RECT  60.829 32.496 60.937 32.52 ;
     RECT  59.404 34.464 61.093 37.032 ;
     RECT  61.093 34.128 61.117 37.032 ;
     RECT  60.757 39.6 61.117 40.296 ;
     RECT  60.757 41.52 61.117 42.168 ;
     RECT  61.117 39.6 61.441 42.168 ;
     RECT  61.441 39.6 61.532 42.264 ;
     RECT  61.369 44.304 61.532 44.328 ;
     RECT  60.937 32.448 61.621 32.52 ;
     RECT  61.621 32.448 61.765 33.048 ;
     RECT  61.117 34.128 61.765 37.608 ;
     RECT  61.765 32.448 61.808 37.608 ;
     RECT  61.532 39.6 61.808 44.568 ;
     RECT  61.477 47.328 61.808 47.352 ;
     RECT  61.808 2.148 61.912 62.652 ;
     RECT  61.912 2.418 62.104 62.382 ;
     RECT  62.104 46.128 62.237 47.352 ;
     RECT  62.104 41.616 62.273 43.128 ;
     RECT  62.104 34.032 63.169 34.248 ;
     RECT  63.169 34.032 63.241 34.68 ;
     RECT  62.104 36.144 63.241 36.168 ;
     RECT  62.104 37.392 63.241 38.616 ;
     RECT  62.273 41.616 63.241 41.64 ;
     RECT  62.273 43.104 63.241 43.128 ;
     RECT  62.104 50.064 63.241 50.088 ;
     RECT  62.104 60 63.241 60.024 ;
     RECT  63.241 34.032 63.277 39.192 ;
     RECT  63.241 41.616 63.277 43.416 ;
     RECT  63.241 49.44 63.277 50.088 ;
     RECT  62.104 53.088 63.277 53.976 ;
     RECT  63.241 60 63.277 60.36 ;
     RECT  62.104 56.688 63.781 57.912 ;
     RECT  63.277 33.12 63.817 39.816 ;
     RECT  63.277 40.992 63.817 43.416 ;
     RECT  62.237 46.128 63.817 47.064 ;
     RECT  63.277 49.44 63.817 51 ;
     RECT  63.277 52.464 63.817 53.976 ;
     RECT  62.104 55.488 63.817 55.512 ;
     RECT  63.781 56.688 63.817 58.536 ;
     RECT  63.277 60 63.817 62.136 ;
     RECT  63.817 52.176 63.853 62.136 ;
     RECT  63.817 33.12 64.645 51 ;
     RECT  63.853 52.176 64.645 62.472 ;
     RECT  64.645 33.12 64.764 62.472 ;
    LAYER M5 ;
     RECT  2.4 2.137 2.52 2.151 ;
     RECT  5.1 2.137 5.22 2.151 ;
     RECT  7.8 2.137 7.92 2.151 ;
     RECT  10.5 2.137 10.62 2.151 ;
     RECT  13.2 2.137 13.32 2.151 ;
     RECT  15.9 2.137 16.02 2.151 ;
     RECT  18.6 2.137 18.72 2.151 ;
     RECT  21.3 2.137 21.42 2.151 ;
     RECT  24 2.137 24.12 2.151 ;
     RECT  26.7 2.137 26.82 2.151 ;
     RECT  29.4 2.137 29.52 2.151 ;
     RECT  32.1 2.137 32.22 2.151 ;
     RECT  34.8 2.137 34.92 2.151 ;
     RECT  37.5 2.137 37.62 2.151 ;
     RECT  40.2 2.137 40.32 2.151 ;
     RECT  42.9 2.137 43.02 2.151 ;
     RECT  45.6 2.137 45.72 2.151 ;
     RECT  48.3 2.137 48.42 2.151 ;
     RECT  51 2.137 51.12 2.151 ;
     RECT  53.7 2.137 53.82 2.151 ;
     RECT  56.4 2.137 56.52 2.151 ;
     RECT  59.1 2.137 59.22 2.151 ;
     RECT  61.8 2.137 61.92 2.151 ;
     RECT  34.8 2.151 35.112 5.461 ;
     RECT  26.7 2.151 27.012 6.805 ;
     RECT  2.4 2.151 2.712 7.765 ;
     RECT  4.032 7.381 4.056 7.765 ;
     RECT  5.1 2.151 5.412 8.437 ;
     RECT  2.4 7.765 4.056 9.637 ;
     RECT  5.1 8.437 5.736 9.637 ;
     RECT  2.4 9.637 5.736 9.827 ;
     RECT  2.4 9.827 5.412 11.171 ;
     RECT  4.032 11.171 5.412 13.715 ;
     RECT  4.224 13.715 5.412 14.773 ;
     RECT  3.984 14.773 5.412 15.731 ;
     RECT  24 2.151 24.312 17.845 ;
     RECT  23.904 17.845 24.312 17.987 ;
     RECT  34.8 5.461 35.256 18.133 ;
     RECT  30.72 16.981 30.744 18.181 ;
     RECT  32.1 2.151 32.412 18.181 ;
     RECT  4.224 15.731 5.412 23.701 ;
     RECT  3.984 23.701 5.412 23.747 ;
     RECT  26.448 6.805 27.012 28.165 ;
     RECT  13.2 2.151 13.512 28.261 ;
     RECT  2.4 11.171 2.712 29.509 ;
     RECT  3.984 23.747 4.008 29.509 ;
     RECT  13.2 28.261 13.608 30.277 ;
     RECT  13.104 30.277 13.608 30.419 ;
     RECT  2.4 29.509 4.008 30.563 ;
     RECT  2.4 30.563 3.48 30.803 ;
     RECT  61.8 2.151 62.112 32.437 ;
     RECT  29.4 2.151 29.712 33.973 ;
     RECT  30.72 18.181 32.412 33.973 ;
     RECT  29.4 33.973 32.412 35.701 ;
     RECT  34.08 18.133 35.256 35.701 ;
     RECT  36.288 34.117 36.312 35.845 ;
     RECT  37.5 2.151 37.812 35.845 ;
     RECT  60.96 32.437 62.112 36.229 ;
     RECT  60.432 36.229 62.112 36.275 ;
     RECT  29.4 35.701 35.256 36.515 ;
     RECT  36.288 35.845 37.812 37.573 ;
     RECT  36.288 37.573 38.568 37.619 ;
     RECT  26.448 28.165 27.192 38.149 ;
     RECT  29.4 36.515 32.412 38.197 ;
     RECT  13.2 30.419 13.608 38.723 ;
     RECT  26.448 38.149 27.96 38.915 ;
     RECT  37.5 37.619 38.568 38.915 ;
     RECT  40.2 2.151 40.512 39.589 ;
     RECT  60.432 36.275 60.456 39.731 ;
     RECT  26.448 38.915 27.192 39.779 ;
     RECT  26.544 39.779 27.192 39.923 ;
     RECT  29.4 38.197 33.096 40.067 ;
     RECT  29.4 40.067 32.412 40.405 ;
     RECT  36.288 37.619 36.312 40.453 ;
     RECT  26.544 39.923 27.012 40.981 ;
     RECT  61.8 36.275 62.112 41.557 ;
     RECT  28.992 40.405 32.412 41.651 ;
     RECT  25.632 40.981 27.012 41.939 ;
     RECT  34.08 36.515 35.256 42.085 ;
     RECT  36.288 40.453 36.504 42.227 ;
     RECT  40.08 39.589 40.512 42.709 ;
     RECT  33.84 42.085 35.256 42.851 ;
     RECT  33.84 42.851 35.208 43.235 ;
     RECT  59.1 2.151 59.412 43.285 ;
     RECT  39.84 42.709 40.512 43.523 ;
     RECT  36.288 42.227 36.312 43.909 ;
     RECT  57.84 39.733 57.864 43.909 ;
     RECT  36.288 43.909 36.408 43.955 ;
     RECT  57.744 43.909 57.864 43.955 ;
     RECT  33.84 43.235 35.112 44.149 ;
     RECT  21.3 2.151 21.612 44.245 ;
     RECT  61.584 41.557 62.112 44.579 ;
     RECT  48.3 2.151 48.612 44.773 ;
     RECT  24 17.987 24.312 44.965 ;
     RECT  29.4 41.651 32.412 45.301 ;
     RECT  33.408 44.149 35.112 45.301 ;
     RECT  21.3 44.245 22.248 45.587 ;
     RECT  45.6 2.151 45.912 45.685 ;
     RECT  48.3 44.773 49.224 45.731 ;
     RECT  29.4 45.301 35.112 46.741 ;
     RECT  29.4 46.741 35.256 46.883 ;
     RECT  21.3 45.587 21.612 46.933 ;
     RECT  23.904 44.965 24.312 47.171 ;
     RECT  34.08 46.883 35.256 47.219 ;
     RECT  59.1 43.285 59.784 47.315 ;
     RECT  21.168 46.933 21.612 47.651 ;
     RECT  26.112 41.939 27.012 47.653 ;
     RECT  25.92 47.653 27.012 47.845 ;
     RECT  34.08 47.219 35.112 48.181 ;
     RECT  56.4 2.151 56.712 48.229 ;
     RECT  33.888 48.181 35.112 48.421 ;
     RECT  40.08 43.523 40.512 48.421 ;
     RECT  57.744 43.955 57.768 48.421 ;
     RECT  59.1 47.315 59.412 48.421 ;
     RECT  29.4 46.883 32.52 48.469 ;
     RECT  24 47.171 24.312 48.949 ;
     RECT  25.344 47.845 27.012 48.949 ;
     RECT  57.744 48.421 59.412 49.571 ;
     RECT  39.792 48.421 40.512 49.763 ;
     RECT  29.28 48.469 32.52 49.811 ;
     RECT  33.888 48.421 35.352 50.147 ;
     RECT  29.4 49.811 32.52 50.149 ;
     RECT  33.888 50.147 35.208 50.149 ;
     RECT  24 48.949 27.012 50.195 ;
     RECT  21.3 47.651 21.612 50.245 ;
     RECT  40.08 49.763 40.512 50.339 ;
     RECT  42.9 2.151 43.212 50.437 ;
     RECT  42.528 50.437 43.212 50.677 ;
     RECT  59.1 49.571 59.412 50.965 ;
     RECT  29.4 50.149 35.208 51.107 ;
     RECT  29.4 51.107 32.52 51.205 ;
     RECT  33.888 51.107 35.208 51.301 ;
     RECT  21.3 50.245 22.104 51.347 ;
     RECT  24 50.195 25.128 51.395 ;
     RECT  33.888 51.301 35.304 51.491 ;
     RECT  45.6 45.685 46.872 51.541 ;
     RECT  42.192 50.677 43.212 51.635 ;
     RECT  56.304 48.229 56.712 51.779 ;
     RECT  45.504 51.541 46.872 51.923 ;
     RECT  33.888 51.491 35.256 52.163 ;
     RECT  28.752 51.205 32.52 52.165 ;
     RECT  28.512 52.165 32.52 52.405 ;
     RECT  28.512 52.405 33.096 52.499 ;
     RECT  37.5 38.915 37.812 52.789 ;
     RECT  37.5 52.789 38.664 52.837 ;
     RECT  24 51.395 24.312 52.933 ;
     RECT  45.504 51.923 45.912 52.981 ;
     RECT  36.384 43.955 36.408 53.029 ;
     RECT  45.504 52.981 46.008 53.077 ;
     RECT  57.744 49.571 57.768 53.173 ;
     RECT  58.992 50.965 59.412 53.173 ;
     RECT  57.744 53.173 59.412 53.219 ;
     RECT  22.848 52.549 22.872 53.555 ;
     RECT  26.7 50.195 27.012 53.557 ;
     RECT  27.984 52.837 28.008 53.557 ;
     RECT  37.5 52.837 39.192 53.603 ;
     RECT  56.4 51.779 56.712 53.797 ;
     RECT  37.5 53.603 38.76 54.035 ;
     RECT  24 52.933 24.504 54.085 ;
     RECT  40.2 50.339 40.512 54.085 ;
     RECT  23.472 54.085 24.504 54.179 ;
     RECT  45.504 53.077 46.056 54.323 ;
     RECT  36.24 53.029 36.408 54.421 ;
     RECT  34.8 52.163 35.256 54.467 ;
     RECT  45.504 54.323 46.008 54.467 ;
     RECT  47.184 52.837 47.208 54.563 ;
     RECT  26.7 53.557 28.008 54.755 ;
     RECT  36.24 54.421 36.504 54.755 ;
     RECT  45.504 54.467 45.912 54.899 ;
     RECT  42.528 51.635 43.212 55.093 ;
     RECT  40.2 54.085 40.632 55.139 ;
     RECT  29.4 52.499 33.096 55.283 ;
     RECT  56.016 53.797 56.712 55.429 ;
     RECT  37.5 54.035 37.992 55.525 ;
     RECT  36.528 55.525 37.992 55.571 ;
     RECT  23.472 54.179 24.312 55.715 ;
     RECT  42.048 55.093 43.212 55.955 ;
     RECT  34.8 54.467 35.208 56.197 ;
     RECT  36.528 55.571 37.812 56.197 ;
     RECT  40.2 55.139 40.512 56.245 ;
     RECT  25.632 54.997 25.656 56.291 ;
     RECT  27.984 54.755 28.008 56.291 ;
     RECT  55.968 55.429 56.712 56.627 ;
     RECT  29.4 55.283 32.52 57.299 ;
     RECT  34.8 56.197 37.812 57.299 ;
     RECT  56.4 56.627 56.712 57.493 ;
     RECT  42.432 55.955 43.212 57.925 ;
     RECT  31.584 57.299 32.52 58.691 ;
     RECT  58.272 53.219 59.412 58.739 ;
     RECT  40.08 56.245 40.512 59.315 ;
     RECT  34.8 57.299 35.112 59.317 ;
     RECT  36.528 57.299 37.812 59.317 ;
     RECT  34.8 59.317 37.812 59.459 ;
     RECT  45.6 54.899 45.912 59.509 ;
     RECT  29.4 57.299 30.216 59.797 ;
     RECT  23.712 55.715 24.312 59.843 ;
     RECT  31.92 58.691 32.412 59.891 ;
     RECT  44.928 59.509 45.912 60.371 ;
     RECT  28.512 59.797 30.216 60.515 ;
     RECT  37.5 59.459 37.812 60.613 ;
     RECT  41.664 57.925 43.212 60.707 ;
     RECT  31.968 59.891 32.412 61.043 ;
     RECT  37.392 60.613 37.812 61.043 ;
     RECT  42.9 60.707 43.212 61.045 ;
     RECT  53.7 2.151 54.012 61.093 ;
     RECT  56.4 57.493 57.048 61.139 ;
     RECT  59.1 58.739 59.412 61.621 ;
     RECT  38.928 60.469 38.952 61.907 ;
     RECT  34.8 59.459 35.976 62.005 ;
     RECT  34.608 62.005 35.976 62.195 ;
     RECT  42.9 61.045 43.8 62.195 ;
     RECT  53.7 61.093 54.696 62.195 ;
     RECT  58.512 61.621 59.412 62.195 ;
     RECT  41.664 60.707 41.688 62.483 ;
     RECT  29.4 60.515 30.216 62.581 ;
     RECT  32.1 61.043 32.412 62.581 ;
     RECT  2.4 30.803 2.712 62.649 ;
     RECT  5.1 23.747 5.412 62.649 ;
     RECT  7.8 2.151 8.112 62.649 ;
     RECT  10.5 2.151 10.812 62.649 ;
     RECT  13.2 38.723 13.512 62.649 ;
     RECT  15.9 2.151 16.212 62.649 ;
     RECT  18.6 2.151 18.912 62.649 ;
     RECT  21.3 51.347 21.612 62.649 ;
     RECT  24 59.843 24.312 62.649 ;
     RECT  26.7 54.755 27.012 62.649 ;
     RECT  34.608 62.195 35.112 62.649 ;
     RECT  37.5 61.043 37.812 62.649 ;
     RECT  40.2 59.315 40.512 62.649 ;
     RECT  42.9 62.195 43.212 62.649 ;
     RECT  45.6 60.371 45.912 62.649 ;
     RECT  48.3 45.731 48.612 62.649 ;
     RECT  51 2.151 51.312 62.649 ;
     RECT  53.7 62.195 54.012 62.649 ;
     RECT  56.4 61.139 56.712 62.649 ;
     RECT  59.1 62.195 59.412 62.649 ;
     RECT  61.8 44.579 62.112 62.649 ;
     RECT  2.4 62.649 2.52 62.663 ;
     RECT  5.1 62.649 5.22 62.663 ;
     RECT  7.8 62.649 7.92 62.663 ;
     RECT  10.5 62.649 10.62 62.663 ;
     RECT  13.2 62.649 13.32 62.663 ;
     RECT  15.9 62.649 16.02 62.663 ;
     RECT  18.6 62.649 18.72 62.663 ;
     RECT  21.3 62.649 21.42 62.663 ;
     RECT  24 62.649 24.12 62.663 ;
     RECT  26.7 62.649 26.82 62.663 ;
     RECT  29.4 62.581 30.6 62.663 ;
     RECT  34.608 62.649 34.92 62.663 ;
     RECT  37.5 62.649 37.62 62.663 ;
     RECT  40.2 62.649 40.32 62.663 ;
     RECT  42.9 62.649 43.02 62.663 ;
     RECT  45.6 62.649 45.72 62.663 ;
     RECT  48.3 62.649 48.42 62.663 ;
     RECT  51 62.649 51.12 62.663 ;
     RECT  53.7 62.649 53.82 62.663 ;
     RECT  56.4 62.649 56.52 62.663 ;
     RECT  59.1 62.649 59.22 62.663 ;
     RECT  61.8 62.649 61.92 62.663 ;
     RECT  32.1 62.581 33 62.677 ;
     RECT  34.608 62.663 34.632 62.677 ;
     RECT  30.192 62.663 30.6 64.784 ;
     RECT  31.776 62.677 34.632 64.784 ;
  END
END qkd_kvn_ctx_ovl_rope
END LIBRARY
